VERSION 5.7 ;
BUSBITCHARS "[]" ;
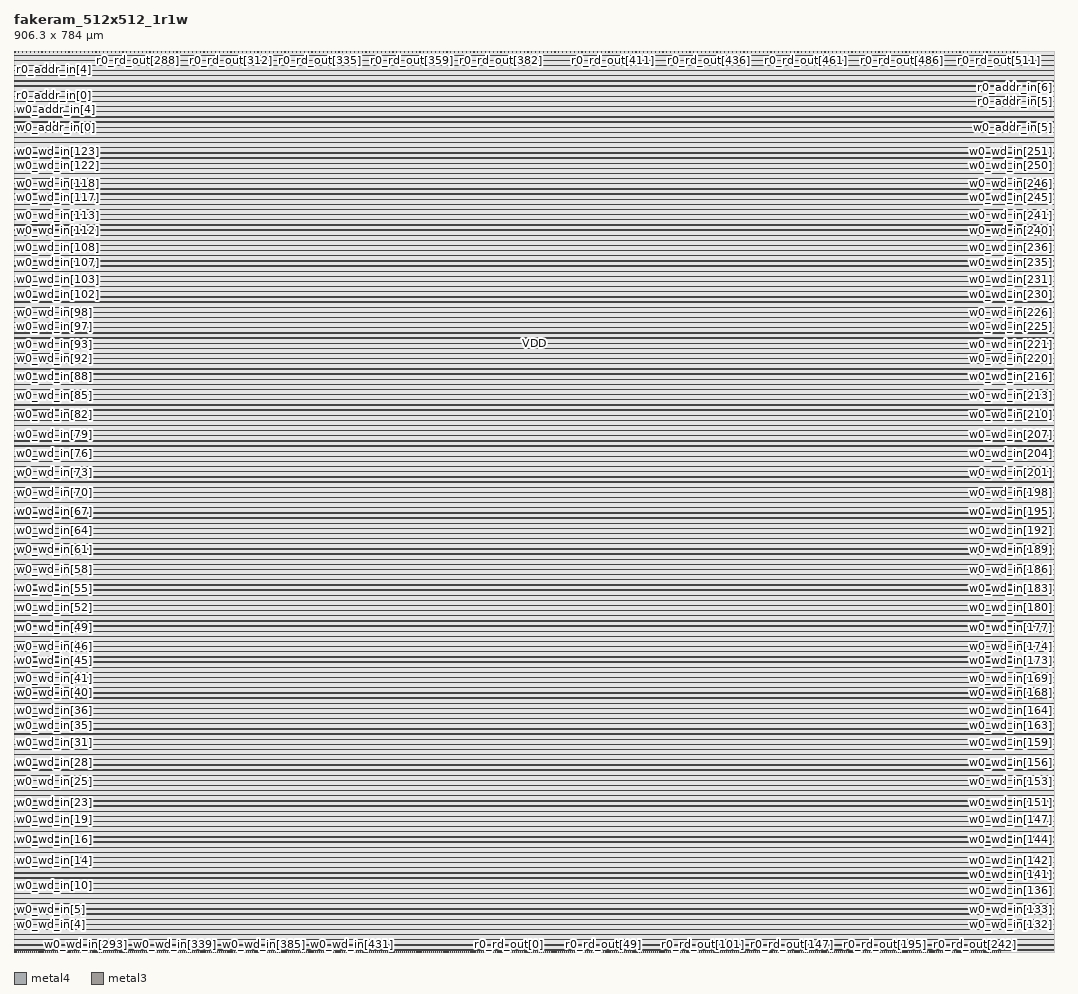
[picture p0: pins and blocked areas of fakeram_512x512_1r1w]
MACRO fakeram_512x512_1r1w
  FOREIGN fakeram_512x512_1r1w 0 0 ;
  SYMMETRY X Y R90 ;
  SIZE 906.300 BY 784.000 ;
  CLASS BLOCK ;
  PIN w0_wd_in[0]
    DIRECTION INPUT ;
    USE SIGNAL ;
    SHAPE ABUTMENT ;
    PORT
      LAYER metal4 ;
      RECT 0.000 1.645 0.210 1.715 ;
    END
  END w0_wd_in[0]
  PIN w0_wd_in[1]
    DIRECTION INPUT ;
    USE SIGNAL ;
    SHAPE ABUTMENT ;
    PORT
      LAYER metal4 ;
      RECT 0.000 7.245 0.210 7.315 ;
    END
  END w0_wd_in[1]
  PIN w0_wd_in[2]
    DIRECTION INPUT ;
    USE SIGNAL ;
    SHAPE ABUTMENT ;
    PORT
      LAYER metal4 ;
      RECT 0.000 12.845 0.210 12.915 ;
    END
  END w0_wd_in[2]
  PIN w0_wd_in[3]
    DIRECTION INPUT ;
    USE SIGNAL ;
    SHAPE ABUTMENT ;
    PORT
      LAYER metal4 ;
      RECT 0.000 18.445 0.210 18.515 ;
    END
  END w0_wd_in[3]
  PIN w0_wd_in[4]
    DIRECTION INPUT ;
    USE SIGNAL ;
    SHAPE ABUTMENT ;
    PORT
      LAYER metal4 ;
      RECT 0.000 24.045 0.210 24.115 ;
    END
  END w0_wd_in[4]
  PIN w0_wd_in[5]
    DIRECTION INPUT ;
    USE SIGNAL ;
    SHAPE ABUTMENT ;
    PORT
      LAYER metal4 ;
      RECT 0.000 29.645 0.210 29.715 ;
    END
  END w0_wd_in[5]
  PIN w0_wd_in[6]
    DIRECTION INPUT ;
    USE SIGNAL ;
    SHAPE ABUTMENT ;
    PORT
      LAYER metal4 ;
      RECT 0.000 35.245 0.210 35.315 ;
    END
  END w0_wd_in[6]
  PIN w0_wd_in[7]
    DIRECTION INPUT ;
    USE SIGNAL ;
    SHAPE ABUTMENT ;
    PORT
      LAYER metal4 ;
      RECT 0.000 40.845 0.210 40.915 ;
    END
  END w0_wd_in[7]
  PIN w0_wd_in[8]
    DIRECTION INPUT ;
    USE SIGNAL ;
    SHAPE ABUTMENT ;
    PORT
      LAYER metal4 ;
      RECT 0.000 46.445 0.210 46.515 ;
    END
  END w0_wd_in[8]
  PIN w0_wd_in[9]
    DIRECTION INPUT ;
    USE SIGNAL ;
    SHAPE ABUTMENT ;
    PORT
      LAYER metal4 ;
      RECT 0.000 52.045 0.210 52.115 ;
    END
  END w0_wd_in[9]
  PIN w0_wd_in[10]
    DIRECTION INPUT ;
    USE SIGNAL ;
    SHAPE ABUTMENT ;
    PORT
      LAYER metal4 ;
      RECT 0.000 57.645 0.210 57.715 ;
    END
  END w0_wd_in[10]
  PIN w0_wd_in[11]
    DIRECTION INPUT ;
    USE SIGNAL ;
    SHAPE ABUTMENT ;
    PORT
      LAYER metal4 ;
      RECT 0.000 63.245 0.210 63.315 ;
    END
  END w0_wd_in[11]
  PIN w0_wd_in[12]
    DIRECTION INPUT ;
    USE SIGNAL ;
    SHAPE ABUTMENT ;
    PORT
      LAYER metal4 ;
      RECT 0.000 68.845 0.210 68.915 ;
    END
  END w0_wd_in[12]
  PIN w0_wd_in[13]
    DIRECTION INPUT ;
    USE SIGNAL ;
    SHAPE ABUTMENT ;
    PORT
      LAYER metal4 ;
      RECT 0.000 74.445 0.210 74.515 ;
    END
  END w0_wd_in[13]
  PIN w0_wd_in[14]
    DIRECTION INPUT ;
    USE SIGNAL ;
    SHAPE ABUTMENT ;
    PORT
      LAYER metal4 ;
      RECT 0.000 80.045 0.210 80.115 ;
    END
  END w0_wd_in[14]
  PIN w0_wd_in[15]
    DIRECTION INPUT ;
    USE SIGNAL ;
    SHAPE ABUTMENT ;
    PORT
      LAYER metal4 ;
      RECT 0.000 85.645 0.210 85.715 ;
    END
  END w0_wd_in[15]
  PIN w0_wd_in[16]
    DIRECTION INPUT ;
    USE SIGNAL ;
    SHAPE ABUTMENT ;
    PORT
      LAYER metal4 ;
      RECT 0.000 91.245 0.210 91.315 ;
    END
  END w0_wd_in[16]
  PIN w0_wd_in[17]
    DIRECTION INPUT ;
    USE SIGNAL ;
    SHAPE ABUTMENT ;
    PORT
      LAYER metal4 ;
      RECT 0.000 96.845 0.210 96.915 ;
    END
  END w0_wd_in[17]
  PIN w0_wd_in[18]
    DIRECTION INPUT ;
    USE SIGNAL ;
    SHAPE ABUTMENT ;
    PORT
      LAYER metal4 ;
      RECT 0.000 102.445 0.210 102.515 ;
    END
  END w0_wd_in[18]
  PIN w0_wd_in[19]
    DIRECTION INPUT ;
    USE SIGNAL ;
    SHAPE ABUTMENT ;
    PORT
      LAYER metal4 ;
      RECT 0.000 108.045 0.210 108.115 ;
    END
  END w0_wd_in[19]
  PIN w0_wd_in[20]
    DIRECTION INPUT ;
    USE SIGNAL ;
    SHAPE ABUTMENT ;
    PORT
      LAYER metal4 ;
      RECT 0.000 113.645 0.210 113.715 ;
    END
  END w0_wd_in[20]
  PIN w0_wd_in[21]
    DIRECTION INPUT ;
    USE SIGNAL ;
    SHAPE ABUTMENT ;
    PORT
      LAYER metal4 ;
      RECT 0.000 119.245 0.210 119.315 ;
    END
  END w0_wd_in[21]
  PIN w0_wd_in[22]
    DIRECTION INPUT ;
    USE SIGNAL ;
    SHAPE ABUTMENT ;
    PORT
      LAYER metal4 ;
      RECT 0.000 124.845 0.210 124.915 ;
    END
  END w0_wd_in[22]
  PIN w0_wd_in[23]
    DIRECTION INPUT ;
    USE SIGNAL ;
    SHAPE ABUTMENT ;
    PORT
      LAYER metal4 ;
      RECT 0.000 130.445 0.210 130.515 ;
    END
  END w0_wd_in[23]
  PIN w0_wd_in[24]
    DIRECTION INPUT ;
    USE SIGNAL ;
    SHAPE ABUTMENT ;
    PORT
      LAYER metal4 ;
      RECT 0.000 136.045 0.210 136.115 ;
    END
  END w0_wd_in[24]
  PIN w0_wd_in[25]
    DIRECTION INPUT ;
    USE SIGNAL ;
    SHAPE ABUTMENT ;
    PORT
      LAYER metal4 ;
      RECT 0.000 141.645 0.210 141.715 ;
    END
  END w0_wd_in[25]
  PIN w0_wd_in[26]
    DIRECTION INPUT ;
    USE SIGNAL ;
    SHAPE ABUTMENT ;
    PORT
      LAYER metal4 ;
      RECT 0.000 147.245 0.210 147.315 ;
    END
  END w0_wd_in[26]
  PIN w0_wd_in[27]
    DIRECTION INPUT ;
    USE SIGNAL ;
    SHAPE ABUTMENT ;
    PORT
      LAYER metal4 ;
      RECT 0.000 152.845 0.210 152.915 ;
    END
  END w0_wd_in[27]
  PIN w0_wd_in[28]
    DIRECTION INPUT ;
    USE SIGNAL ;
    SHAPE ABUTMENT ;
    PORT
      LAYER metal4 ;
      RECT 0.000 158.445 0.210 158.515 ;
    END
  END w0_wd_in[28]
  PIN w0_wd_in[29]
    DIRECTION INPUT ;
    USE SIGNAL ;
    SHAPE ABUTMENT ;
    PORT
      LAYER metal4 ;
      RECT 0.000 164.045 0.210 164.115 ;
    END
  END w0_wd_in[29]
  PIN w0_wd_in[30]
    DIRECTION INPUT ;
    USE SIGNAL ;
    SHAPE ABUTMENT ;
    PORT
      LAYER metal4 ;
      RECT 0.000 169.645 0.210 169.715 ;
    END
  END w0_wd_in[30]
  PIN w0_wd_in[31]
    DIRECTION INPUT ;
    USE SIGNAL ;
    SHAPE ABUTMENT ;
    PORT
      LAYER metal4 ;
      RECT 0.000 175.245 0.210 175.315 ;
    END
  END w0_wd_in[31]
  PIN w0_wd_in[32]
    DIRECTION INPUT ;
    USE SIGNAL ;
    SHAPE ABUTMENT ;
    PORT
      LAYER metal4 ;
      RECT 0.000 180.845 0.210 180.915 ;
    END
  END w0_wd_in[32]
  PIN w0_wd_in[33]
    DIRECTION INPUT ;
    USE SIGNAL ;
    SHAPE ABUTMENT ;
    PORT
      LAYER metal4 ;
      RECT 0.000 186.445 0.210 186.515 ;
    END
  END w0_wd_in[33]
  PIN w0_wd_in[34]
    DIRECTION INPUT ;
    USE SIGNAL ;
    SHAPE ABUTMENT ;
    PORT
      LAYER metal4 ;
      RECT 0.000 192.045 0.210 192.115 ;
    END
  END w0_wd_in[34]
  PIN w0_wd_in[35]
    DIRECTION INPUT ;
    USE SIGNAL ;
    SHAPE ABUTMENT ;
    PORT
      LAYER metal4 ;
      RECT 0.000 197.645 0.210 197.715 ;
    END
  END w0_wd_in[35]
  PIN w0_wd_in[36]
    DIRECTION INPUT ;
    USE SIGNAL ;
    SHAPE ABUTMENT ;
    PORT
      LAYER metal4 ;
      RECT 0.000 203.245 0.210 203.315 ;
    END
  END w0_wd_in[36]
  PIN w0_wd_in[37]
    DIRECTION INPUT ;
    USE SIGNAL ;
    SHAPE ABUTMENT ;
    PORT
      LAYER metal4 ;
      RECT 0.000 208.845 0.210 208.915 ;
    END
  END w0_wd_in[37]
  PIN w0_wd_in[38]
    DIRECTION INPUT ;
    USE SIGNAL ;
    SHAPE ABUTMENT ;
    PORT
      LAYER metal4 ;
      RECT 0.000 214.445 0.210 214.515 ;
    END
  END w0_wd_in[38]
  PIN w0_wd_in[39]
    DIRECTION INPUT ;
    USE SIGNAL ;
    SHAPE ABUTMENT ;
    PORT
      LAYER metal4 ;
      RECT 0.000 220.045 0.210 220.115 ;
    END
  END w0_wd_in[39]
  PIN w0_wd_in[40]
    DIRECTION INPUT ;
    USE SIGNAL ;
    SHAPE ABUTMENT ;
    PORT
      LAYER metal4 ;
      RECT 0.000 225.645 0.210 225.715 ;
    END
  END w0_wd_in[40]
  PIN w0_wd_in[41]
    DIRECTION INPUT ;
    USE SIGNAL ;
    SHAPE ABUTMENT ;
    PORT
      LAYER metal4 ;
      RECT 0.000 231.245 0.210 231.315 ;
    END
  END w0_wd_in[41]
  PIN w0_wd_in[42]
    DIRECTION INPUT ;
    USE SIGNAL ;
    SHAPE ABUTMENT ;
    PORT
      LAYER metal4 ;
      RECT 0.000 236.845 0.210 236.915 ;
    END
  END w0_wd_in[42]
  PIN w0_wd_in[43]
    DIRECTION INPUT ;
    USE SIGNAL ;
    SHAPE ABUTMENT ;
    PORT
      LAYER metal4 ;
      RECT 0.000 242.445 0.210 242.515 ;
    END
  END w0_wd_in[43]
  PIN w0_wd_in[44]
    DIRECTION INPUT ;
    USE SIGNAL ;
    SHAPE ABUTMENT ;
    PORT
      LAYER metal4 ;
      RECT 0.000 248.045 0.210 248.115 ;
    END
  END w0_wd_in[44]
  PIN w0_wd_in[45]
    DIRECTION INPUT ;
    USE SIGNAL ;
    SHAPE ABUTMENT ;
    PORT
      LAYER metal4 ;
      RECT 0.000 253.645 0.210 253.715 ;
    END
  END w0_wd_in[45]
  PIN w0_wd_in[46]
    DIRECTION INPUT ;
    USE SIGNAL ;
    SHAPE ABUTMENT ;
    PORT
      LAYER metal4 ;
      RECT 0.000 259.245 0.210 259.315 ;
    END
  END w0_wd_in[46]
  PIN w0_wd_in[47]
    DIRECTION INPUT ;
    USE SIGNAL ;
    SHAPE ABUTMENT ;
    PORT
      LAYER metal4 ;
      RECT 0.000 264.845 0.210 264.915 ;
    END
  END w0_wd_in[47]
  PIN w0_wd_in[48]
    DIRECTION INPUT ;
    USE SIGNAL ;
    SHAPE ABUTMENT ;
    PORT
      LAYER metal4 ;
      RECT 0.000 270.445 0.210 270.515 ;
    END
  END w0_wd_in[48]
  PIN w0_wd_in[49]
    DIRECTION INPUT ;
    USE SIGNAL ;
    SHAPE ABUTMENT ;
    PORT
      LAYER metal4 ;
      RECT 0.000 276.045 0.210 276.115 ;
    END
  END w0_wd_in[49]
  PIN w0_wd_in[50]
    DIRECTION INPUT ;
    USE SIGNAL ;
    SHAPE ABUTMENT ;
    PORT
      LAYER metal4 ;
      RECT 0.000 281.645 0.210 281.715 ;
    END
  END w0_wd_in[50]
  PIN w0_wd_in[51]
    DIRECTION INPUT ;
    USE SIGNAL ;
    SHAPE ABUTMENT ;
    PORT
      LAYER metal4 ;
      RECT 0.000 287.245 0.210 287.315 ;
    END
  END w0_wd_in[51]
  PIN w0_wd_in[52]
    DIRECTION INPUT ;
    USE SIGNAL ;
    SHAPE ABUTMENT ;
    PORT
      LAYER metal4 ;
      RECT 0.000 292.845 0.210 292.915 ;
    END
  END w0_wd_in[52]
  PIN w0_wd_in[53]
    DIRECTION INPUT ;
    USE SIGNAL ;
    SHAPE ABUTMENT ;
    PORT
      LAYER metal4 ;
      RECT 0.000 298.445 0.210 298.515 ;
    END
  END w0_wd_in[53]
  PIN w0_wd_in[54]
    DIRECTION INPUT ;
    USE SIGNAL ;
    SHAPE ABUTMENT ;
    PORT
      LAYER metal4 ;
      RECT 0.000 304.045 0.210 304.115 ;
    END
  END w0_wd_in[54]
  PIN w0_wd_in[55]
    DIRECTION INPUT ;
    USE SIGNAL ;
    SHAPE ABUTMENT ;
    PORT
      LAYER metal4 ;
      RECT 0.000 309.645 0.210 309.715 ;
    END
  END w0_wd_in[55]
  PIN w0_wd_in[56]
    DIRECTION INPUT ;
    USE SIGNAL ;
    SHAPE ABUTMENT ;
    PORT
      LAYER metal4 ;
      RECT 0.000 315.245 0.210 315.315 ;
    END
  END w0_wd_in[56]
  PIN w0_wd_in[57]
    DIRECTION INPUT ;
    USE SIGNAL ;
    SHAPE ABUTMENT ;
    PORT
      LAYER metal4 ;
      RECT 0.000 320.845 0.210 320.915 ;
    END
  END w0_wd_in[57]
  PIN w0_wd_in[58]
    DIRECTION INPUT ;
    USE SIGNAL ;
    SHAPE ABUTMENT ;
    PORT
      LAYER metal4 ;
      RECT 0.000 326.445 0.210 326.515 ;
    END
  END w0_wd_in[58]
  PIN w0_wd_in[59]
    DIRECTION INPUT ;
    USE SIGNAL ;
    SHAPE ABUTMENT ;
    PORT
      LAYER metal4 ;
      RECT 0.000 332.045 0.210 332.115 ;
    END
  END w0_wd_in[59]
  PIN w0_wd_in[60]
    DIRECTION INPUT ;
    USE SIGNAL ;
    SHAPE ABUTMENT ;
    PORT
      LAYER metal4 ;
      RECT 0.000 337.645 0.210 337.715 ;
    END
  END w0_wd_in[60]
  PIN w0_wd_in[61]
    DIRECTION INPUT ;
    USE SIGNAL ;
    SHAPE ABUTMENT ;
    PORT
      LAYER metal4 ;
      RECT 0.000 343.245 0.210 343.315 ;
    END
  END w0_wd_in[61]
  PIN w0_wd_in[62]
    DIRECTION INPUT ;
    USE SIGNAL ;
    SHAPE ABUTMENT ;
    PORT
      LAYER metal4 ;
      RECT 0.000 348.845 0.210 348.915 ;
    END
  END w0_wd_in[62]
  PIN w0_wd_in[63]
    DIRECTION INPUT ;
    USE SIGNAL ;
    SHAPE ABUTMENT ;
    PORT
      LAYER metal4 ;
      RECT 0.000 354.445 0.210 354.515 ;
    END
  END w0_wd_in[63]
  PIN w0_wd_in[64]
    DIRECTION INPUT ;
    USE SIGNAL ;
    SHAPE ABUTMENT ;
    PORT
      LAYER metal4 ;
      RECT 0.000 360.045 0.210 360.115 ;
    END
  END w0_wd_in[64]
  PIN w0_wd_in[65]
    DIRECTION INPUT ;
    USE SIGNAL ;
    SHAPE ABUTMENT ;
    PORT
      LAYER metal4 ;
      RECT 0.000 365.645 0.210 365.715 ;
    END
  END w0_wd_in[65]
  PIN w0_wd_in[66]
    DIRECTION INPUT ;
    USE SIGNAL ;
    SHAPE ABUTMENT ;
    PORT
      LAYER metal4 ;
      RECT 0.000 371.245 0.210 371.315 ;
    END
  END w0_wd_in[66]
  PIN w0_wd_in[67]
    DIRECTION INPUT ;
    USE SIGNAL ;
    SHAPE ABUTMENT ;
    PORT
      LAYER metal4 ;
      RECT 0.000 376.845 0.210 376.915 ;
    END
  END w0_wd_in[67]
  PIN w0_wd_in[68]
    DIRECTION INPUT ;
    USE SIGNAL ;
    SHAPE ABUTMENT ;
    PORT
      LAYER metal4 ;
      RECT 0.000 382.445 0.210 382.515 ;
    END
  END w0_wd_in[68]
  PIN w0_wd_in[69]
    DIRECTION INPUT ;
    USE SIGNAL ;
    SHAPE ABUTMENT ;
    PORT
      LAYER metal4 ;
      RECT 0.000 388.045 0.210 388.115 ;
    END
  END w0_wd_in[69]
  PIN w0_wd_in[70]
    DIRECTION INPUT ;
    USE SIGNAL ;
    SHAPE ABUTMENT ;
    PORT
      LAYER metal4 ;
      RECT 0.000 393.645 0.210 393.715 ;
    END
  END w0_wd_in[70]
  PIN w0_wd_in[71]
    DIRECTION INPUT ;
    USE SIGNAL ;
    SHAPE ABUTMENT ;
    PORT
      LAYER metal4 ;
      RECT 0.000 399.245 0.210 399.315 ;
    END
  END w0_wd_in[71]
  PIN w0_wd_in[72]
    DIRECTION INPUT ;
    USE SIGNAL ;
    SHAPE ABUTMENT ;
    PORT
      LAYER metal4 ;
      RECT 0.000 404.845 0.210 404.915 ;
    END
  END w0_wd_in[72]
  PIN w0_wd_in[73]
    DIRECTION INPUT ;
    USE SIGNAL ;
    SHAPE ABUTMENT ;
    PORT
      LAYER metal4 ;
      RECT 0.000 410.445 0.210 410.515 ;
    END
  END w0_wd_in[73]
  PIN w0_wd_in[74]
    DIRECTION INPUT ;
    USE SIGNAL ;
    SHAPE ABUTMENT ;
    PORT
      LAYER metal4 ;
      RECT 0.000 416.045 0.210 416.115 ;
    END
  END w0_wd_in[74]
  PIN w0_wd_in[75]
    DIRECTION INPUT ;
    USE SIGNAL ;
    SHAPE ABUTMENT ;
    PORT
      LAYER metal4 ;
      RECT 0.000 421.645 0.210 421.715 ;
    END
  END w0_wd_in[75]
  PIN w0_wd_in[76]
    DIRECTION INPUT ;
    USE SIGNAL ;
    SHAPE ABUTMENT ;
    PORT
      LAYER metal4 ;
      RECT 0.000 427.245 0.210 427.315 ;
    END
  END w0_wd_in[76]
  PIN w0_wd_in[77]
    DIRECTION INPUT ;
    USE SIGNAL ;
    SHAPE ABUTMENT ;
    PORT
      LAYER metal4 ;
      RECT 0.000 432.845 0.210 432.915 ;
    END
  END w0_wd_in[77]
  PIN w0_wd_in[78]
    DIRECTION INPUT ;
    USE SIGNAL ;
    SHAPE ABUTMENT ;
    PORT
      LAYER metal4 ;
      RECT 0.000 438.445 0.210 438.515 ;
    END
  END w0_wd_in[78]
  PIN w0_wd_in[79]
    DIRECTION INPUT ;
    USE SIGNAL ;
    SHAPE ABUTMENT ;
    PORT
      LAYER metal4 ;
      RECT 0.000 444.045 0.210 444.115 ;
    END
  END w0_wd_in[79]
  PIN w0_wd_in[80]
    DIRECTION INPUT ;
    USE SIGNAL ;
    SHAPE ABUTMENT ;
    PORT
      LAYER metal4 ;
      RECT 0.000 449.645 0.210 449.715 ;
    END
  END w0_wd_in[80]
  PIN w0_wd_in[81]
    DIRECTION INPUT ;
    USE SIGNAL ;
    SHAPE ABUTMENT ;
    PORT
      LAYER metal4 ;
      RECT 0.000 455.245 0.210 455.315 ;
    END
  END w0_wd_in[81]
  PIN w0_wd_in[82]
    DIRECTION INPUT ;
    USE SIGNAL ;
    SHAPE ABUTMENT ;
    PORT
      LAYER metal4 ;
      RECT 0.000 460.845 0.210 460.915 ;
    END
  END w0_wd_in[82]
  PIN w0_wd_in[83]
    DIRECTION INPUT ;
    USE SIGNAL ;
    SHAPE ABUTMENT ;
    PORT
      LAYER metal4 ;
      RECT 0.000 466.445 0.210 466.515 ;
    END
  END w0_wd_in[83]
  PIN w0_wd_in[84]
    DIRECTION INPUT ;
    USE SIGNAL ;
    SHAPE ABUTMENT ;
    PORT
      LAYER metal4 ;
      RECT 0.000 472.045 0.210 472.115 ;
    END
  END w0_wd_in[84]
  PIN w0_wd_in[85]
    DIRECTION INPUT ;
    USE SIGNAL ;
    SHAPE ABUTMENT ;
    PORT
      LAYER metal4 ;
      RECT 0.000 477.645 0.210 477.715 ;
    END
  END w0_wd_in[85]
  PIN w0_wd_in[86]
    DIRECTION INPUT ;
    USE SIGNAL ;
    SHAPE ABUTMENT ;
    PORT
      LAYER metal4 ;
      RECT 0.000 483.245 0.210 483.315 ;
    END
  END w0_wd_in[86]
  PIN w0_wd_in[87]
    DIRECTION INPUT ;
    USE SIGNAL ;
    SHAPE ABUTMENT ;
    PORT
      LAYER metal4 ;
      RECT 0.000 488.845 0.210 488.915 ;
    END
  END w0_wd_in[87]
  PIN w0_wd_in[88]
    DIRECTION INPUT ;
    USE SIGNAL ;
    SHAPE ABUTMENT ;
    PORT
      LAYER metal4 ;
      RECT 0.000 494.445 0.210 494.515 ;
    END
  END w0_wd_in[88]
  PIN w0_wd_in[89]
    DIRECTION INPUT ;
    USE SIGNAL ;
    SHAPE ABUTMENT ;
    PORT
      LAYER metal4 ;
      RECT 0.000 500.045 0.210 500.115 ;
    END
  END w0_wd_in[89]
  PIN w0_wd_in[90]
    DIRECTION INPUT ;
    USE SIGNAL ;
    SHAPE ABUTMENT ;
    PORT
      LAYER metal4 ;
      RECT 0.000 505.645 0.210 505.715 ;
    END
  END w0_wd_in[90]
  PIN w0_wd_in[91]
    DIRECTION INPUT ;
    USE SIGNAL ;
    SHAPE ABUTMENT ;
    PORT
      LAYER metal4 ;
      RECT 0.000 511.245 0.210 511.315 ;
    END
  END w0_wd_in[91]
  PIN w0_wd_in[92]
    DIRECTION INPUT ;
    USE SIGNAL ;
    SHAPE ABUTMENT ;
    PORT
      LAYER metal4 ;
      RECT 0.000 516.845 0.210 516.915 ;
    END
  END w0_wd_in[92]
  PIN w0_wd_in[93]
    DIRECTION INPUT ;
    USE SIGNAL ;
    SHAPE ABUTMENT ;
    PORT
      LAYER metal4 ;
      RECT 0.000 522.445 0.210 522.515 ;
    END
  END w0_wd_in[93]
  PIN w0_wd_in[94]
    DIRECTION INPUT ;
    USE SIGNAL ;
    SHAPE ABUTMENT ;
    PORT
      LAYER metal4 ;
      RECT 0.000 528.045 0.210 528.115 ;
    END
  END w0_wd_in[94]
  PIN w0_wd_in[95]
    DIRECTION INPUT ;
    USE SIGNAL ;
    SHAPE ABUTMENT ;
    PORT
      LAYER metal4 ;
      RECT 0.000 533.645 0.210 533.715 ;
    END
  END w0_wd_in[95]
  PIN w0_wd_in[96]
    DIRECTION INPUT ;
    USE SIGNAL ;
    SHAPE ABUTMENT ;
    PORT
      LAYER metal4 ;
      RECT 0.000 539.245 0.210 539.315 ;
    END
  END w0_wd_in[96]
  PIN w0_wd_in[97]
    DIRECTION INPUT ;
    USE SIGNAL ;
    SHAPE ABUTMENT ;
    PORT
      LAYER metal4 ;
      RECT 0.000 544.845 0.210 544.915 ;
    END
  END w0_wd_in[97]
  PIN w0_wd_in[98]
    DIRECTION INPUT ;
    USE SIGNAL ;
    SHAPE ABUTMENT ;
    PORT
      LAYER metal4 ;
      RECT 0.000 550.445 0.210 550.515 ;
    END
  END w0_wd_in[98]
  PIN w0_wd_in[99]
    DIRECTION INPUT ;
    USE SIGNAL ;
    SHAPE ABUTMENT ;
    PORT
      LAYER metal4 ;
      RECT 0.000 556.045 0.210 556.115 ;
    END
  END w0_wd_in[99]
  PIN w0_wd_in[100]
    DIRECTION INPUT ;
    USE SIGNAL ;
    SHAPE ABUTMENT ;
    PORT
      LAYER metal4 ;
      RECT 0.000 561.645 0.210 561.715 ;
    END
  END w0_wd_in[100]
  PIN w0_wd_in[101]
    DIRECTION INPUT ;
    USE SIGNAL ;
    SHAPE ABUTMENT ;
    PORT
      LAYER metal4 ;
      RECT 0.000 567.245 0.210 567.315 ;
    END
  END w0_wd_in[101]
  PIN w0_wd_in[102]
    DIRECTION INPUT ;
    USE SIGNAL ;
    SHAPE ABUTMENT ;
    PORT
      LAYER metal4 ;
      RECT 0.000 572.845 0.210 572.915 ;
    END
  END w0_wd_in[102]
  PIN w0_wd_in[103]
    DIRECTION INPUT ;
    USE SIGNAL ;
    SHAPE ABUTMENT ;
    PORT
      LAYER metal4 ;
      RECT 0.000 578.445 0.210 578.515 ;
    END
  END w0_wd_in[103]
  PIN w0_wd_in[104]
    DIRECTION INPUT ;
    USE SIGNAL ;
    SHAPE ABUTMENT ;
    PORT
      LAYER metal4 ;
      RECT 0.000 584.045 0.210 584.115 ;
    END
  END w0_wd_in[104]
  PIN w0_wd_in[105]
    DIRECTION INPUT ;
    USE SIGNAL ;
    SHAPE ABUTMENT ;
    PORT
      LAYER metal4 ;
      RECT 0.000 589.645 0.210 589.715 ;
    END
  END w0_wd_in[105]
  PIN w0_wd_in[106]
    DIRECTION INPUT ;
    USE SIGNAL ;
    SHAPE ABUTMENT ;
    PORT
      LAYER metal4 ;
      RECT 0.000 595.245 0.210 595.315 ;
    END
  END w0_wd_in[106]
  PIN w0_wd_in[107]
    DIRECTION INPUT ;
    USE SIGNAL ;
    SHAPE ABUTMENT ;
    PORT
      LAYER metal4 ;
      RECT 0.000 600.845 0.210 600.915 ;
    END
  END w0_wd_in[107]
  PIN w0_wd_in[108]
    DIRECTION INPUT ;
    USE SIGNAL ;
    SHAPE ABUTMENT ;
    PORT
      LAYER metal4 ;
      RECT 0.000 606.445 0.210 606.515 ;
    END
  END w0_wd_in[108]
  PIN w0_wd_in[109]
    DIRECTION INPUT ;
    USE SIGNAL ;
    SHAPE ABUTMENT ;
    PORT
      LAYER metal4 ;
      RECT 0.000 612.045 0.210 612.115 ;
    END
  END w0_wd_in[109]
  PIN w0_wd_in[110]
    DIRECTION INPUT ;
    USE SIGNAL ;
    SHAPE ABUTMENT ;
    PORT
      LAYER metal4 ;
      RECT 0.000 617.645 0.210 617.715 ;
    END
  END w0_wd_in[110]
  PIN w0_wd_in[111]
    DIRECTION INPUT ;
    USE SIGNAL ;
    SHAPE ABUTMENT ;
    PORT
      LAYER metal4 ;
      RECT 0.000 623.245 0.210 623.315 ;
    END
  END w0_wd_in[111]
  PIN w0_wd_in[112]
    DIRECTION INPUT ;
    USE SIGNAL ;
    SHAPE ABUTMENT ;
    PORT
      LAYER metal4 ;
      RECT 0.000 628.845 0.210 628.915 ;
    END
  END w0_wd_in[112]
  PIN w0_wd_in[113]
    DIRECTION INPUT ;
    USE SIGNAL ;
    SHAPE ABUTMENT ;
    PORT
      LAYER metal4 ;
      RECT 0.000 634.445 0.210 634.515 ;
    END
  END w0_wd_in[113]
  PIN w0_wd_in[114]
    DIRECTION INPUT ;
    USE SIGNAL ;
    SHAPE ABUTMENT ;
    PORT
      LAYER metal4 ;
      RECT 0.000 640.045 0.210 640.115 ;
    END
  END w0_wd_in[114]
  PIN w0_wd_in[115]
    DIRECTION INPUT ;
    USE SIGNAL ;
    SHAPE ABUTMENT ;
    PORT
      LAYER metal4 ;
      RECT 0.000 645.645 0.210 645.715 ;
    END
  END w0_wd_in[115]
  PIN w0_wd_in[116]
    DIRECTION INPUT ;
    USE SIGNAL ;
    SHAPE ABUTMENT ;
    PORT
      LAYER metal4 ;
      RECT 0.000 651.245 0.210 651.315 ;
    END
  END w0_wd_in[116]
  PIN w0_wd_in[117]
    DIRECTION INPUT ;
    USE SIGNAL ;
    SHAPE ABUTMENT ;
    PORT
      LAYER metal4 ;
      RECT 0.000 656.845 0.210 656.915 ;
    END
  END w0_wd_in[117]
  PIN w0_wd_in[118]
    DIRECTION INPUT ;
    USE SIGNAL ;
    SHAPE ABUTMENT ;
    PORT
      LAYER metal4 ;
      RECT 0.000 662.445 0.210 662.515 ;
    END
  END w0_wd_in[118]
  PIN w0_wd_in[119]
    DIRECTION INPUT ;
    USE SIGNAL ;
    SHAPE ABUTMENT ;
    PORT
      LAYER metal4 ;
      RECT 0.000 668.045 0.210 668.115 ;
    END
  END w0_wd_in[119]
  PIN w0_wd_in[120]
    DIRECTION INPUT ;
    USE SIGNAL ;
    SHAPE ABUTMENT ;
    PORT
      LAYER metal4 ;
      RECT 0.000 673.645 0.210 673.715 ;
    END
  END w0_wd_in[120]
  PIN w0_wd_in[121]
    DIRECTION INPUT ;
    USE SIGNAL ;
    SHAPE ABUTMENT ;
    PORT
      LAYER metal4 ;
      RECT 0.000 679.245 0.210 679.315 ;
    END
  END w0_wd_in[121]
  PIN w0_wd_in[122]
    DIRECTION INPUT ;
    USE SIGNAL ;
    SHAPE ABUTMENT ;
    PORT
      LAYER metal4 ;
      RECT 0.000 684.845 0.210 684.915 ;
    END
  END w0_wd_in[122]
  PIN w0_wd_in[123]
    DIRECTION INPUT ;
    USE SIGNAL ;
    SHAPE ABUTMENT ;
    PORT
      LAYER metal4 ;
      RECT 0.000 690.445 0.210 690.515 ;
    END
  END w0_wd_in[123]
  PIN w0_wd_in[124]
    DIRECTION INPUT ;
    USE SIGNAL ;
    SHAPE ABUTMENT ;
    PORT
      LAYER metal4 ;
      RECT 0.000 696.045 0.210 696.115 ;
    END
  END w0_wd_in[124]
  PIN w0_wd_in[125]
    DIRECTION INPUT ;
    USE SIGNAL ;
    SHAPE ABUTMENT ;
    PORT
      LAYER metal4 ;
      RECT 0.000 701.645 0.210 701.715 ;
    END
  END w0_wd_in[125]
  PIN w0_wd_in[126]
    DIRECTION INPUT ;
    USE SIGNAL ;
    SHAPE ABUTMENT ;
    PORT
      LAYER metal4 ;
      RECT 0.000 707.245 0.210 707.315 ;
    END
  END w0_wd_in[126]
  PIN w0_wd_in[127]
    DIRECTION INPUT ;
    USE SIGNAL ;
    SHAPE ABUTMENT ;
    PORT
      LAYER metal4 ;
      RECT 0.000 712.845 0.210 712.915 ;
    END
  END w0_wd_in[127]
  PIN w0_wd_in[128]
    DIRECTION INPUT ;
    USE SIGNAL ;
    SHAPE ABUTMENT ;
    PORT
      LAYER metal4 ;
      RECT 906.090 1.645 906.300 1.715 ;
    END
  END w0_wd_in[128]
  PIN w0_wd_in[129]
    DIRECTION INPUT ;
    USE SIGNAL ;
    SHAPE ABUTMENT ;
    PORT
      LAYER metal4 ;
      RECT 906.090 7.245 906.300 7.315 ;
    END
  END w0_wd_in[129]
  PIN w0_wd_in[130]
    DIRECTION INPUT ;
    USE SIGNAL ;
    SHAPE ABUTMENT ;
    PORT
      LAYER metal4 ;
      RECT 906.090 12.845 906.300 12.915 ;
    END
  END w0_wd_in[130]
  PIN w0_wd_in[131]
    DIRECTION INPUT ;
    USE SIGNAL ;
    SHAPE ABUTMENT ;
    PORT
      LAYER metal4 ;
      RECT 906.090 18.445 906.300 18.515 ;
    END
  END w0_wd_in[131]
  PIN w0_wd_in[132]
    DIRECTION INPUT ;
    USE SIGNAL ;
    SHAPE ABUTMENT ;
    PORT
      LAYER metal4 ;
      RECT 906.090 24.045 906.300 24.115 ;
    END
  END w0_wd_in[132]
  PIN w0_wd_in[133]
    DIRECTION INPUT ;
    USE SIGNAL ;
    SHAPE ABUTMENT ;
    PORT
      LAYER metal4 ;
      RECT 906.090 29.645 906.300 29.715 ;
    END
  END w0_wd_in[133]
  PIN w0_wd_in[134]
    DIRECTION INPUT ;
    USE SIGNAL ;
    SHAPE ABUTMENT ;
    PORT
      LAYER metal4 ;
      RECT 906.090 35.245 906.300 35.315 ;
    END
  END w0_wd_in[134]
  PIN w0_wd_in[135]
    DIRECTION INPUT ;
    USE SIGNAL ;
    SHAPE ABUTMENT ;
    PORT
      LAYER metal4 ;
      RECT 906.090 40.845 906.300 40.915 ;
    END
  END w0_wd_in[135]
  PIN w0_wd_in[136]
    DIRECTION INPUT ;
    USE SIGNAL ;
    SHAPE ABUTMENT ;
    PORT
      LAYER metal4 ;
      RECT 906.090 46.445 906.300 46.515 ;
    END
  END w0_wd_in[136]
  PIN w0_wd_in[137]
    DIRECTION INPUT ;
    USE SIGNAL ;
    SHAPE ABUTMENT ;
    PORT
      LAYER metal4 ;
      RECT 906.090 52.045 906.300 52.115 ;
    END
  END w0_wd_in[137]
  PIN w0_wd_in[138]
    DIRECTION INPUT ;
    USE SIGNAL ;
    SHAPE ABUTMENT ;
    PORT
      LAYER metal4 ;
      RECT 906.090 57.645 906.300 57.715 ;
    END
  END w0_wd_in[138]
  PIN w0_wd_in[139]
    DIRECTION INPUT ;
    USE SIGNAL ;
    SHAPE ABUTMENT ;
    PORT
      LAYER metal4 ;
      RECT 906.090 63.245 906.300 63.315 ;
    END
  END w0_wd_in[139]
  PIN w0_wd_in[140]
    DIRECTION INPUT ;
    USE SIGNAL ;
    SHAPE ABUTMENT ;
    PORT
      LAYER metal4 ;
      RECT 906.090 68.845 906.300 68.915 ;
    END
  END w0_wd_in[140]
  PIN w0_wd_in[141]
    DIRECTION INPUT ;
    USE SIGNAL ;
    SHAPE ABUTMENT ;
    PORT
      LAYER metal4 ;
      RECT 906.090 74.445 906.300 74.515 ;
    END
  END w0_wd_in[141]
  PIN w0_wd_in[142]
    DIRECTION INPUT ;
    USE SIGNAL ;
    SHAPE ABUTMENT ;
    PORT
      LAYER metal4 ;
      RECT 906.090 80.045 906.300 80.115 ;
    END
  END w0_wd_in[142]
  PIN w0_wd_in[143]
    DIRECTION INPUT ;
    USE SIGNAL ;
    SHAPE ABUTMENT ;
    PORT
      LAYER metal4 ;
      RECT 906.090 85.645 906.300 85.715 ;
    END
  END w0_wd_in[143]
  PIN w0_wd_in[144]
    DIRECTION INPUT ;
    USE SIGNAL ;
    SHAPE ABUTMENT ;
    PORT
      LAYER metal4 ;
      RECT 906.090 91.245 906.300 91.315 ;
    END
  END w0_wd_in[144]
  PIN w0_wd_in[145]
    DIRECTION INPUT ;
    USE SIGNAL ;
    SHAPE ABUTMENT ;
    PORT
      LAYER metal4 ;
      RECT 906.090 96.845 906.300 96.915 ;
    END
  END w0_wd_in[145]
  PIN w0_wd_in[146]
    DIRECTION INPUT ;
    USE SIGNAL ;
    SHAPE ABUTMENT ;
    PORT
      LAYER metal4 ;
      RECT 906.090 102.445 906.300 102.515 ;
    END
  END w0_wd_in[146]
  PIN w0_wd_in[147]
    DIRECTION INPUT ;
    USE SIGNAL ;
    SHAPE ABUTMENT ;
    PORT
      LAYER metal4 ;
      RECT 906.090 108.045 906.300 108.115 ;
    END
  END w0_wd_in[147]
  PIN w0_wd_in[148]
    DIRECTION INPUT ;
    USE SIGNAL ;
    SHAPE ABUTMENT ;
    PORT
      LAYER metal4 ;
      RECT 906.090 113.645 906.300 113.715 ;
    END
  END w0_wd_in[148]
  PIN w0_wd_in[149]
    DIRECTION INPUT ;
    USE SIGNAL ;
    SHAPE ABUTMENT ;
    PORT
      LAYER metal4 ;
      RECT 906.090 119.245 906.300 119.315 ;
    END
  END w0_wd_in[149]
  PIN w0_wd_in[150]
    DIRECTION INPUT ;
    USE SIGNAL ;
    SHAPE ABUTMENT ;
    PORT
      LAYER metal4 ;
      RECT 906.090 124.845 906.300 124.915 ;
    END
  END w0_wd_in[150]
  PIN w0_wd_in[151]
    DIRECTION INPUT ;
    USE SIGNAL ;
    SHAPE ABUTMENT ;
    PORT
      LAYER metal4 ;
      RECT 906.090 130.445 906.300 130.515 ;
    END
  END w0_wd_in[151]
  PIN w0_wd_in[152]
    DIRECTION INPUT ;
    USE SIGNAL ;
    SHAPE ABUTMENT ;
    PORT
      LAYER metal4 ;
      RECT 906.090 136.045 906.300 136.115 ;
    END
  END w0_wd_in[152]
  PIN w0_wd_in[153]
    DIRECTION INPUT ;
    USE SIGNAL ;
    SHAPE ABUTMENT ;
    PORT
      LAYER metal4 ;
      RECT 906.090 141.645 906.300 141.715 ;
    END
  END w0_wd_in[153]
  PIN w0_wd_in[154]
    DIRECTION INPUT ;
    USE SIGNAL ;
    SHAPE ABUTMENT ;
    PORT
      LAYER metal4 ;
      RECT 906.090 147.245 906.300 147.315 ;
    END
  END w0_wd_in[154]
  PIN w0_wd_in[155]
    DIRECTION INPUT ;
    USE SIGNAL ;
    SHAPE ABUTMENT ;
    PORT
      LAYER metal4 ;
      RECT 906.090 152.845 906.300 152.915 ;
    END
  END w0_wd_in[155]
  PIN w0_wd_in[156]
    DIRECTION INPUT ;
    USE SIGNAL ;
    SHAPE ABUTMENT ;
    PORT
      LAYER metal4 ;
      RECT 906.090 158.445 906.300 158.515 ;
    END
  END w0_wd_in[156]
  PIN w0_wd_in[157]
    DIRECTION INPUT ;
    USE SIGNAL ;
    SHAPE ABUTMENT ;
    PORT
      LAYER metal4 ;
      RECT 906.090 164.045 906.300 164.115 ;
    END
  END w0_wd_in[157]
  PIN w0_wd_in[158]
    DIRECTION INPUT ;
    USE SIGNAL ;
    SHAPE ABUTMENT ;
    PORT
      LAYER metal4 ;
      RECT 906.090 169.645 906.300 169.715 ;
    END
  END w0_wd_in[158]
  PIN w0_wd_in[159]
    DIRECTION INPUT ;
    USE SIGNAL ;
    SHAPE ABUTMENT ;
    PORT
      LAYER metal4 ;
      RECT 906.090 175.245 906.300 175.315 ;
    END
  END w0_wd_in[159]
  PIN w0_wd_in[160]
    DIRECTION INPUT ;
    USE SIGNAL ;
    SHAPE ABUTMENT ;
    PORT
      LAYER metal4 ;
      RECT 906.090 180.845 906.300 180.915 ;
    END
  END w0_wd_in[160]
  PIN w0_wd_in[161]
    DIRECTION INPUT ;
    USE SIGNAL ;
    SHAPE ABUTMENT ;
    PORT
      LAYER metal4 ;
      RECT 906.090 186.445 906.300 186.515 ;
    END
  END w0_wd_in[161]
  PIN w0_wd_in[162]
    DIRECTION INPUT ;
    USE SIGNAL ;
    SHAPE ABUTMENT ;
    PORT
      LAYER metal4 ;
      RECT 906.090 192.045 906.300 192.115 ;
    END
  END w0_wd_in[162]
  PIN w0_wd_in[163]
    DIRECTION INPUT ;
    USE SIGNAL ;
    SHAPE ABUTMENT ;
    PORT
      LAYER metal4 ;
      RECT 906.090 197.645 906.300 197.715 ;
    END
  END w0_wd_in[163]
  PIN w0_wd_in[164]
    DIRECTION INPUT ;
    USE SIGNAL ;
    SHAPE ABUTMENT ;
    PORT
      LAYER metal4 ;
      RECT 906.090 203.245 906.300 203.315 ;
    END
  END w0_wd_in[164]
  PIN w0_wd_in[165]
    DIRECTION INPUT ;
    USE SIGNAL ;
    SHAPE ABUTMENT ;
    PORT
      LAYER metal4 ;
      RECT 906.090 208.845 906.300 208.915 ;
    END
  END w0_wd_in[165]
  PIN w0_wd_in[166]
    DIRECTION INPUT ;
    USE SIGNAL ;
    SHAPE ABUTMENT ;
    PORT
      LAYER metal4 ;
      RECT 906.090 214.445 906.300 214.515 ;
    END
  END w0_wd_in[166]
  PIN w0_wd_in[167]
    DIRECTION INPUT ;
    USE SIGNAL ;
    SHAPE ABUTMENT ;
    PORT
      LAYER metal4 ;
      RECT 906.090 220.045 906.300 220.115 ;
    END
  END w0_wd_in[167]
  PIN w0_wd_in[168]
    DIRECTION INPUT ;
    USE SIGNAL ;
    SHAPE ABUTMENT ;
    PORT
      LAYER metal4 ;
      RECT 906.090 225.645 906.300 225.715 ;
    END
  END w0_wd_in[168]
  PIN w0_wd_in[169]
    DIRECTION INPUT ;
    USE SIGNAL ;
    SHAPE ABUTMENT ;
    PORT
      LAYER metal4 ;
      RECT 906.090 231.245 906.300 231.315 ;
    END
  END w0_wd_in[169]
  PIN w0_wd_in[170]
    DIRECTION INPUT ;
    USE SIGNAL ;
    SHAPE ABUTMENT ;
    PORT
      LAYER metal4 ;
      RECT 906.090 236.845 906.300 236.915 ;
    END
  END w0_wd_in[170]
  PIN w0_wd_in[171]
    DIRECTION INPUT ;
    USE SIGNAL ;
    SHAPE ABUTMENT ;
    PORT
      LAYER metal4 ;
      RECT 906.090 242.445 906.300 242.515 ;
    END
  END w0_wd_in[171]
  PIN w0_wd_in[172]
    DIRECTION INPUT ;
    USE SIGNAL ;
    SHAPE ABUTMENT ;
    PORT
      LAYER metal4 ;
      RECT 906.090 248.045 906.300 248.115 ;
    END
  END w0_wd_in[172]
  PIN w0_wd_in[173]
    DIRECTION INPUT ;
    USE SIGNAL ;
    SHAPE ABUTMENT ;
    PORT
      LAYER metal4 ;
      RECT 906.090 253.645 906.300 253.715 ;
    END
  END w0_wd_in[173]
  PIN w0_wd_in[174]
    DIRECTION INPUT ;
    USE SIGNAL ;
    SHAPE ABUTMENT ;
    PORT
      LAYER metal4 ;
      RECT 906.090 259.245 906.300 259.315 ;
    END
  END w0_wd_in[174]
  PIN w0_wd_in[175]
    DIRECTION INPUT ;
    USE SIGNAL ;
    SHAPE ABUTMENT ;
    PORT
      LAYER metal4 ;
      RECT 906.090 264.845 906.300 264.915 ;
    END
  END w0_wd_in[175]
  PIN w0_wd_in[176]
    DIRECTION INPUT ;
    USE SIGNAL ;
    SHAPE ABUTMENT ;
    PORT
      LAYER metal4 ;
      RECT 906.090 270.445 906.300 270.515 ;
    END
  END w0_wd_in[176]
  PIN w0_wd_in[177]
    DIRECTION INPUT ;
    USE SIGNAL ;
    SHAPE ABUTMENT ;
    PORT
      LAYER metal4 ;
      RECT 906.090 276.045 906.300 276.115 ;
    END
  END w0_wd_in[177]
  PIN w0_wd_in[178]
    DIRECTION INPUT ;
    USE SIGNAL ;
    SHAPE ABUTMENT ;
    PORT
      LAYER metal4 ;
      RECT 906.090 281.645 906.300 281.715 ;
    END
  END w0_wd_in[178]
  PIN w0_wd_in[179]
    DIRECTION INPUT ;
    USE SIGNAL ;
    SHAPE ABUTMENT ;
    PORT
      LAYER metal4 ;
      RECT 906.090 287.245 906.300 287.315 ;
    END
  END w0_wd_in[179]
  PIN w0_wd_in[180]
    DIRECTION INPUT ;
    USE SIGNAL ;
    SHAPE ABUTMENT ;
    PORT
      LAYER metal4 ;
      RECT 906.090 292.845 906.300 292.915 ;
    END
  END w0_wd_in[180]
  PIN w0_wd_in[181]
    DIRECTION INPUT ;
    USE SIGNAL ;
    SHAPE ABUTMENT ;
    PORT
      LAYER metal4 ;
      RECT 906.090 298.445 906.300 298.515 ;
    END
  END w0_wd_in[181]
  PIN w0_wd_in[182]
    DIRECTION INPUT ;
    USE SIGNAL ;
    SHAPE ABUTMENT ;
    PORT
      LAYER metal4 ;
      RECT 906.090 304.045 906.300 304.115 ;
    END
  END w0_wd_in[182]
  PIN w0_wd_in[183]
    DIRECTION INPUT ;
    USE SIGNAL ;
    SHAPE ABUTMENT ;
    PORT
      LAYER metal4 ;
      RECT 906.090 309.645 906.300 309.715 ;
    END
  END w0_wd_in[183]
  PIN w0_wd_in[184]
    DIRECTION INPUT ;
    USE SIGNAL ;
    SHAPE ABUTMENT ;
    PORT
      LAYER metal4 ;
      RECT 906.090 315.245 906.300 315.315 ;
    END
  END w0_wd_in[184]
  PIN w0_wd_in[185]
    DIRECTION INPUT ;
    USE SIGNAL ;
    SHAPE ABUTMENT ;
    PORT
      LAYER metal4 ;
      RECT 906.090 320.845 906.300 320.915 ;
    END
  END w0_wd_in[185]
  PIN w0_wd_in[186]
    DIRECTION INPUT ;
    USE SIGNAL ;
    SHAPE ABUTMENT ;
    PORT
      LAYER metal4 ;
      RECT 906.090 326.445 906.300 326.515 ;
    END
  END w0_wd_in[186]
  PIN w0_wd_in[187]
    DIRECTION INPUT ;
    USE SIGNAL ;
    SHAPE ABUTMENT ;
    PORT
      LAYER metal4 ;
      RECT 906.090 332.045 906.300 332.115 ;
    END
  END w0_wd_in[187]
  PIN w0_wd_in[188]
    DIRECTION INPUT ;
    USE SIGNAL ;
    SHAPE ABUTMENT ;
    PORT
      LAYER metal4 ;
      RECT 906.090 337.645 906.300 337.715 ;
    END
  END w0_wd_in[188]
  PIN w0_wd_in[189]
    DIRECTION INPUT ;
    USE SIGNAL ;
    SHAPE ABUTMENT ;
    PORT
      LAYER metal4 ;
      RECT 906.090 343.245 906.300 343.315 ;
    END
  END w0_wd_in[189]
  PIN w0_wd_in[190]
    DIRECTION INPUT ;
    USE SIGNAL ;
    SHAPE ABUTMENT ;
    PORT
      LAYER metal4 ;
      RECT 906.090 348.845 906.300 348.915 ;
    END
  END w0_wd_in[190]
  PIN w0_wd_in[191]
    DIRECTION INPUT ;
    USE SIGNAL ;
    SHAPE ABUTMENT ;
    PORT
      LAYER metal4 ;
      RECT 906.090 354.445 906.300 354.515 ;
    END
  END w0_wd_in[191]
  PIN w0_wd_in[192]
    DIRECTION INPUT ;
    USE SIGNAL ;
    SHAPE ABUTMENT ;
    PORT
      LAYER metal4 ;
      RECT 906.090 360.045 906.300 360.115 ;
    END
  END w0_wd_in[192]
  PIN w0_wd_in[193]
    DIRECTION INPUT ;
    USE SIGNAL ;
    SHAPE ABUTMENT ;
    PORT
      LAYER metal4 ;
      RECT 906.090 365.645 906.300 365.715 ;
    END
  END w0_wd_in[193]
  PIN w0_wd_in[194]
    DIRECTION INPUT ;
    USE SIGNAL ;
    SHAPE ABUTMENT ;
    PORT
      LAYER metal4 ;
      RECT 906.090 371.245 906.300 371.315 ;
    END
  END w0_wd_in[194]
  PIN w0_wd_in[195]
    DIRECTION INPUT ;
    USE SIGNAL ;
    SHAPE ABUTMENT ;
    PORT
      LAYER metal4 ;
      RECT 906.090 376.845 906.300 376.915 ;
    END
  END w0_wd_in[195]
  PIN w0_wd_in[196]
    DIRECTION INPUT ;
    USE SIGNAL ;
    SHAPE ABUTMENT ;
    PORT
      LAYER metal4 ;
      RECT 906.090 382.445 906.300 382.515 ;
    END
  END w0_wd_in[196]
  PIN w0_wd_in[197]
    DIRECTION INPUT ;
    USE SIGNAL ;
    SHAPE ABUTMENT ;
    PORT
      LAYER metal4 ;
      RECT 906.090 388.045 906.300 388.115 ;
    END
  END w0_wd_in[197]
  PIN w0_wd_in[198]
    DIRECTION INPUT ;
    USE SIGNAL ;
    SHAPE ABUTMENT ;
    PORT
      LAYER metal4 ;
      RECT 906.090 393.645 906.300 393.715 ;
    END
  END w0_wd_in[198]
  PIN w0_wd_in[199]
    DIRECTION INPUT ;
    USE SIGNAL ;
    SHAPE ABUTMENT ;
    PORT
      LAYER metal4 ;
      RECT 906.090 399.245 906.300 399.315 ;
    END
  END w0_wd_in[199]
  PIN w0_wd_in[200]
    DIRECTION INPUT ;
    USE SIGNAL ;
    SHAPE ABUTMENT ;
    PORT
      LAYER metal4 ;
      RECT 906.090 404.845 906.300 404.915 ;
    END
  END w0_wd_in[200]
  PIN w0_wd_in[201]
    DIRECTION INPUT ;
    USE SIGNAL ;
    SHAPE ABUTMENT ;
    PORT
      LAYER metal4 ;
      RECT 906.090 410.445 906.300 410.515 ;
    END
  END w0_wd_in[201]
  PIN w0_wd_in[202]
    DIRECTION INPUT ;
    USE SIGNAL ;
    SHAPE ABUTMENT ;
    PORT
      LAYER metal4 ;
      RECT 906.090 416.045 906.300 416.115 ;
    END
  END w0_wd_in[202]
  PIN w0_wd_in[203]
    DIRECTION INPUT ;
    USE SIGNAL ;
    SHAPE ABUTMENT ;
    PORT
      LAYER metal4 ;
      RECT 906.090 421.645 906.300 421.715 ;
    END
  END w0_wd_in[203]
  PIN w0_wd_in[204]
    DIRECTION INPUT ;
    USE SIGNAL ;
    SHAPE ABUTMENT ;
    PORT
      LAYER metal4 ;
      RECT 906.090 427.245 906.300 427.315 ;
    END
  END w0_wd_in[204]
  PIN w0_wd_in[205]
    DIRECTION INPUT ;
    USE SIGNAL ;
    SHAPE ABUTMENT ;
    PORT
      LAYER metal4 ;
      RECT 906.090 432.845 906.300 432.915 ;
    END
  END w0_wd_in[205]
  PIN w0_wd_in[206]
    DIRECTION INPUT ;
    USE SIGNAL ;
    SHAPE ABUTMENT ;
    PORT
      LAYER metal4 ;
      RECT 906.090 438.445 906.300 438.515 ;
    END
  END w0_wd_in[206]
  PIN w0_wd_in[207]
    DIRECTION INPUT ;
    USE SIGNAL ;
    SHAPE ABUTMENT ;
    PORT
      LAYER metal4 ;
      RECT 906.090 444.045 906.300 444.115 ;
    END
  END w0_wd_in[207]
  PIN w0_wd_in[208]
    DIRECTION INPUT ;
    USE SIGNAL ;
    SHAPE ABUTMENT ;
    PORT
      LAYER metal4 ;
      RECT 906.090 449.645 906.300 449.715 ;
    END
  END w0_wd_in[208]
  PIN w0_wd_in[209]
    DIRECTION INPUT ;
    USE SIGNAL ;
    SHAPE ABUTMENT ;
    PORT
      LAYER metal4 ;
      RECT 906.090 455.245 906.300 455.315 ;
    END
  END w0_wd_in[209]
  PIN w0_wd_in[210]
    DIRECTION INPUT ;
    USE SIGNAL ;
    SHAPE ABUTMENT ;
    PORT
      LAYER metal4 ;
      RECT 906.090 460.845 906.300 460.915 ;
    END
  END w0_wd_in[210]
  PIN w0_wd_in[211]
    DIRECTION INPUT ;
    USE SIGNAL ;
    SHAPE ABUTMENT ;
    PORT
      LAYER metal4 ;
      RECT 906.090 466.445 906.300 466.515 ;
    END
  END w0_wd_in[211]
  PIN w0_wd_in[212]
    DIRECTION INPUT ;
    USE SIGNAL ;
    SHAPE ABUTMENT ;
    PORT
      LAYER metal4 ;
      RECT 906.090 472.045 906.300 472.115 ;
    END
  END w0_wd_in[212]
  PIN w0_wd_in[213]
    DIRECTION INPUT ;
    USE SIGNAL ;
    SHAPE ABUTMENT ;
    PORT
      LAYER metal4 ;
      RECT 906.090 477.645 906.300 477.715 ;
    END
  END w0_wd_in[213]
  PIN w0_wd_in[214]
    DIRECTION INPUT ;
    USE SIGNAL ;
    SHAPE ABUTMENT ;
    PORT
      LAYER metal4 ;
      RECT 906.090 483.245 906.300 483.315 ;
    END
  END w0_wd_in[214]
  PIN w0_wd_in[215]
    DIRECTION INPUT ;
    USE SIGNAL ;
    SHAPE ABUTMENT ;
    PORT
      LAYER metal4 ;
      RECT 906.090 488.845 906.300 488.915 ;
    END
  END w0_wd_in[215]
  PIN w0_wd_in[216]
    DIRECTION INPUT ;
    USE SIGNAL ;
    SHAPE ABUTMENT ;
    PORT
      LAYER metal4 ;
      RECT 906.090 494.445 906.300 494.515 ;
    END
  END w0_wd_in[216]
  PIN w0_wd_in[217]
    DIRECTION INPUT ;
    USE SIGNAL ;
    SHAPE ABUTMENT ;
    PORT
      LAYER metal4 ;
      RECT 906.090 500.045 906.300 500.115 ;
    END
  END w0_wd_in[217]
  PIN w0_wd_in[218]
    DIRECTION INPUT ;
    USE SIGNAL ;
    SHAPE ABUTMENT ;
    PORT
      LAYER metal4 ;
      RECT 906.090 505.645 906.300 505.715 ;
    END
  END w0_wd_in[218]
  PIN w0_wd_in[219]
    DIRECTION INPUT ;
    USE SIGNAL ;
    SHAPE ABUTMENT ;
    PORT
      LAYER metal4 ;
      RECT 906.090 511.245 906.300 511.315 ;
    END
  END w0_wd_in[219]
  PIN w0_wd_in[220]
    DIRECTION INPUT ;
    USE SIGNAL ;
    SHAPE ABUTMENT ;
    PORT
      LAYER metal4 ;
      RECT 906.090 516.845 906.300 516.915 ;
    END
  END w0_wd_in[220]
  PIN w0_wd_in[221]
    DIRECTION INPUT ;
    USE SIGNAL ;
    SHAPE ABUTMENT ;
    PORT
      LAYER metal4 ;
      RECT 906.090 522.445 906.300 522.515 ;
    END
  END w0_wd_in[221]
  PIN w0_wd_in[222]
    DIRECTION INPUT ;
    USE SIGNAL ;
    SHAPE ABUTMENT ;
    PORT
      LAYER metal4 ;
      RECT 906.090 528.045 906.300 528.115 ;
    END
  END w0_wd_in[222]
  PIN w0_wd_in[223]
    DIRECTION INPUT ;
    USE SIGNAL ;
    SHAPE ABUTMENT ;
    PORT
      LAYER metal4 ;
      RECT 906.090 533.645 906.300 533.715 ;
    END
  END w0_wd_in[223]
  PIN w0_wd_in[224]
    DIRECTION INPUT ;
    USE SIGNAL ;
    SHAPE ABUTMENT ;
    PORT
      LAYER metal4 ;
      RECT 906.090 539.245 906.300 539.315 ;
    END
  END w0_wd_in[224]
  PIN w0_wd_in[225]
    DIRECTION INPUT ;
    USE SIGNAL ;
    SHAPE ABUTMENT ;
    PORT
      LAYER metal4 ;
      RECT 906.090 544.845 906.300 544.915 ;
    END
  END w0_wd_in[225]
  PIN w0_wd_in[226]
    DIRECTION INPUT ;
    USE SIGNAL ;
    SHAPE ABUTMENT ;
    PORT
      LAYER metal4 ;
      RECT 906.090 550.445 906.300 550.515 ;
    END
  END w0_wd_in[226]
  PIN w0_wd_in[227]
    DIRECTION INPUT ;
    USE SIGNAL ;
    SHAPE ABUTMENT ;
    PORT
      LAYER metal4 ;
      RECT 906.090 556.045 906.300 556.115 ;
    END
  END w0_wd_in[227]
  PIN w0_wd_in[228]
    DIRECTION INPUT ;
    USE SIGNAL ;
    SHAPE ABUTMENT ;
    PORT
      LAYER metal4 ;
      RECT 906.090 561.645 906.300 561.715 ;
    END
  END w0_wd_in[228]
  PIN w0_wd_in[229]
    DIRECTION INPUT ;
    USE SIGNAL ;
    SHAPE ABUTMENT ;
    PORT
      LAYER metal4 ;
      RECT 906.090 567.245 906.300 567.315 ;
    END
  END w0_wd_in[229]
  PIN w0_wd_in[230]
    DIRECTION INPUT ;
    USE SIGNAL ;
    SHAPE ABUTMENT ;
    PORT
      LAYER metal4 ;
      RECT 906.090 572.845 906.300 572.915 ;
    END
  END w0_wd_in[230]
  PIN w0_wd_in[231]
    DIRECTION INPUT ;
    USE SIGNAL ;
    SHAPE ABUTMENT ;
    PORT
      LAYER metal4 ;
      RECT 906.090 578.445 906.300 578.515 ;
    END
  END w0_wd_in[231]
  PIN w0_wd_in[232]
    DIRECTION INPUT ;
    USE SIGNAL ;
    SHAPE ABUTMENT ;
    PORT
      LAYER metal4 ;
      RECT 906.090 584.045 906.300 584.115 ;
    END
  END w0_wd_in[232]
  PIN w0_wd_in[233]
    DIRECTION INPUT ;
    USE SIGNAL ;
    SHAPE ABUTMENT ;
    PORT
      LAYER metal4 ;
      RECT 906.090 589.645 906.300 589.715 ;
    END
  END w0_wd_in[233]
  PIN w0_wd_in[234]
    DIRECTION INPUT ;
    USE SIGNAL ;
    SHAPE ABUTMENT ;
    PORT
      LAYER metal4 ;
      RECT 906.090 595.245 906.300 595.315 ;
    END
  END w0_wd_in[234]
  PIN w0_wd_in[235]
    DIRECTION INPUT ;
    USE SIGNAL ;
    SHAPE ABUTMENT ;
    PORT
      LAYER metal4 ;
      RECT 906.090 600.845 906.300 600.915 ;
    END
  END w0_wd_in[235]
  PIN w0_wd_in[236]
    DIRECTION INPUT ;
    USE SIGNAL ;
    SHAPE ABUTMENT ;
    PORT
      LAYER metal4 ;
      RECT 906.090 606.445 906.300 606.515 ;
    END
  END w0_wd_in[236]
  PIN w0_wd_in[237]
    DIRECTION INPUT ;
    USE SIGNAL ;
    SHAPE ABUTMENT ;
    PORT
      LAYER metal4 ;
      RECT 906.090 612.045 906.300 612.115 ;
    END
  END w0_wd_in[237]
  PIN w0_wd_in[238]
    DIRECTION INPUT ;
    USE SIGNAL ;
    SHAPE ABUTMENT ;
    PORT
      LAYER metal4 ;
      RECT 906.090 617.645 906.300 617.715 ;
    END
  END w0_wd_in[238]
  PIN w0_wd_in[239]
    DIRECTION INPUT ;
    USE SIGNAL ;
    SHAPE ABUTMENT ;
    PORT
      LAYER metal4 ;
      RECT 906.090 623.245 906.300 623.315 ;
    END
  END w0_wd_in[239]
  PIN w0_wd_in[240]
    DIRECTION INPUT ;
    USE SIGNAL ;
    SHAPE ABUTMENT ;
    PORT
      LAYER metal4 ;
      RECT 906.090 628.845 906.300 628.915 ;
    END
  END w0_wd_in[240]
  PIN w0_wd_in[241]
    DIRECTION INPUT ;
    USE SIGNAL ;
    SHAPE ABUTMENT ;
    PORT
      LAYER metal4 ;
      RECT 906.090 634.445 906.300 634.515 ;
    END
  END w0_wd_in[241]
  PIN w0_wd_in[242]
    DIRECTION INPUT ;
    USE SIGNAL ;
    SHAPE ABUTMENT ;
    PORT
      LAYER metal4 ;
      RECT 906.090 640.045 906.300 640.115 ;
    END
  END w0_wd_in[242]
  PIN w0_wd_in[243]
    DIRECTION INPUT ;
    USE SIGNAL ;
    SHAPE ABUTMENT ;
    PORT
      LAYER metal4 ;
      RECT 906.090 645.645 906.300 645.715 ;
    END
  END w0_wd_in[243]
  PIN w0_wd_in[244]
    DIRECTION INPUT ;
    USE SIGNAL ;
    SHAPE ABUTMENT ;
    PORT
      LAYER metal4 ;
      RECT 906.090 651.245 906.300 651.315 ;
    END
  END w0_wd_in[244]
  PIN w0_wd_in[245]
    DIRECTION INPUT ;
    USE SIGNAL ;
    SHAPE ABUTMENT ;
    PORT
      LAYER metal4 ;
      RECT 906.090 656.845 906.300 656.915 ;
    END
  END w0_wd_in[245]
  PIN w0_wd_in[246]
    DIRECTION INPUT ;
    USE SIGNAL ;
    SHAPE ABUTMENT ;
    PORT
      LAYER metal4 ;
      RECT 906.090 662.445 906.300 662.515 ;
    END
  END w0_wd_in[246]
  PIN w0_wd_in[247]
    DIRECTION INPUT ;
    USE SIGNAL ;
    SHAPE ABUTMENT ;
    PORT
      LAYER metal4 ;
      RECT 906.090 668.045 906.300 668.115 ;
    END
  END w0_wd_in[247]
  PIN w0_wd_in[248]
    DIRECTION INPUT ;
    USE SIGNAL ;
    SHAPE ABUTMENT ;
    PORT
      LAYER metal4 ;
      RECT 906.090 673.645 906.300 673.715 ;
    END
  END w0_wd_in[248]
  PIN w0_wd_in[249]
    DIRECTION INPUT ;
    USE SIGNAL ;
    SHAPE ABUTMENT ;
    PORT
      LAYER metal4 ;
      RECT 906.090 679.245 906.300 679.315 ;
    END
  END w0_wd_in[249]
  PIN w0_wd_in[250]
    DIRECTION INPUT ;
    USE SIGNAL ;
    SHAPE ABUTMENT ;
    PORT
      LAYER metal4 ;
      RECT 906.090 684.845 906.300 684.915 ;
    END
  END w0_wd_in[250]
  PIN w0_wd_in[251]
    DIRECTION INPUT ;
    USE SIGNAL ;
    SHAPE ABUTMENT ;
    PORT
      LAYER metal4 ;
      RECT 906.090 690.445 906.300 690.515 ;
    END
  END w0_wd_in[251]
  PIN w0_wd_in[252]
    DIRECTION INPUT ;
    USE SIGNAL ;
    SHAPE ABUTMENT ;
    PORT
      LAYER metal4 ;
      RECT 906.090 696.045 906.300 696.115 ;
    END
  END w0_wd_in[252]
  PIN w0_wd_in[253]
    DIRECTION INPUT ;
    USE SIGNAL ;
    SHAPE ABUTMENT ;
    PORT
      LAYER metal4 ;
      RECT 906.090 701.645 906.300 701.715 ;
    END
  END w0_wd_in[253]
  PIN w0_wd_in[254]
    DIRECTION INPUT ;
    USE SIGNAL ;
    SHAPE ABUTMENT ;
    PORT
      LAYER metal4 ;
      RECT 906.090 707.245 906.300 707.315 ;
    END
  END w0_wd_in[254]
  PIN w0_wd_in[255]
    DIRECTION INPUT ;
    USE SIGNAL ;
    SHAPE ABUTMENT ;
    PORT
      LAYER metal4 ;
      RECT 906.090 712.845 906.300 712.915 ;
    END
  END w0_wd_in[255]
  PIN w0_wd_in[256]
    DIRECTION OUTPUT ;
    USE SIGNAL ;
    SHAPE ABUTMENT ;
    PORT
      LAYER metal3 ;
      RECT 0.805 0.000 0.875 0.210 ;
    END
  END w0_wd_in[256]
  PIN w0_wd_in[257]
    DIRECTION OUTPUT ;
    USE SIGNAL ;
    SHAPE ABUTMENT ;
    PORT
      LAYER metal3 ;
      RECT 2.485 0.000 2.555 0.210 ;
    END
  END w0_wd_in[257]
  PIN w0_wd_in[258]
    DIRECTION OUTPUT ;
    USE SIGNAL ;
    SHAPE ABUTMENT ;
    PORT
      LAYER metal3 ;
      RECT 4.165 0.000 4.235 0.210 ;
    END
  END w0_wd_in[258]
  PIN w0_wd_in[259]
    DIRECTION OUTPUT ;
    USE SIGNAL ;
    SHAPE ABUTMENT ;
    PORT
      LAYER metal3 ;
      RECT 5.845 0.000 5.915 0.210 ;
    END
  END w0_wd_in[259]
  PIN w0_wd_in[260]
    DIRECTION OUTPUT ;
    USE SIGNAL ;
    SHAPE ABUTMENT ;
    PORT
      LAYER metal3 ;
      RECT 7.525 0.000 7.595 0.210 ;
    END
  END w0_wd_in[260]
  PIN w0_wd_in[261]
    DIRECTION OUTPUT ;
    USE SIGNAL ;
    SHAPE ABUTMENT ;
    PORT
      LAYER metal3 ;
      RECT 9.205 0.000 9.275 0.210 ;
    END
  END w0_wd_in[261]
  PIN w0_wd_in[262]
    DIRECTION OUTPUT ;
    USE SIGNAL ;
    SHAPE ABUTMENT ;
    PORT
      LAYER metal3 ;
      RECT 10.885 0.000 10.955 0.210 ;
    END
  END w0_wd_in[262]
  PIN w0_wd_in[263]
    DIRECTION OUTPUT ;
    USE SIGNAL ;
    SHAPE ABUTMENT ;
    PORT
      LAYER metal3 ;
      RECT 12.565 0.000 12.635 0.210 ;
    END
  END w0_wd_in[263]
  PIN w0_wd_in[264]
    DIRECTION OUTPUT ;
    USE SIGNAL ;
    SHAPE ABUTMENT ;
    PORT
      LAYER metal3 ;
      RECT 14.245 0.000 14.315 0.210 ;
    END
  END w0_wd_in[264]
  PIN w0_wd_in[265]
    DIRECTION OUTPUT ;
    USE SIGNAL ;
    SHAPE ABUTMENT ;
    PORT
      LAYER metal3 ;
      RECT 15.925 0.000 15.995 0.210 ;
    END
  END w0_wd_in[265]
  PIN w0_wd_in[266]
    DIRECTION OUTPUT ;
    USE SIGNAL ;
    SHAPE ABUTMENT ;
    PORT
      LAYER metal3 ;
      RECT 17.605 0.000 17.675 0.210 ;
    END
  END w0_wd_in[266]
  PIN w0_wd_in[267]
    DIRECTION OUTPUT ;
    USE SIGNAL ;
    SHAPE ABUTMENT ;
    PORT
      LAYER metal3 ;
      RECT 19.285 0.000 19.355 0.210 ;
    END
  END w0_wd_in[267]
  PIN w0_wd_in[268]
    DIRECTION OUTPUT ;
    USE SIGNAL ;
    SHAPE ABUTMENT ;
    PORT
      LAYER metal3 ;
      RECT 20.965 0.000 21.035 0.210 ;
    END
  END w0_wd_in[268]
  PIN w0_wd_in[269]
    DIRECTION OUTPUT ;
    USE SIGNAL ;
    SHAPE ABUTMENT ;
    PORT
      LAYER metal3 ;
      RECT 22.645 0.000 22.715 0.210 ;
    END
  END w0_wd_in[269]
  PIN w0_wd_in[270]
    DIRECTION OUTPUT ;
    USE SIGNAL ;
    SHAPE ABUTMENT ;
    PORT
      LAYER metal3 ;
      RECT 24.325 0.000 24.395 0.210 ;
    END
  END w0_wd_in[270]
  PIN w0_wd_in[271]
    DIRECTION OUTPUT ;
    USE SIGNAL ;
    SHAPE ABUTMENT ;
    PORT
      LAYER metal3 ;
      RECT 26.005 0.000 26.075 0.210 ;
    END
  END w0_wd_in[271]
  PIN w0_wd_in[272]
    DIRECTION OUTPUT ;
    USE SIGNAL ;
    SHAPE ABUTMENT ;
    PORT
      LAYER metal3 ;
      RECT 27.685 0.000 27.755 0.210 ;
    END
  END w0_wd_in[272]
  PIN w0_wd_in[273]
    DIRECTION OUTPUT ;
    USE SIGNAL ;
    SHAPE ABUTMENT ;
    PORT
      LAYER metal3 ;
      RECT 29.365 0.000 29.435 0.210 ;
    END
  END w0_wd_in[273]
  PIN w0_wd_in[274]
    DIRECTION OUTPUT ;
    USE SIGNAL ;
    SHAPE ABUTMENT ;
    PORT
      LAYER metal3 ;
      RECT 31.045 0.000 31.115 0.210 ;
    END
  END w0_wd_in[274]
  PIN w0_wd_in[275]
    DIRECTION OUTPUT ;
    USE SIGNAL ;
    SHAPE ABUTMENT ;
    PORT
      LAYER metal3 ;
      RECT 32.725 0.000 32.795 0.210 ;
    END
  END w0_wd_in[275]
  PIN w0_wd_in[276]
    DIRECTION OUTPUT ;
    USE SIGNAL ;
    SHAPE ABUTMENT ;
    PORT
      LAYER metal3 ;
      RECT 34.405 0.000 34.475 0.210 ;
    END
  END w0_wd_in[276]
  PIN w0_wd_in[277]
    DIRECTION OUTPUT ;
    USE SIGNAL ;
    SHAPE ABUTMENT ;
    PORT
      LAYER metal3 ;
      RECT 36.085 0.000 36.155 0.210 ;
    END
  END w0_wd_in[277]
  PIN w0_wd_in[278]
    DIRECTION OUTPUT ;
    USE SIGNAL ;
    SHAPE ABUTMENT ;
    PORT
      LAYER metal3 ;
      RECT 37.765 0.000 37.835 0.210 ;
    END
  END w0_wd_in[278]
  PIN w0_wd_in[279]
    DIRECTION OUTPUT ;
    USE SIGNAL ;
    SHAPE ABUTMENT ;
    PORT
      LAYER metal3 ;
      RECT 39.445 0.000 39.515 0.210 ;
    END
  END w0_wd_in[279]
  PIN w0_wd_in[280]
    DIRECTION OUTPUT ;
    USE SIGNAL ;
    SHAPE ABUTMENT ;
    PORT
      LAYER metal3 ;
      RECT 41.125 0.000 41.195 0.210 ;
    END
  END w0_wd_in[280]
  PIN w0_wd_in[281]
    DIRECTION OUTPUT ;
    USE SIGNAL ;
    SHAPE ABUTMENT ;
    PORT
      LAYER metal3 ;
      RECT 42.805 0.000 42.875 0.210 ;
    END
  END w0_wd_in[281]
  PIN w0_wd_in[282]
    DIRECTION OUTPUT ;
    USE SIGNAL ;
    SHAPE ABUTMENT ;
    PORT
      LAYER metal3 ;
      RECT 44.485 0.000 44.555 0.210 ;
    END
  END w0_wd_in[282]
  PIN w0_wd_in[283]
    DIRECTION OUTPUT ;
    USE SIGNAL ;
    SHAPE ABUTMENT ;
    PORT
      LAYER metal3 ;
      RECT 46.165 0.000 46.235 0.210 ;
    END
  END w0_wd_in[283]
  PIN w0_wd_in[284]
    DIRECTION OUTPUT ;
    USE SIGNAL ;
    SHAPE ABUTMENT ;
    PORT
      LAYER metal3 ;
      RECT 47.845 0.000 47.915 0.210 ;
    END
  END w0_wd_in[284]
  PIN w0_wd_in[285]
    DIRECTION OUTPUT ;
    USE SIGNAL ;
    SHAPE ABUTMENT ;
    PORT
      LAYER metal3 ;
      RECT 49.525 0.000 49.595 0.210 ;
    END
  END w0_wd_in[285]
  PIN w0_wd_in[286]
    DIRECTION OUTPUT ;
    USE SIGNAL ;
    SHAPE ABUTMENT ;
    PORT
      LAYER metal3 ;
      RECT 51.205 0.000 51.275 0.210 ;
    END
  END w0_wd_in[286]
  PIN w0_wd_in[287]
    DIRECTION OUTPUT ;
    USE SIGNAL ;
    SHAPE ABUTMENT ;
    PORT
      LAYER metal3 ;
      RECT 52.885 0.000 52.955 0.210 ;
    END
  END w0_wd_in[287]
  PIN w0_wd_in[288]
    DIRECTION OUTPUT ;
    USE SIGNAL ;
    SHAPE ABUTMENT ;
    PORT
      LAYER metal3 ;
      RECT 54.565 0.000 54.635 0.210 ;
    END
  END w0_wd_in[288]
  PIN w0_wd_in[289]
    DIRECTION OUTPUT ;
    USE SIGNAL ;
    SHAPE ABUTMENT ;
    PORT
      LAYER metal3 ;
      RECT 56.245 0.000 56.315 0.210 ;
    END
  END w0_wd_in[289]
  PIN w0_wd_in[290]
    DIRECTION OUTPUT ;
    USE SIGNAL ;
    SHAPE ABUTMENT ;
    PORT
      LAYER metal3 ;
      RECT 57.925 0.000 57.995 0.210 ;
    END
  END w0_wd_in[290]
  PIN w0_wd_in[291]
    DIRECTION OUTPUT ;
    USE SIGNAL ;
    SHAPE ABUTMENT ;
    PORT
      LAYER metal3 ;
      RECT 59.605 0.000 59.675 0.210 ;
    END
  END w0_wd_in[291]
  PIN w0_wd_in[292]
    DIRECTION OUTPUT ;
    USE SIGNAL ;
    SHAPE ABUTMENT ;
    PORT
      LAYER metal3 ;
      RECT 61.285 0.000 61.355 0.210 ;
    END
  END w0_wd_in[292]
  PIN w0_wd_in[293]
    DIRECTION OUTPUT ;
    USE SIGNAL ;
    SHAPE ABUTMENT ;
    PORT
      LAYER metal3 ;
      RECT 62.965 0.000 63.035 0.210 ;
    END
  END w0_wd_in[293]
  PIN w0_wd_in[294]
    DIRECTION OUTPUT ;
    USE SIGNAL ;
    SHAPE ABUTMENT ;
    PORT
      LAYER metal3 ;
      RECT 64.645 0.000 64.715 0.210 ;
    END
  END w0_wd_in[294]
  PIN w0_wd_in[295]
    DIRECTION OUTPUT ;
    USE SIGNAL ;
    SHAPE ABUTMENT ;
    PORT
      LAYER metal3 ;
      RECT 66.325 0.000 66.395 0.210 ;
    END
  END w0_wd_in[295]
  PIN w0_wd_in[296]
    DIRECTION OUTPUT ;
    USE SIGNAL ;
    SHAPE ABUTMENT ;
    PORT
      LAYER metal3 ;
      RECT 68.005 0.000 68.075 0.210 ;
    END
  END w0_wd_in[296]
  PIN w0_wd_in[297]
    DIRECTION OUTPUT ;
    USE SIGNAL ;
    SHAPE ABUTMENT ;
    PORT
      LAYER metal3 ;
      RECT 69.685 0.000 69.755 0.210 ;
    END
  END w0_wd_in[297]
  PIN w0_wd_in[298]
    DIRECTION OUTPUT ;
    USE SIGNAL ;
    SHAPE ABUTMENT ;
    PORT
      LAYER metal3 ;
      RECT 71.365 0.000 71.435 0.210 ;
    END
  END w0_wd_in[298]
  PIN w0_wd_in[299]
    DIRECTION OUTPUT ;
    USE SIGNAL ;
    SHAPE ABUTMENT ;
    PORT
      LAYER metal3 ;
      RECT 73.045 0.000 73.115 0.210 ;
    END
  END w0_wd_in[299]
  PIN w0_wd_in[300]
    DIRECTION OUTPUT ;
    USE SIGNAL ;
    SHAPE ABUTMENT ;
    PORT
      LAYER metal3 ;
      RECT 74.725 0.000 74.795 0.210 ;
    END
  END w0_wd_in[300]
  PIN w0_wd_in[301]
    DIRECTION OUTPUT ;
    USE SIGNAL ;
    SHAPE ABUTMENT ;
    PORT
      LAYER metal3 ;
      RECT 76.405 0.000 76.475 0.210 ;
    END
  END w0_wd_in[301]
  PIN w0_wd_in[302]
    DIRECTION OUTPUT ;
    USE SIGNAL ;
    SHAPE ABUTMENT ;
    PORT
      LAYER metal3 ;
      RECT 78.085 0.000 78.155 0.210 ;
    END
  END w0_wd_in[302]
  PIN w0_wd_in[303]
    DIRECTION OUTPUT ;
    USE SIGNAL ;
    SHAPE ABUTMENT ;
    PORT
      LAYER metal3 ;
      RECT 79.765 0.000 79.835 0.210 ;
    END
  END w0_wd_in[303]
  PIN w0_wd_in[304]
    DIRECTION OUTPUT ;
    USE SIGNAL ;
    SHAPE ABUTMENT ;
    PORT
      LAYER metal3 ;
      RECT 81.445 0.000 81.515 0.210 ;
    END
  END w0_wd_in[304]
  PIN w0_wd_in[305]
    DIRECTION OUTPUT ;
    USE SIGNAL ;
    SHAPE ABUTMENT ;
    PORT
      LAYER metal3 ;
      RECT 83.125 0.000 83.195 0.210 ;
    END
  END w0_wd_in[305]
  PIN w0_wd_in[306]
    DIRECTION OUTPUT ;
    USE SIGNAL ;
    SHAPE ABUTMENT ;
    PORT
      LAYER metal3 ;
      RECT 84.805 0.000 84.875 0.210 ;
    END
  END w0_wd_in[306]
  PIN w0_wd_in[307]
    DIRECTION OUTPUT ;
    USE SIGNAL ;
    SHAPE ABUTMENT ;
    PORT
      LAYER metal3 ;
      RECT 86.485 0.000 86.555 0.210 ;
    END
  END w0_wd_in[307]
  PIN w0_wd_in[308]
    DIRECTION OUTPUT ;
    USE SIGNAL ;
    SHAPE ABUTMENT ;
    PORT
      LAYER metal3 ;
      RECT 88.165 0.000 88.235 0.210 ;
    END
  END w0_wd_in[308]
  PIN w0_wd_in[309]
    DIRECTION OUTPUT ;
    USE SIGNAL ;
    SHAPE ABUTMENT ;
    PORT
      LAYER metal3 ;
      RECT 89.845 0.000 89.915 0.210 ;
    END
  END w0_wd_in[309]
  PIN w0_wd_in[310]
    DIRECTION OUTPUT ;
    USE SIGNAL ;
    SHAPE ABUTMENT ;
    PORT
      LAYER metal3 ;
      RECT 91.525 0.000 91.595 0.210 ;
    END
  END w0_wd_in[310]
  PIN w0_wd_in[311]
    DIRECTION OUTPUT ;
    USE SIGNAL ;
    SHAPE ABUTMENT ;
    PORT
      LAYER metal3 ;
      RECT 93.205 0.000 93.275 0.210 ;
    END
  END w0_wd_in[311]
  PIN w0_wd_in[312]
    DIRECTION OUTPUT ;
    USE SIGNAL ;
    SHAPE ABUTMENT ;
    PORT
      LAYER metal3 ;
      RECT 94.885 0.000 94.955 0.210 ;
    END
  END w0_wd_in[312]
  PIN w0_wd_in[313]
    DIRECTION OUTPUT ;
    USE SIGNAL ;
    SHAPE ABUTMENT ;
    PORT
      LAYER metal3 ;
      RECT 96.565 0.000 96.635 0.210 ;
    END
  END w0_wd_in[313]
  PIN w0_wd_in[314]
    DIRECTION OUTPUT ;
    USE SIGNAL ;
    SHAPE ABUTMENT ;
    PORT
      LAYER metal3 ;
      RECT 98.245 0.000 98.315 0.210 ;
    END
  END w0_wd_in[314]
  PIN w0_wd_in[315]
    DIRECTION OUTPUT ;
    USE SIGNAL ;
    SHAPE ABUTMENT ;
    PORT
      LAYER metal3 ;
      RECT 99.925 0.000 99.995 0.210 ;
    END
  END w0_wd_in[315]
  PIN w0_wd_in[316]
    DIRECTION OUTPUT ;
    USE SIGNAL ;
    SHAPE ABUTMENT ;
    PORT
      LAYER metal3 ;
      RECT 101.605 0.000 101.675 0.210 ;
    END
  END w0_wd_in[316]
  PIN w0_wd_in[317]
    DIRECTION OUTPUT ;
    USE SIGNAL ;
    SHAPE ABUTMENT ;
    PORT
      LAYER metal3 ;
      RECT 103.285 0.000 103.355 0.210 ;
    END
  END w0_wd_in[317]
  PIN w0_wd_in[318]
    DIRECTION OUTPUT ;
    USE SIGNAL ;
    SHAPE ABUTMENT ;
    PORT
      LAYER metal3 ;
      RECT 104.965 0.000 105.035 0.210 ;
    END
  END w0_wd_in[318]
  PIN w0_wd_in[319]
    DIRECTION OUTPUT ;
    USE SIGNAL ;
    SHAPE ABUTMENT ;
    PORT
      LAYER metal3 ;
      RECT 106.645 0.000 106.715 0.210 ;
    END
  END w0_wd_in[319]
  PIN w0_wd_in[320]
    DIRECTION OUTPUT ;
    USE SIGNAL ;
    SHAPE ABUTMENT ;
    PORT
      LAYER metal3 ;
      RECT 108.325 0.000 108.395 0.210 ;
    END
  END w0_wd_in[320]
  PIN w0_wd_in[321]
    DIRECTION OUTPUT ;
    USE SIGNAL ;
    SHAPE ABUTMENT ;
    PORT
      LAYER metal3 ;
      RECT 110.005 0.000 110.075 0.210 ;
    END
  END w0_wd_in[321]
  PIN w0_wd_in[322]
    DIRECTION OUTPUT ;
    USE SIGNAL ;
    SHAPE ABUTMENT ;
    PORT
      LAYER metal3 ;
      RECT 111.685 0.000 111.755 0.210 ;
    END
  END w0_wd_in[322]
  PIN w0_wd_in[323]
    DIRECTION OUTPUT ;
    USE SIGNAL ;
    SHAPE ABUTMENT ;
    PORT
      LAYER metal3 ;
      RECT 113.365 0.000 113.435 0.210 ;
    END
  END w0_wd_in[323]
  PIN w0_wd_in[324]
    DIRECTION OUTPUT ;
    USE SIGNAL ;
    SHAPE ABUTMENT ;
    PORT
      LAYER metal3 ;
      RECT 115.045 0.000 115.115 0.210 ;
    END
  END w0_wd_in[324]
  PIN w0_wd_in[325]
    DIRECTION OUTPUT ;
    USE SIGNAL ;
    SHAPE ABUTMENT ;
    PORT
      LAYER metal3 ;
      RECT 116.725 0.000 116.795 0.210 ;
    END
  END w0_wd_in[325]
  PIN w0_wd_in[326]
    DIRECTION OUTPUT ;
    USE SIGNAL ;
    SHAPE ABUTMENT ;
    PORT
      LAYER metal3 ;
      RECT 118.405 0.000 118.475 0.210 ;
    END
  END w0_wd_in[326]
  PIN w0_wd_in[327]
    DIRECTION OUTPUT ;
    USE SIGNAL ;
    SHAPE ABUTMENT ;
    PORT
      LAYER metal3 ;
      RECT 120.085 0.000 120.155 0.210 ;
    END
  END w0_wd_in[327]
  PIN w0_wd_in[328]
    DIRECTION OUTPUT ;
    USE SIGNAL ;
    SHAPE ABUTMENT ;
    PORT
      LAYER metal3 ;
      RECT 121.765 0.000 121.835 0.210 ;
    END
  END w0_wd_in[328]
  PIN w0_wd_in[329]
    DIRECTION OUTPUT ;
    USE SIGNAL ;
    SHAPE ABUTMENT ;
    PORT
      LAYER metal3 ;
      RECT 123.445 0.000 123.515 0.210 ;
    END
  END w0_wd_in[329]
  PIN w0_wd_in[330]
    DIRECTION OUTPUT ;
    USE SIGNAL ;
    SHAPE ABUTMENT ;
    PORT
      LAYER metal3 ;
      RECT 125.125 0.000 125.195 0.210 ;
    END
  END w0_wd_in[330]
  PIN w0_wd_in[331]
    DIRECTION OUTPUT ;
    USE SIGNAL ;
    SHAPE ABUTMENT ;
    PORT
      LAYER metal3 ;
      RECT 126.805 0.000 126.875 0.210 ;
    END
  END w0_wd_in[331]
  PIN w0_wd_in[332]
    DIRECTION OUTPUT ;
    USE SIGNAL ;
    SHAPE ABUTMENT ;
    PORT
      LAYER metal3 ;
      RECT 128.485 0.000 128.555 0.210 ;
    END
  END w0_wd_in[332]
  PIN w0_wd_in[333]
    DIRECTION OUTPUT ;
    USE SIGNAL ;
    SHAPE ABUTMENT ;
    PORT
      LAYER metal3 ;
      RECT 130.165 0.000 130.235 0.210 ;
    END
  END w0_wd_in[333]
  PIN w0_wd_in[334]
    DIRECTION OUTPUT ;
    USE SIGNAL ;
    SHAPE ABUTMENT ;
    PORT
      LAYER metal3 ;
      RECT 131.845 0.000 131.915 0.210 ;
    END
  END w0_wd_in[334]
  PIN w0_wd_in[335]
    DIRECTION OUTPUT ;
    USE SIGNAL ;
    SHAPE ABUTMENT ;
    PORT
      LAYER metal3 ;
      RECT 133.525 0.000 133.595 0.210 ;
    END
  END w0_wd_in[335]
  PIN w0_wd_in[336]
    DIRECTION OUTPUT ;
    USE SIGNAL ;
    SHAPE ABUTMENT ;
    PORT
      LAYER metal3 ;
      RECT 135.205 0.000 135.275 0.210 ;
    END
  END w0_wd_in[336]
  PIN w0_wd_in[337]
    DIRECTION OUTPUT ;
    USE SIGNAL ;
    SHAPE ABUTMENT ;
    PORT
      LAYER metal3 ;
      RECT 136.885 0.000 136.955 0.210 ;
    END
  END w0_wd_in[337]
  PIN w0_wd_in[338]
    DIRECTION OUTPUT ;
    USE SIGNAL ;
    SHAPE ABUTMENT ;
    PORT
      LAYER metal3 ;
      RECT 138.565 0.000 138.635 0.210 ;
    END
  END w0_wd_in[338]
  PIN w0_wd_in[339]
    DIRECTION OUTPUT ;
    USE SIGNAL ;
    SHAPE ABUTMENT ;
    PORT
      LAYER metal3 ;
      RECT 140.245 0.000 140.315 0.210 ;
    END
  END w0_wd_in[339]
  PIN w0_wd_in[340]
    DIRECTION OUTPUT ;
    USE SIGNAL ;
    SHAPE ABUTMENT ;
    PORT
      LAYER metal3 ;
      RECT 141.925 0.000 141.995 0.210 ;
    END
  END w0_wd_in[340]
  PIN w0_wd_in[341]
    DIRECTION OUTPUT ;
    USE SIGNAL ;
    SHAPE ABUTMENT ;
    PORT
      LAYER metal3 ;
      RECT 143.605 0.000 143.675 0.210 ;
    END
  END w0_wd_in[341]
  PIN w0_wd_in[342]
    DIRECTION OUTPUT ;
    USE SIGNAL ;
    SHAPE ABUTMENT ;
    PORT
      LAYER metal3 ;
      RECT 145.285 0.000 145.355 0.210 ;
    END
  END w0_wd_in[342]
  PIN w0_wd_in[343]
    DIRECTION OUTPUT ;
    USE SIGNAL ;
    SHAPE ABUTMENT ;
    PORT
      LAYER metal3 ;
      RECT 146.965 0.000 147.035 0.210 ;
    END
  END w0_wd_in[343]
  PIN w0_wd_in[344]
    DIRECTION OUTPUT ;
    USE SIGNAL ;
    SHAPE ABUTMENT ;
    PORT
      LAYER metal3 ;
      RECT 148.645 0.000 148.715 0.210 ;
    END
  END w0_wd_in[344]
  PIN w0_wd_in[345]
    DIRECTION OUTPUT ;
    USE SIGNAL ;
    SHAPE ABUTMENT ;
    PORT
      LAYER metal3 ;
      RECT 150.325 0.000 150.395 0.210 ;
    END
  END w0_wd_in[345]
  PIN w0_wd_in[346]
    DIRECTION OUTPUT ;
    USE SIGNAL ;
    SHAPE ABUTMENT ;
    PORT
      LAYER metal3 ;
      RECT 152.005 0.000 152.075 0.210 ;
    END
  END w0_wd_in[346]
  PIN w0_wd_in[347]
    DIRECTION OUTPUT ;
    USE SIGNAL ;
    SHAPE ABUTMENT ;
    PORT
      LAYER metal3 ;
      RECT 153.685 0.000 153.755 0.210 ;
    END
  END w0_wd_in[347]
  PIN w0_wd_in[348]
    DIRECTION OUTPUT ;
    USE SIGNAL ;
    SHAPE ABUTMENT ;
    PORT
      LAYER metal3 ;
      RECT 155.365 0.000 155.435 0.210 ;
    END
  END w0_wd_in[348]
  PIN w0_wd_in[349]
    DIRECTION OUTPUT ;
    USE SIGNAL ;
    SHAPE ABUTMENT ;
    PORT
      LAYER metal3 ;
      RECT 157.045 0.000 157.115 0.210 ;
    END
  END w0_wd_in[349]
  PIN w0_wd_in[350]
    DIRECTION OUTPUT ;
    USE SIGNAL ;
    SHAPE ABUTMENT ;
    PORT
      LAYER metal3 ;
      RECT 158.725 0.000 158.795 0.210 ;
    END
  END w0_wd_in[350]
  PIN w0_wd_in[351]
    DIRECTION OUTPUT ;
    USE SIGNAL ;
    SHAPE ABUTMENT ;
    PORT
      LAYER metal3 ;
      RECT 160.405 0.000 160.475 0.210 ;
    END
  END w0_wd_in[351]
  PIN w0_wd_in[352]
    DIRECTION OUTPUT ;
    USE SIGNAL ;
    SHAPE ABUTMENT ;
    PORT
      LAYER metal3 ;
      RECT 162.085 0.000 162.155 0.210 ;
    END
  END w0_wd_in[352]
  PIN w0_wd_in[353]
    DIRECTION OUTPUT ;
    USE SIGNAL ;
    SHAPE ABUTMENT ;
    PORT
      LAYER metal3 ;
      RECT 163.765 0.000 163.835 0.210 ;
    END
  END w0_wd_in[353]
  PIN w0_wd_in[354]
    DIRECTION OUTPUT ;
    USE SIGNAL ;
    SHAPE ABUTMENT ;
    PORT
      LAYER metal3 ;
      RECT 165.445 0.000 165.515 0.210 ;
    END
  END w0_wd_in[354]
  PIN w0_wd_in[355]
    DIRECTION OUTPUT ;
    USE SIGNAL ;
    SHAPE ABUTMENT ;
    PORT
      LAYER metal3 ;
      RECT 167.125 0.000 167.195 0.210 ;
    END
  END w0_wd_in[355]
  PIN w0_wd_in[356]
    DIRECTION OUTPUT ;
    USE SIGNAL ;
    SHAPE ABUTMENT ;
    PORT
      LAYER metal3 ;
      RECT 168.805 0.000 168.875 0.210 ;
    END
  END w0_wd_in[356]
  PIN w0_wd_in[357]
    DIRECTION OUTPUT ;
    USE SIGNAL ;
    SHAPE ABUTMENT ;
    PORT
      LAYER metal3 ;
      RECT 170.485 0.000 170.555 0.210 ;
    END
  END w0_wd_in[357]
  PIN w0_wd_in[358]
    DIRECTION OUTPUT ;
    USE SIGNAL ;
    SHAPE ABUTMENT ;
    PORT
      LAYER metal3 ;
      RECT 172.165 0.000 172.235 0.210 ;
    END
  END w0_wd_in[358]
  PIN w0_wd_in[359]
    DIRECTION OUTPUT ;
    USE SIGNAL ;
    SHAPE ABUTMENT ;
    PORT
      LAYER metal3 ;
      RECT 173.845 0.000 173.915 0.210 ;
    END
  END w0_wd_in[359]
  PIN w0_wd_in[360]
    DIRECTION OUTPUT ;
    USE SIGNAL ;
    SHAPE ABUTMENT ;
    PORT
      LAYER metal3 ;
      RECT 175.525 0.000 175.595 0.210 ;
    END
  END w0_wd_in[360]
  PIN w0_wd_in[361]
    DIRECTION OUTPUT ;
    USE SIGNAL ;
    SHAPE ABUTMENT ;
    PORT
      LAYER metal3 ;
      RECT 177.205 0.000 177.275 0.210 ;
    END
  END w0_wd_in[361]
  PIN w0_wd_in[362]
    DIRECTION OUTPUT ;
    USE SIGNAL ;
    SHAPE ABUTMENT ;
    PORT
      LAYER metal3 ;
      RECT 178.885 0.000 178.955 0.210 ;
    END
  END w0_wd_in[362]
  PIN w0_wd_in[363]
    DIRECTION OUTPUT ;
    USE SIGNAL ;
    SHAPE ABUTMENT ;
    PORT
      LAYER metal3 ;
      RECT 180.565 0.000 180.635 0.210 ;
    END
  END w0_wd_in[363]
  PIN w0_wd_in[364]
    DIRECTION OUTPUT ;
    USE SIGNAL ;
    SHAPE ABUTMENT ;
    PORT
      LAYER metal3 ;
      RECT 182.245 0.000 182.315 0.210 ;
    END
  END w0_wd_in[364]
  PIN w0_wd_in[365]
    DIRECTION OUTPUT ;
    USE SIGNAL ;
    SHAPE ABUTMENT ;
    PORT
      LAYER metal3 ;
      RECT 183.925 0.000 183.995 0.210 ;
    END
  END w0_wd_in[365]
  PIN w0_wd_in[366]
    DIRECTION OUTPUT ;
    USE SIGNAL ;
    SHAPE ABUTMENT ;
    PORT
      LAYER metal3 ;
      RECT 185.605 0.000 185.675 0.210 ;
    END
  END w0_wd_in[366]
  PIN w0_wd_in[367]
    DIRECTION OUTPUT ;
    USE SIGNAL ;
    SHAPE ABUTMENT ;
    PORT
      LAYER metal3 ;
      RECT 187.285 0.000 187.355 0.210 ;
    END
  END w0_wd_in[367]
  PIN w0_wd_in[368]
    DIRECTION OUTPUT ;
    USE SIGNAL ;
    SHAPE ABUTMENT ;
    PORT
      LAYER metal3 ;
      RECT 188.965 0.000 189.035 0.210 ;
    END
  END w0_wd_in[368]
  PIN w0_wd_in[369]
    DIRECTION OUTPUT ;
    USE SIGNAL ;
    SHAPE ABUTMENT ;
    PORT
      LAYER metal3 ;
      RECT 190.645 0.000 190.715 0.210 ;
    END
  END w0_wd_in[369]
  PIN w0_wd_in[370]
    DIRECTION OUTPUT ;
    USE SIGNAL ;
    SHAPE ABUTMENT ;
    PORT
      LAYER metal3 ;
      RECT 192.325 0.000 192.395 0.210 ;
    END
  END w0_wd_in[370]
  PIN w0_wd_in[371]
    DIRECTION OUTPUT ;
    USE SIGNAL ;
    SHAPE ABUTMENT ;
    PORT
      LAYER metal3 ;
      RECT 194.005 0.000 194.075 0.210 ;
    END
  END w0_wd_in[371]
  PIN w0_wd_in[372]
    DIRECTION OUTPUT ;
    USE SIGNAL ;
    SHAPE ABUTMENT ;
    PORT
      LAYER metal3 ;
      RECT 195.685 0.000 195.755 0.210 ;
    END
  END w0_wd_in[372]
  PIN w0_wd_in[373]
    DIRECTION OUTPUT ;
    USE SIGNAL ;
    SHAPE ABUTMENT ;
    PORT
      LAYER metal3 ;
      RECT 197.365 0.000 197.435 0.210 ;
    END
  END w0_wd_in[373]
  PIN w0_wd_in[374]
    DIRECTION OUTPUT ;
    USE SIGNAL ;
    SHAPE ABUTMENT ;
    PORT
      LAYER metal3 ;
      RECT 199.045 0.000 199.115 0.210 ;
    END
  END w0_wd_in[374]
  PIN w0_wd_in[375]
    DIRECTION OUTPUT ;
    USE SIGNAL ;
    SHAPE ABUTMENT ;
    PORT
      LAYER metal3 ;
      RECT 200.725 0.000 200.795 0.210 ;
    END
  END w0_wd_in[375]
  PIN w0_wd_in[376]
    DIRECTION OUTPUT ;
    USE SIGNAL ;
    SHAPE ABUTMENT ;
    PORT
      LAYER metal3 ;
      RECT 202.405 0.000 202.475 0.210 ;
    END
  END w0_wd_in[376]
  PIN w0_wd_in[377]
    DIRECTION OUTPUT ;
    USE SIGNAL ;
    SHAPE ABUTMENT ;
    PORT
      LAYER metal3 ;
      RECT 204.085 0.000 204.155 0.210 ;
    END
  END w0_wd_in[377]
  PIN w0_wd_in[378]
    DIRECTION OUTPUT ;
    USE SIGNAL ;
    SHAPE ABUTMENT ;
    PORT
      LAYER metal3 ;
      RECT 205.765 0.000 205.835 0.210 ;
    END
  END w0_wd_in[378]
  PIN w0_wd_in[379]
    DIRECTION OUTPUT ;
    USE SIGNAL ;
    SHAPE ABUTMENT ;
    PORT
      LAYER metal3 ;
      RECT 207.445 0.000 207.515 0.210 ;
    END
  END w0_wd_in[379]
  PIN w0_wd_in[380]
    DIRECTION OUTPUT ;
    USE SIGNAL ;
    SHAPE ABUTMENT ;
    PORT
      LAYER metal3 ;
      RECT 209.125 0.000 209.195 0.210 ;
    END
  END w0_wd_in[380]
  PIN w0_wd_in[381]
    DIRECTION OUTPUT ;
    USE SIGNAL ;
    SHAPE ABUTMENT ;
    PORT
      LAYER metal3 ;
      RECT 210.805 0.000 210.875 0.210 ;
    END
  END w0_wd_in[381]
  PIN w0_wd_in[382]
    DIRECTION OUTPUT ;
    USE SIGNAL ;
    SHAPE ABUTMENT ;
    PORT
      LAYER metal3 ;
      RECT 212.485 0.000 212.555 0.210 ;
    END
  END w0_wd_in[382]
  PIN w0_wd_in[383]
    DIRECTION OUTPUT ;
    USE SIGNAL ;
    SHAPE ABUTMENT ;
    PORT
      LAYER metal3 ;
      RECT 214.165 0.000 214.235 0.210 ;
    END
  END w0_wd_in[383]
  PIN w0_wd_in[384]
    DIRECTION OUTPUT ;
    USE SIGNAL ;
    SHAPE ABUTMENT ;
    PORT
      LAYER metal3 ;
      RECT 215.845 0.000 215.915 0.210 ;
    END
  END w0_wd_in[384]
  PIN w0_wd_in[385]
    DIRECTION OUTPUT ;
    USE SIGNAL ;
    SHAPE ABUTMENT ;
    PORT
      LAYER metal3 ;
      RECT 217.525 0.000 217.595 0.210 ;
    END
  END w0_wd_in[385]
  PIN w0_wd_in[386]
    DIRECTION OUTPUT ;
    USE SIGNAL ;
    SHAPE ABUTMENT ;
    PORT
      LAYER metal3 ;
      RECT 219.205 0.000 219.275 0.210 ;
    END
  END w0_wd_in[386]
  PIN w0_wd_in[387]
    DIRECTION OUTPUT ;
    USE SIGNAL ;
    SHAPE ABUTMENT ;
    PORT
      LAYER metal3 ;
      RECT 220.885 0.000 220.955 0.210 ;
    END
  END w0_wd_in[387]
  PIN w0_wd_in[388]
    DIRECTION OUTPUT ;
    USE SIGNAL ;
    SHAPE ABUTMENT ;
    PORT
      LAYER metal3 ;
      RECT 222.565 0.000 222.635 0.210 ;
    END
  END w0_wd_in[388]
  PIN w0_wd_in[389]
    DIRECTION OUTPUT ;
    USE SIGNAL ;
    SHAPE ABUTMENT ;
    PORT
      LAYER metal3 ;
      RECT 224.245 0.000 224.315 0.210 ;
    END
  END w0_wd_in[389]
  PIN w0_wd_in[390]
    DIRECTION OUTPUT ;
    USE SIGNAL ;
    SHAPE ABUTMENT ;
    PORT
      LAYER metal3 ;
      RECT 225.925 0.000 225.995 0.210 ;
    END
  END w0_wd_in[390]
  PIN w0_wd_in[391]
    DIRECTION OUTPUT ;
    USE SIGNAL ;
    SHAPE ABUTMENT ;
    PORT
      LAYER metal3 ;
      RECT 227.605 0.000 227.675 0.210 ;
    END
  END w0_wd_in[391]
  PIN w0_wd_in[392]
    DIRECTION OUTPUT ;
    USE SIGNAL ;
    SHAPE ABUTMENT ;
    PORT
      LAYER metal3 ;
      RECT 229.285 0.000 229.355 0.210 ;
    END
  END w0_wd_in[392]
  PIN w0_wd_in[393]
    DIRECTION OUTPUT ;
    USE SIGNAL ;
    SHAPE ABUTMENT ;
    PORT
      LAYER metal3 ;
      RECT 230.965 0.000 231.035 0.210 ;
    END
  END w0_wd_in[393]
  PIN w0_wd_in[394]
    DIRECTION OUTPUT ;
    USE SIGNAL ;
    SHAPE ABUTMENT ;
    PORT
      LAYER metal3 ;
      RECT 232.645 0.000 232.715 0.210 ;
    END
  END w0_wd_in[394]
  PIN w0_wd_in[395]
    DIRECTION OUTPUT ;
    USE SIGNAL ;
    SHAPE ABUTMENT ;
    PORT
      LAYER metal3 ;
      RECT 234.325 0.000 234.395 0.210 ;
    END
  END w0_wd_in[395]
  PIN w0_wd_in[396]
    DIRECTION OUTPUT ;
    USE SIGNAL ;
    SHAPE ABUTMENT ;
    PORT
      LAYER metal3 ;
      RECT 236.005 0.000 236.075 0.210 ;
    END
  END w0_wd_in[396]
  PIN w0_wd_in[397]
    DIRECTION OUTPUT ;
    USE SIGNAL ;
    SHAPE ABUTMENT ;
    PORT
      LAYER metal3 ;
      RECT 237.685 0.000 237.755 0.210 ;
    END
  END w0_wd_in[397]
  PIN w0_wd_in[398]
    DIRECTION OUTPUT ;
    USE SIGNAL ;
    SHAPE ABUTMENT ;
    PORT
      LAYER metal3 ;
      RECT 239.365 0.000 239.435 0.210 ;
    END
  END w0_wd_in[398]
  PIN w0_wd_in[399]
    DIRECTION OUTPUT ;
    USE SIGNAL ;
    SHAPE ABUTMENT ;
    PORT
      LAYER metal3 ;
      RECT 241.045 0.000 241.115 0.210 ;
    END
  END w0_wd_in[399]
  PIN w0_wd_in[400]
    DIRECTION OUTPUT ;
    USE SIGNAL ;
    SHAPE ABUTMENT ;
    PORT
      LAYER metal3 ;
      RECT 242.725 0.000 242.795 0.210 ;
    END
  END w0_wd_in[400]
  PIN w0_wd_in[401]
    DIRECTION OUTPUT ;
    USE SIGNAL ;
    SHAPE ABUTMENT ;
    PORT
      LAYER metal3 ;
      RECT 244.405 0.000 244.475 0.210 ;
    END
  END w0_wd_in[401]
  PIN w0_wd_in[402]
    DIRECTION OUTPUT ;
    USE SIGNAL ;
    SHAPE ABUTMENT ;
    PORT
      LAYER metal3 ;
      RECT 246.085 0.000 246.155 0.210 ;
    END
  END w0_wd_in[402]
  PIN w0_wd_in[403]
    DIRECTION OUTPUT ;
    USE SIGNAL ;
    SHAPE ABUTMENT ;
    PORT
      LAYER metal3 ;
      RECT 247.765 0.000 247.835 0.210 ;
    END
  END w0_wd_in[403]
  PIN w0_wd_in[404]
    DIRECTION OUTPUT ;
    USE SIGNAL ;
    SHAPE ABUTMENT ;
    PORT
      LAYER metal3 ;
      RECT 249.445 0.000 249.515 0.210 ;
    END
  END w0_wd_in[404]
  PIN w0_wd_in[405]
    DIRECTION OUTPUT ;
    USE SIGNAL ;
    SHAPE ABUTMENT ;
    PORT
      LAYER metal3 ;
      RECT 251.125 0.000 251.195 0.210 ;
    END
  END w0_wd_in[405]
  PIN w0_wd_in[406]
    DIRECTION OUTPUT ;
    USE SIGNAL ;
    SHAPE ABUTMENT ;
    PORT
      LAYER metal3 ;
      RECT 252.805 0.000 252.875 0.210 ;
    END
  END w0_wd_in[406]
  PIN w0_wd_in[407]
    DIRECTION OUTPUT ;
    USE SIGNAL ;
    SHAPE ABUTMENT ;
    PORT
      LAYER metal3 ;
      RECT 254.485 0.000 254.555 0.210 ;
    END
  END w0_wd_in[407]
  PIN w0_wd_in[408]
    DIRECTION OUTPUT ;
    USE SIGNAL ;
    SHAPE ABUTMENT ;
    PORT
      LAYER metal3 ;
      RECT 256.165 0.000 256.235 0.210 ;
    END
  END w0_wd_in[408]
  PIN w0_wd_in[409]
    DIRECTION OUTPUT ;
    USE SIGNAL ;
    SHAPE ABUTMENT ;
    PORT
      LAYER metal3 ;
      RECT 257.845 0.000 257.915 0.210 ;
    END
  END w0_wd_in[409]
  PIN w0_wd_in[410]
    DIRECTION OUTPUT ;
    USE SIGNAL ;
    SHAPE ABUTMENT ;
    PORT
      LAYER metal3 ;
      RECT 259.525 0.000 259.595 0.210 ;
    END
  END w0_wd_in[410]
  PIN w0_wd_in[411]
    DIRECTION OUTPUT ;
    USE SIGNAL ;
    SHAPE ABUTMENT ;
    PORT
      LAYER metal3 ;
      RECT 261.205 0.000 261.275 0.210 ;
    END
  END w0_wd_in[411]
  PIN w0_wd_in[412]
    DIRECTION OUTPUT ;
    USE SIGNAL ;
    SHAPE ABUTMENT ;
    PORT
      LAYER metal3 ;
      RECT 262.885 0.000 262.955 0.210 ;
    END
  END w0_wd_in[412]
  PIN w0_wd_in[413]
    DIRECTION OUTPUT ;
    USE SIGNAL ;
    SHAPE ABUTMENT ;
    PORT
      LAYER metal3 ;
      RECT 264.565 0.000 264.635 0.210 ;
    END
  END w0_wd_in[413]
  PIN w0_wd_in[414]
    DIRECTION OUTPUT ;
    USE SIGNAL ;
    SHAPE ABUTMENT ;
    PORT
      LAYER metal3 ;
      RECT 266.245 0.000 266.315 0.210 ;
    END
  END w0_wd_in[414]
  PIN w0_wd_in[415]
    DIRECTION OUTPUT ;
    USE SIGNAL ;
    SHAPE ABUTMENT ;
    PORT
      LAYER metal3 ;
      RECT 267.925 0.000 267.995 0.210 ;
    END
  END w0_wd_in[415]
  PIN w0_wd_in[416]
    DIRECTION OUTPUT ;
    USE SIGNAL ;
    SHAPE ABUTMENT ;
    PORT
      LAYER metal3 ;
      RECT 269.605 0.000 269.675 0.210 ;
    END
  END w0_wd_in[416]
  PIN w0_wd_in[417]
    DIRECTION OUTPUT ;
    USE SIGNAL ;
    SHAPE ABUTMENT ;
    PORT
      LAYER metal3 ;
      RECT 271.285 0.000 271.355 0.210 ;
    END
  END w0_wd_in[417]
  PIN w0_wd_in[418]
    DIRECTION OUTPUT ;
    USE SIGNAL ;
    SHAPE ABUTMENT ;
    PORT
      LAYER metal3 ;
      RECT 272.965 0.000 273.035 0.210 ;
    END
  END w0_wd_in[418]
  PIN w0_wd_in[419]
    DIRECTION OUTPUT ;
    USE SIGNAL ;
    SHAPE ABUTMENT ;
    PORT
      LAYER metal3 ;
      RECT 274.645 0.000 274.715 0.210 ;
    END
  END w0_wd_in[419]
  PIN w0_wd_in[420]
    DIRECTION OUTPUT ;
    USE SIGNAL ;
    SHAPE ABUTMENT ;
    PORT
      LAYER metal3 ;
      RECT 276.325 0.000 276.395 0.210 ;
    END
  END w0_wd_in[420]
  PIN w0_wd_in[421]
    DIRECTION OUTPUT ;
    USE SIGNAL ;
    SHAPE ABUTMENT ;
    PORT
      LAYER metal3 ;
      RECT 278.005 0.000 278.075 0.210 ;
    END
  END w0_wd_in[421]
  PIN w0_wd_in[422]
    DIRECTION OUTPUT ;
    USE SIGNAL ;
    SHAPE ABUTMENT ;
    PORT
      LAYER metal3 ;
      RECT 279.685 0.000 279.755 0.210 ;
    END
  END w0_wd_in[422]
  PIN w0_wd_in[423]
    DIRECTION OUTPUT ;
    USE SIGNAL ;
    SHAPE ABUTMENT ;
    PORT
      LAYER metal3 ;
      RECT 281.365 0.000 281.435 0.210 ;
    END
  END w0_wd_in[423]
  PIN w0_wd_in[424]
    DIRECTION OUTPUT ;
    USE SIGNAL ;
    SHAPE ABUTMENT ;
    PORT
      LAYER metal3 ;
      RECT 283.045 0.000 283.115 0.210 ;
    END
  END w0_wd_in[424]
  PIN w0_wd_in[425]
    DIRECTION OUTPUT ;
    USE SIGNAL ;
    SHAPE ABUTMENT ;
    PORT
      LAYER metal3 ;
      RECT 284.725 0.000 284.795 0.210 ;
    END
  END w0_wd_in[425]
  PIN w0_wd_in[426]
    DIRECTION OUTPUT ;
    USE SIGNAL ;
    SHAPE ABUTMENT ;
    PORT
      LAYER metal3 ;
      RECT 286.405 0.000 286.475 0.210 ;
    END
  END w0_wd_in[426]
  PIN w0_wd_in[427]
    DIRECTION OUTPUT ;
    USE SIGNAL ;
    SHAPE ABUTMENT ;
    PORT
      LAYER metal3 ;
      RECT 288.085 0.000 288.155 0.210 ;
    END
  END w0_wd_in[427]
  PIN w0_wd_in[428]
    DIRECTION OUTPUT ;
    USE SIGNAL ;
    SHAPE ABUTMENT ;
    PORT
      LAYER metal3 ;
      RECT 289.765 0.000 289.835 0.210 ;
    END
  END w0_wd_in[428]
  PIN w0_wd_in[429]
    DIRECTION OUTPUT ;
    USE SIGNAL ;
    SHAPE ABUTMENT ;
    PORT
      LAYER metal3 ;
      RECT 291.445 0.000 291.515 0.210 ;
    END
  END w0_wd_in[429]
  PIN w0_wd_in[430]
    DIRECTION OUTPUT ;
    USE SIGNAL ;
    SHAPE ABUTMENT ;
    PORT
      LAYER metal3 ;
      RECT 293.125 0.000 293.195 0.210 ;
    END
  END w0_wd_in[430]
  PIN w0_wd_in[431]
    DIRECTION OUTPUT ;
    USE SIGNAL ;
    SHAPE ABUTMENT ;
    PORT
      LAYER metal3 ;
      RECT 294.805 0.000 294.875 0.210 ;
    END
  END w0_wd_in[431]
  PIN w0_wd_in[432]
    DIRECTION OUTPUT ;
    USE SIGNAL ;
    SHAPE ABUTMENT ;
    PORT
      LAYER metal3 ;
      RECT 296.485 0.000 296.555 0.210 ;
    END
  END w0_wd_in[432]
  PIN w0_wd_in[433]
    DIRECTION OUTPUT ;
    USE SIGNAL ;
    SHAPE ABUTMENT ;
    PORT
      LAYER metal3 ;
      RECT 298.165 0.000 298.235 0.210 ;
    END
  END w0_wd_in[433]
  PIN w0_wd_in[434]
    DIRECTION OUTPUT ;
    USE SIGNAL ;
    SHAPE ABUTMENT ;
    PORT
      LAYER metal3 ;
      RECT 299.845 0.000 299.915 0.210 ;
    END
  END w0_wd_in[434]
  PIN w0_wd_in[435]
    DIRECTION OUTPUT ;
    USE SIGNAL ;
    SHAPE ABUTMENT ;
    PORT
      LAYER metal3 ;
      RECT 301.525 0.000 301.595 0.210 ;
    END
  END w0_wd_in[435]
  PIN w0_wd_in[436]
    DIRECTION OUTPUT ;
    USE SIGNAL ;
    SHAPE ABUTMENT ;
    PORT
      LAYER metal3 ;
      RECT 303.205 0.000 303.275 0.210 ;
    END
  END w0_wd_in[436]
  PIN w0_wd_in[437]
    DIRECTION OUTPUT ;
    USE SIGNAL ;
    SHAPE ABUTMENT ;
    PORT
      LAYER metal3 ;
      RECT 304.885 0.000 304.955 0.210 ;
    END
  END w0_wd_in[437]
  PIN w0_wd_in[438]
    DIRECTION OUTPUT ;
    USE SIGNAL ;
    SHAPE ABUTMENT ;
    PORT
      LAYER metal3 ;
      RECT 306.565 0.000 306.635 0.210 ;
    END
  END w0_wd_in[438]
  PIN w0_wd_in[439]
    DIRECTION OUTPUT ;
    USE SIGNAL ;
    SHAPE ABUTMENT ;
    PORT
      LAYER metal3 ;
      RECT 308.245 0.000 308.315 0.210 ;
    END
  END w0_wd_in[439]
  PIN w0_wd_in[440]
    DIRECTION OUTPUT ;
    USE SIGNAL ;
    SHAPE ABUTMENT ;
    PORT
      LAYER metal3 ;
      RECT 309.925 0.000 309.995 0.210 ;
    END
  END w0_wd_in[440]
  PIN w0_wd_in[441]
    DIRECTION OUTPUT ;
    USE SIGNAL ;
    SHAPE ABUTMENT ;
    PORT
      LAYER metal3 ;
      RECT 311.605 0.000 311.675 0.210 ;
    END
  END w0_wd_in[441]
  PIN w0_wd_in[442]
    DIRECTION OUTPUT ;
    USE SIGNAL ;
    SHAPE ABUTMENT ;
    PORT
      LAYER metal3 ;
      RECT 313.285 0.000 313.355 0.210 ;
    END
  END w0_wd_in[442]
  PIN w0_wd_in[443]
    DIRECTION OUTPUT ;
    USE SIGNAL ;
    SHAPE ABUTMENT ;
    PORT
      LAYER metal3 ;
      RECT 314.965 0.000 315.035 0.210 ;
    END
  END w0_wd_in[443]
  PIN w0_wd_in[444]
    DIRECTION OUTPUT ;
    USE SIGNAL ;
    SHAPE ABUTMENT ;
    PORT
      LAYER metal3 ;
      RECT 316.645 0.000 316.715 0.210 ;
    END
  END w0_wd_in[444]
  PIN w0_wd_in[445]
    DIRECTION OUTPUT ;
    USE SIGNAL ;
    SHAPE ABUTMENT ;
    PORT
      LAYER metal3 ;
      RECT 318.325 0.000 318.395 0.210 ;
    END
  END w0_wd_in[445]
  PIN w0_wd_in[446]
    DIRECTION OUTPUT ;
    USE SIGNAL ;
    SHAPE ABUTMENT ;
    PORT
      LAYER metal3 ;
      RECT 320.005 0.000 320.075 0.210 ;
    END
  END w0_wd_in[446]
  PIN w0_wd_in[447]
    DIRECTION OUTPUT ;
    USE SIGNAL ;
    SHAPE ABUTMENT ;
    PORT
      LAYER metal3 ;
      RECT 321.685 0.000 321.755 0.210 ;
    END
  END w0_wd_in[447]
  PIN w0_wd_in[448]
    DIRECTION OUTPUT ;
    USE SIGNAL ;
    SHAPE ABUTMENT ;
    PORT
      LAYER metal3 ;
      RECT 323.365 0.000 323.435 0.210 ;
    END
  END w0_wd_in[448]
  PIN w0_wd_in[449]
    DIRECTION OUTPUT ;
    USE SIGNAL ;
    SHAPE ABUTMENT ;
    PORT
      LAYER metal3 ;
      RECT 325.045 0.000 325.115 0.210 ;
    END
  END w0_wd_in[449]
  PIN w0_wd_in[450]
    DIRECTION OUTPUT ;
    USE SIGNAL ;
    SHAPE ABUTMENT ;
    PORT
      LAYER metal3 ;
      RECT 326.725 0.000 326.795 0.210 ;
    END
  END w0_wd_in[450]
  PIN w0_wd_in[451]
    DIRECTION OUTPUT ;
    USE SIGNAL ;
    SHAPE ABUTMENT ;
    PORT
      LAYER metal3 ;
      RECT 328.405 0.000 328.475 0.210 ;
    END
  END w0_wd_in[451]
  PIN w0_wd_in[452]
    DIRECTION OUTPUT ;
    USE SIGNAL ;
    SHAPE ABUTMENT ;
    PORT
      LAYER metal3 ;
      RECT 330.085 0.000 330.155 0.210 ;
    END
  END w0_wd_in[452]
  PIN w0_wd_in[453]
    DIRECTION OUTPUT ;
    USE SIGNAL ;
    SHAPE ABUTMENT ;
    PORT
      LAYER metal3 ;
      RECT 331.765 0.000 331.835 0.210 ;
    END
  END w0_wd_in[453]
  PIN w0_wd_in[454]
    DIRECTION OUTPUT ;
    USE SIGNAL ;
    SHAPE ABUTMENT ;
    PORT
      LAYER metal3 ;
      RECT 333.445 0.000 333.515 0.210 ;
    END
  END w0_wd_in[454]
  PIN w0_wd_in[455]
    DIRECTION OUTPUT ;
    USE SIGNAL ;
    SHAPE ABUTMENT ;
    PORT
      LAYER metal3 ;
      RECT 335.125 0.000 335.195 0.210 ;
    END
  END w0_wd_in[455]
  PIN w0_wd_in[456]
    DIRECTION OUTPUT ;
    USE SIGNAL ;
    SHAPE ABUTMENT ;
    PORT
      LAYER metal3 ;
      RECT 336.805 0.000 336.875 0.210 ;
    END
  END w0_wd_in[456]
  PIN w0_wd_in[457]
    DIRECTION OUTPUT ;
    USE SIGNAL ;
    SHAPE ABUTMENT ;
    PORT
      LAYER metal3 ;
      RECT 338.485 0.000 338.555 0.210 ;
    END
  END w0_wd_in[457]
  PIN w0_wd_in[458]
    DIRECTION OUTPUT ;
    USE SIGNAL ;
    SHAPE ABUTMENT ;
    PORT
      LAYER metal3 ;
      RECT 340.165 0.000 340.235 0.210 ;
    END
  END w0_wd_in[458]
  PIN w0_wd_in[459]
    DIRECTION OUTPUT ;
    USE SIGNAL ;
    SHAPE ABUTMENT ;
    PORT
      LAYER metal3 ;
      RECT 341.845 0.000 341.915 0.210 ;
    END
  END w0_wd_in[459]
  PIN w0_wd_in[460]
    DIRECTION OUTPUT ;
    USE SIGNAL ;
    SHAPE ABUTMENT ;
    PORT
      LAYER metal3 ;
      RECT 343.525 0.000 343.595 0.210 ;
    END
  END w0_wd_in[460]
  PIN w0_wd_in[461]
    DIRECTION OUTPUT ;
    USE SIGNAL ;
    SHAPE ABUTMENT ;
    PORT
      LAYER metal3 ;
      RECT 345.205 0.000 345.275 0.210 ;
    END
  END w0_wd_in[461]
  PIN w0_wd_in[462]
    DIRECTION OUTPUT ;
    USE SIGNAL ;
    SHAPE ABUTMENT ;
    PORT
      LAYER metal3 ;
      RECT 346.885 0.000 346.955 0.210 ;
    END
  END w0_wd_in[462]
  PIN w0_wd_in[463]
    DIRECTION OUTPUT ;
    USE SIGNAL ;
    SHAPE ABUTMENT ;
    PORT
      LAYER metal3 ;
      RECT 348.565 0.000 348.635 0.210 ;
    END
  END w0_wd_in[463]
  PIN w0_wd_in[464]
    DIRECTION OUTPUT ;
    USE SIGNAL ;
    SHAPE ABUTMENT ;
    PORT
      LAYER metal3 ;
      RECT 350.245 0.000 350.315 0.210 ;
    END
  END w0_wd_in[464]
  PIN w0_wd_in[465]
    DIRECTION OUTPUT ;
    USE SIGNAL ;
    SHAPE ABUTMENT ;
    PORT
      LAYER metal3 ;
      RECT 351.925 0.000 351.995 0.210 ;
    END
  END w0_wd_in[465]
  PIN w0_wd_in[466]
    DIRECTION OUTPUT ;
    USE SIGNAL ;
    SHAPE ABUTMENT ;
    PORT
      LAYER metal3 ;
      RECT 353.605 0.000 353.675 0.210 ;
    END
  END w0_wd_in[466]
  PIN w0_wd_in[467]
    DIRECTION OUTPUT ;
    USE SIGNAL ;
    SHAPE ABUTMENT ;
    PORT
      LAYER metal3 ;
      RECT 355.285 0.000 355.355 0.210 ;
    END
  END w0_wd_in[467]
  PIN w0_wd_in[468]
    DIRECTION OUTPUT ;
    USE SIGNAL ;
    SHAPE ABUTMENT ;
    PORT
      LAYER metal3 ;
      RECT 356.965 0.000 357.035 0.210 ;
    END
  END w0_wd_in[468]
  PIN w0_wd_in[469]
    DIRECTION OUTPUT ;
    USE SIGNAL ;
    SHAPE ABUTMENT ;
    PORT
      LAYER metal3 ;
      RECT 358.645 0.000 358.715 0.210 ;
    END
  END w0_wd_in[469]
  PIN w0_wd_in[470]
    DIRECTION OUTPUT ;
    USE SIGNAL ;
    SHAPE ABUTMENT ;
    PORT
      LAYER metal3 ;
      RECT 360.325 0.000 360.395 0.210 ;
    END
  END w0_wd_in[470]
  PIN w0_wd_in[471]
    DIRECTION OUTPUT ;
    USE SIGNAL ;
    SHAPE ABUTMENT ;
    PORT
      LAYER metal3 ;
      RECT 362.005 0.000 362.075 0.210 ;
    END
  END w0_wd_in[471]
  PIN w0_wd_in[472]
    DIRECTION OUTPUT ;
    USE SIGNAL ;
    SHAPE ABUTMENT ;
    PORT
      LAYER metal3 ;
      RECT 363.685 0.000 363.755 0.210 ;
    END
  END w0_wd_in[472]
  PIN w0_wd_in[473]
    DIRECTION OUTPUT ;
    USE SIGNAL ;
    SHAPE ABUTMENT ;
    PORT
      LAYER metal3 ;
      RECT 365.365 0.000 365.435 0.210 ;
    END
  END w0_wd_in[473]
  PIN w0_wd_in[474]
    DIRECTION OUTPUT ;
    USE SIGNAL ;
    SHAPE ABUTMENT ;
    PORT
      LAYER metal3 ;
      RECT 367.045 0.000 367.115 0.210 ;
    END
  END w0_wd_in[474]
  PIN w0_wd_in[475]
    DIRECTION OUTPUT ;
    USE SIGNAL ;
    SHAPE ABUTMENT ;
    PORT
      LAYER metal3 ;
      RECT 368.725 0.000 368.795 0.210 ;
    END
  END w0_wd_in[475]
  PIN w0_wd_in[476]
    DIRECTION OUTPUT ;
    USE SIGNAL ;
    SHAPE ABUTMENT ;
    PORT
      LAYER metal3 ;
      RECT 370.405 0.000 370.475 0.210 ;
    END
  END w0_wd_in[476]
  PIN w0_wd_in[477]
    DIRECTION OUTPUT ;
    USE SIGNAL ;
    SHAPE ABUTMENT ;
    PORT
      LAYER metal3 ;
      RECT 372.085 0.000 372.155 0.210 ;
    END
  END w0_wd_in[477]
  PIN w0_wd_in[478]
    DIRECTION OUTPUT ;
    USE SIGNAL ;
    SHAPE ABUTMENT ;
    PORT
      LAYER metal3 ;
      RECT 373.765 0.000 373.835 0.210 ;
    END
  END w0_wd_in[478]
  PIN w0_wd_in[479]
    DIRECTION OUTPUT ;
    USE SIGNAL ;
    SHAPE ABUTMENT ;
    PORT
      LAYER metal3 ;
      RECT 375.445 0.000 375.515 0.210 ;
    END
  END w0_wd_in[479]
  PIN w0_wd_in[480]
    DIRECTION OUTPUT ;
    USE SIGNAL ;
    SHAPE ABUTMENT ;
    PORT
      LAYER metal3 ;
      RECT 377.125 0.000 377.195 0.210 ;
    END
  END w0_wd_in[480]
  PIN w0_wd_in[481]
    DIRECTION OUTPUT ;
    USE SIGNAL ;
    SHAPE ABUTMENT ;
    PORT
      LAYER metal3 ;
      RECT 378.805 0.000 378.875 0.210 ;
    END
  END w0_wd_in[481]
  PIN w0_wd_in[482]
    DIRECTION OUTPUT ;
    USE SIGNAL ;
    SHAPE ABUTMENT ;
    PORT
      LAYER metal3 ;
      RECT 380.485 0.000 380.555 0.210 ;
    END
  END w0_wd_in[482]
  PIN w0_wd_in[483]
    DIRECTION OUTPUT ;
    USE SIGNAL ;
    SHAPE ABUTMENT ;
    PORT
      LAYER metal3 ;
      RECT 382.165 0.000 382.235 0.210 ;
    END
  END w0_wd_in[483]
  PIN w0_wd_in[484]
    DIRECTION OUTPUT ;
    USE SIGNAL ;
    SHAPE ABUTMENT ;
    PORT
      LAYER metal3 ;
      RECT 383.845 0.000 383.915 0.210 ;
    END
  END w0_wd_in[484]
  PIN w0_wd_in[485]
    DIRECTION OUTPUT ;
    USE SIGNAL ;
    SHAPE ABUTMENT ;
    PORT
      LAYER metal3 ;
      RECT 385.525 0.000 385.595 0.210 ;
    END
  END w0_wd_in[485]
  PIN w0_wd_in[486]
    DIRECTION OUTPUT ;
    USE SIGNAL ;
    SHAPE ABUTMENT ;
    PORT
      LAYER metal3 ;
      RECT 387.205 0.000 387.275 0.210 ;
    END
  END w0_wd_in[486]
  PIN w0_wd_in[487]
    DIRECTION OUTPUT ;
    USE SIGNAL ;
    SHAPE ABUTMENT ;
    PORT
      LAYER metal3 ;
      RECT 388.885 0.000 388.955 0.210 ;
    END
  END w0_wd_in[487]
  PIN w0_wd_in[488]
    DIRECTION OUTPUT ;
    USE SIGNAL ;
    SHAPE ABUTMENT ;
    PORT
      LAYER metal3 ;
      RECT 390.565 0.000 390.635 0.210 ;
    END
  END w0_wd_in[488]
  PIN w0_wd_in[489]
    DIRECTION OUTPUT ;
    USE SIGNAL ;
    SHAPE ABUTMENT ;
    PORT
      LAYER metal3 ;
      RECT 392.245 0.000 392.315 0.210 ;
    END
  END w0_wd_in[489]
  PIN w0_wd_in[490]
    DIRECTION OUTPUT ;
    USE SIGNAL ;
    SHAPE ABUTMENT ;
    PORT
      LAYER metal3 ;
      RECT 393.925 0.000 393.995 0.210 ;
    END
  END w0_wd_in[490]
  PIN w0_wd_in[491]
    DIRECTION OUTPUT ;
    USE SIGNAL ;
    SHAPE ABUTMENT ;
    PORT
      LAYER metal3 ;
      RECT 395.605 0.000 395.675 0.210 ;
    END
  END w0_wd_in[491]
  PIN w0_wd_in[492]
    DIRECTION OUTPUT ;
    USE SIGNAL ;
    SHAPE ABUTMENT ;
    PORT
      LAYER metal3 ;
      RECT 397.285 0.000 397.355 0.210 ;
    END
  END w0_wd_in[492]
  PIN w0_wd_in[493]
    DIRECTION OUTPUT ;
    USE SIGNAL ;
    SHAPE ABUTMENT ;
    PORT
      LAYER metal3 ;
      RECT 398.965 0.000 399.035 0.210 ;
    END
  END w0_wd_in[493]
  PIN w0_wd_in[494]
    DIRECTION OUTPUT ;
    USE SIGNAL ;
    SHAPE ABUTMENT ;
    PORT
      LAYER metal3 ;
      RECT 400.645 0.000 400.715 0.210 ;
    END
  END w0_wd_in[494]
  PIN w0_wd_in[495]
    DIRECTION OUTPUT ;
    USE SIGNAL ;
    SHAPE ABUTMENT ;
    PORT
      LAYER metal3 ;
      RECT 402.325 0.000 402.395 0.210 ;
    END
  END w0_wd_in[495]
  PIN w0_wd_in[496]
    DIRECTION OUTPUT ;
    USE SIGNAL ;
    SHAPE ABUTMENT ;
    PORT
      LAYER metal3 ;
      RECT 404.005 0.000 404.075 0.210 ;
    END
  END w0_wd_in[496]
  PIN w0_wd_in[497]
    DIRECTION OUTPUT ;
    USE SIGNAL ;
    SHAPE ABUTMENT ;
    PORT
      LAYER metal3 ;
      RECT 405.685 0.000 405.755 0.210 ;
    END
  END w0_wd_in[497]
  PIN w0_wd_in[498]
    DIRECTION OUTPUT ;
    USE SIGNAL ;
    SHAPE ABUTMENT ;
    PORT
      LAYER metal3 ;
      RECT 407.365 0.000 407.435 0.210 ;
    END
  END w0_wd_in[498]
  PIN w0_wd_in[499]
    DIRECTION OUTPUT ;
    USE SIGNAL ;
    SHAPE ABUTMENT ;
    PORT
      LAYER metal3 ;
      RECT 409.045 0.000 409.115 0.210 ;
    END
  END w0_wd_in[499]
  PIN w0_wd_in[500]
    DIRECTION OUTPUT ;
    USE SIGNAL ;
    SHAPE ABUTMENT ;
    PORT
      LAYER metal3 ;
      RECT 410.725 0.000 410.795 0.210 ;
    END
  END w0_wd_in[500]
  PIN w0_wd_in[501]
    DIRECTION OUTPUT ;
    USE SIGNAL ;
    SHAPE ABUTMENT ;
    PORT
      LAYER metal3 ;
      RECT 412.405 0.000 412.475 0.210 ;
    END
  END w0_wd_in[501]
  PIN w0_wd_in[502]
    DIRECTION OUTPUT ;
    USE SIGNAL ;
    SHAPE ABUTMENT ;
    PORT
      LAYER metal3 ;
      RECT 414.085 0.000 414.155 0.210 ;
    END
  END w0_wd_in[502]
  PIN w0_wd_in[503]
    DIRECTION OUTPUT ;
    USE SIGNAL ;
    SHAPE ABUTMENT ;
    PORT
      LAYER metal3 ;
      RECT 415.765 0.000 415.835 0.210 ;
    END
  END w0_wd_in[503]
  PIN w0_wd_in[504]
    DIRECTION OUTPUT ;
    USE SIGNAL ;
    SHAPE ABUTMENT ;
    PORT
      LAYER metal3 ;
      RECT 417.445 0.000 417.515 0.210 ;
    END
  END w0_wd_in[504]
  PIN w0_wd_in[505]
    DIRECTION OUTPUT ;
    USE SIGNAL ;
    SHAPE ABUTMENT ;
    PORT
      LAYER metal3 ;
      RECT 419.125 0.000 419.195 0.210 ;
    END
  END w0_wd_in[505]
  PIN w0_wd_in[506]
    DIRECTION OUTPUT ;
    USE SIGNAL ;
    SHAPE ABUTMENT ;
    PORT
      LAYER metal3 ;
      RECT 420.805 0.000 420.875 0.210 ;
    END
  END w0_wd_in[506]
  PIN w0_wd_in[507]
    DIRECTION OUTPUT ;
    USE SIGNAL ;
    SHAPE ABUTMENT ;
    PORT
      LAYER metal3 ;
      RECT 422.485 0.000 422.555 0.210 ;
    END
  END w0_wd_in[507]
  PIN w0_wd_in[508]
    DIRECTION OUTPUT ;
    USE SIGNAL ;
    SHAPE ABUTMENT ;
    PORT
      LAYER metal3 ;
      RECT 424.165 0.000 424.235 0.210 ;
    END
  END w0_wd_in[508]
  PIN w0_wd_in[509]
    DIRECTION OUTPUT ;
    USE SIGNAL ;
    SHAPE ABUTMENT ;
    PORT
      LAYER metal3 ;
      RECT 425.845 0.000 425.915 0.210 ;
    END
  END w0_wd_in[509]
  PIN w0_wd_in[510]
    DIRECTION OUTPUT ;
    USE SIGNAL ;
    SHAPE ABUTMENT ;
    PORT
      LAYER metal3 ;
      RECT 427.525 0.000 427.595 0.210 ;
    END
  END w0_wd_in[510]
  PIN w0_wd_in[511]
    DIRECTION OUTPUT ;
    USE SIGNAL ;
    SHAPE ABUTMENT ;
    PORT
      LAYER metal3 ;
      RECT 429.205 0.000 429.275 0.210 ;
    END
  END w0_wd_in[511]
  PIN r0_rd_out[0]
    DIRECTION OUTPUT ;
    USE SIGNAL ;
    SHAPE ABUTMENT ;
    PORT
      LAYER metal3 ;
      RECT 430.885 0.000 430.955 0.210 ;
    END
  END r0_rd_out[0]
  PIN r0_rd_out[1]
    DIRECTION OUTPUT ;
    USE SIGNAL ;
    SHAPE ABUTMENT ;
    PORT
      LAYER metal3 ;
      RECT 432.565 0.000 432.635 0.210 ;
    END
  END r0_rd_out[1]
  PIN r0_rd_out[2]
    DIRECTION OUTPUT ;
    USE SIGNAL ;
    SHAPE ABUTMENT ;
    PORT
      LAYER metal3 ;
      RECT 434.245 0.000 434.315 0.210 ;
    END
  END r0_rd_out[2]
  PIN r0_rd_out[3]
    DIRECTION OUTPUT ;
    USE SIGNAL ;
    SHAPE ABUTMENT ;
    PORT
      LAYER metal3 ;
      RECT 435.925 0.000 435.995 0.210 ;
    END
  END r0_rd_out[3]
  PIN r0_rd_out[4]
    DIRECTION OUTPUT ;
    USE SIGNAL ;
    SHAPE ABUTMENT ;
    PORT
      LAYER metal3 ;
      RECT 437.605 0.000 437.675 0.210 ;
    END
  END r0_rd_out[4]
  PIN r0_rd_out[5]
    DIRECTION OUTPUT ;
    USE SIGNAL ;
    SHAPE ABUTMENT ;
    PORT
      LAYER metal3 ;
      RECT 439.285 0.000 439.355 0.210 ;
    END
  END r0_rd_out[5]
  PIN r0_rd_out[6]
    DIRECTION OUTPUT ;
    USE SIGNAL ;
    SHAPE ABUTMENT ;
    PORT
      LAYER metal3 ;
      RECT 440.965 0.000 441.035 0.210 ;
    END
  END r0_rd_out[6]
  PIN r0_rd_out[7]
    DIRECTION OUTPUT ;
    USE SIGNAL ;
    SHAPE ABUTMENT ;
    PORT
      LAYER metal3 ;
      RECT 442.645 0.000 442.715 0.210 ;
    END
  END r0_rd_out[7]
  PIN r0_rd_out[8]
    DIRECTION OUTPUT ;
    USE SIGNAL ;
    SHAPE ABUTMENT ;
    PORT
      LAYER metal3 ;
      RECT 444.325 0.000 444.395 0.210 ;
    END
  END r0_rd_out[8]
  PIN r0_rd_out[9]
    DIRECTION OUTPUT ;
    USE SIGNAL ;
    SHAPE ABUTMENT ;
    PORT
      LAYER metal3 ;
      RECT 446.005 0.000 446.075 0.210 ;
    END
  END r0_rd_out[9]
  PIN r0_rd_out[10]
    DIRECTION OUTPUT ;
    USE SIGNAL ;
    SHAPE ABUTMENT ;
    PORT
      LAYER metal3 ;
      RECT 447.685 0.000 447.755 0.210 ;
    END
  END r0_rd_out[10]
  PIN r0_rd_out[11]
    DIRECTION OUTPUT ;
    USE SIGNAL ;
    SHAPE ABUTMENT ;
    PORT
      LAYER metal3 ;
      RECT 449.365 0.000 449.435 0.210 ;
    END
  END r0_rd_out[11]
  PIN r0_rd_out[12]
    DIRECTION OUTPUT ;
    USE SIGNAL ;
    SHAPE ABUTMENT ;
    PORT
      LAYER metal3 ;
      RECT 451.045 0.000 451.115 0.210 ;
    END
  END r0_rd_out[12]
  PIN r0_rd_out[13]
    DIRECTION OUTPUT ;
    USE SIGNAL ;
    SHAPE ABUTMENT ;
    PORT
      LAYER metal3 ;
      RECT 452.725 0.000 452.795 0.210 ;
    END
  END r0_rd_out[13]
  PIN r0_rd_out[14]
    DIRECTION OUTPUT ;
    USE SIGNAL ;
    SHAPE ABUTMENT ;
    PORT
      LAYER metal3 ;
      RECT 454.405 0.000 454.475 0.210 ;
    END
  END r0_rd_out[14]
  PIN r0_rd_out[15]
    DIRECTION OUTPUT ;
    USE SIGNAL ;
    SHAPE ABUTMENT ;
    PORT
      LAYER metal3 ;
      RECT 456.085 0.000 456.155 0.210 ;
    END
  END r0_rd_out[15]
  PIN r0_rd_out[16]
    DIRECTION OUTPUT ;
    USE SIGNAL ;
    SHAPE ABUTMENT ;
    PORT
      LAYER metal3 ;
      RECT 457.765 0.000 457.835 0.210 ;
    END
  END r0_rd_out[16]
  PIN r0_rd_out[17]
    DIRECTION OUTPUT ;
    USE SIGNAL ;
    SHAPE ABUTMENT ;
    PORT
      LAYER metal3 ;
      RECT 459.445 0.000 459.515 0.210 ;
    END
  END r0_rd_out[17]
  PIN r0_rd_out[18]
    DIRECTION OUTPUT ;
    USE SIGNAL ;
    SHAPE ABUTMENT ;
    PORT
      LAYER metal3 ;
      RECT 461.125 0.000 461.195 0.210 ;
    END
  END r0_rd_out[18]
  PIN r0_rd_out[19]
    DIRECTION OUTPUT ;
    USE SIGNAL ;
    SHAPE ABUTMENT ;
    PORT
      LAYER metal3 ;
      RECT 462.805 0.000 462.875 0.210 ;
    END
  END r0_rd_out[19]
  PIN r0_rd_out[20]
    DIRECTION OUTPUT ;
    USE SIGNAL ;
    SHAPE ABUTMENT ;
    PORT
      LAYER metal3 ;
      RECT 464.485 0.000 464.555 0.210 ;
    END
  END r0_rd_out[20]
  PIN r0_rd_out[21]
    DIRECTION OUTPUT ;
    USE SIGNAL ;
    SHAPE ABUTMENT ;
    PORT
      LAYER metal3 ;
      RECT 466.165 0.000 466.235 0.210 ;
    END
  END r0_rd_out[21]
  PIN r0_rd_out[22]
    DIRECTION OUTPUT ;
    USE SIGNAL ;
    SHAPE ABUTMENT ;
    PORT
      LAYER metal3 ;
      RECT 467.845 0.000 467.915 0.210 ;
    END
  END r0_rd_out[22]
  PIN r0_rd_out[23]
    DIRECTION OUTPUT ;
    USE SIGNAL ;
    SHAPE ABUTMENT ;
    PORT
      LAYER metal3 ;
      RECT 469.525 0.000 469.595 0.210 ;
    END
  END r0_rd_out[23]
  PIN r0_rd_out[24]
    DIRECTION OUTPUT ;
    USE SIGNAL ;
    SHAPE ABUTMENT ;
    PORT
      LAYER metal3 ;
      RECT 471.205 0.000 471.275 0.210 ;
    END
  END r0_rd_out[24]
  PIN r0_rd_out[25]
    DIRECTION OUTPUT ;
    USE SIGNAL ;
    SHAPE ABUTMENT ;
    PORT
      LAYER metal3 ;
      RECT 472.885 0.000 472.955 0.210 ;
    END
  END r0_rd_out[25]
  PIN r0_rd_out[26]
    DIRECTION OUTPUT ;
    USE SIGNAL ;
    SHAPE ABUTMENT ;
    PORT
      LAYER metal3 ;
      RECT 474.565 0.000 474.635 0.210 ;
    END
  END r0_rd_out[26]
  PIN r0_rd_out[27]
    DIRECTION OUTPUT ;
    USE SIGNAL ;
    SHAPE ABUTMENT ;
    PORT
      LAYER metal3 ;
      RECT 476.245 0.000 476.315 0.210 ;
    END
  END r0_rd_out[27]
  PIN r0_rd_out[28]
    DIRECTION OUTPUT ;
    USE SIGNAL ;
    SHAPE ABUTMENT ;
    PORT
      LAYER metal3 ;
      RECT 477.925 0.000 477.995 0.210 ;
    END
  END r0_rd_out[28]
  PIN r0_rd_out[29]
    DIRECTION OUTPUT ;
    USE SIGNAL ;
    SHAPE ABUTMENT ;
    PORT
      LAYER metal3 ;
      RECT 479.605 0.000 479.675 0.210 ;
    END
  END r0_rd_out[29]
  PIN r0_rd_out[30]
    DIRECTION OUTPUT ;
    USE SIGNAL ;
    SHAPE ABUTMENT ;
    PORT
      LAYER metal3 ;
      RECT 481.285 0.000 481.355 0.210 ;
    END
  END r0_rd_out[30]
  PIN r0_rd_out[31]
    DIRECTION OUTPUT ;
    USE SIGNAL ;
    SHAPE ABUTMENT ;
    PORT
      LAYER metal3 ;
      RECT 482.965 0.000 483.035 0.210 ;
    END
  END r0_rd_out[31]
  PIN r0_rd_out[32]
    DIRECTION OUTPUT ;
    USE SIGNAL ;
    SHAPE ABUTMENT ;
    PORT
      LAYER metal3 ;
      RECT 484.645 0.000 484.715 0.210 ;
    END
  END r0_rd_out[32]
  PIN r0_rd_out[33]
    DIRECTION OUTPUT ;
    USE SIGNAL ;
    SHAPE ABUTMENT ;
    PORT
      LAYER metal3 ;
      RECT 486.325 0.000 486.395 0.210 ;
    END
  END r0_rd_out[33]
  PIN r0_rd_out[34]
    DIRECTION OUTPUT ;
    USE SIGNAL ;
    SHAPE ABUTMENT ;
    PORT
      LAYER metal3 ;
      RECT 488.005 0.000 488.075 0.210 ;
    END
  END r0_rd_out[34]
  PIN r0_rd_out[35]
    DIRECTION OUTPUT ;
    USE SIGNAL ;
    SHAPE ABUTMENT ;
    PORT
      LAYER metal3 ;
      RECT 489.685 0.000 489.755 0.210 ;
    END
  END r0_rd_out[35]
  PIN r0_rd_out[36]
    DIRECTION OUTPUT ;
    USE SIGNAL ;
    SHAPE ABUTMENT ;
    PORT
      LAYER metal3 ;
      RECT 491.365 0.000 491.435 0.210 ;
    END
  END r0_rd_out[36]
  PIN r0_rd_out[37]
    DIRECTION OUTPUT ;
    USE SIGNAL ;
    SHAPE ABUTMENT ;
    PORT
      LAYER metal3 ;
      RECT 493.045 0.000 493.115 0.210 ;
    END
  END r0_rd_out[37]
  PIN r0_rd_out[38]
    DIRECTION OUTPUT ;
    USE SIGNAL ;
    SHAPE ABUTMENT ;
    PORT
      LAYER metal3 ;
      RECT 494.725 0.000 494.795 0.210 ;
    END
  END r0_rd_out[38]
  PIN r0_rd_out[39]
    DIRECTION OUTPUT ;
    USE SIGNAL ;
    SHAPE ABUTMENT ;
    PORT
      LAYER metal3 ;
      RECT 496.405 0.000 496.475 0.210 ;
    END
  END r0_rd_out[39]
  PIN r0_rd_out[40]
    DIRECTION OUTPUT ;
    USE SIGNAL ;
    SHAPE ABUTMENT ;
    PORT
      LAYER metal3 ;
      RECT 498.085 0.000 498.155 0.210 ;
    END
  END r0_rd_out[40]
  PIN r0_rd_out[41]
    DIRECTION OUTPUT ;
    USE SIGNAL ;
    SHAPE ABUTMENT ;
    PORT
      LAYER metal3 ;
      RECT 499.765 0.000 499.835 0.210 ;
    END
  END r0_rd_out[41]
  PIN r0_rd_out[42]
    DIRECTION OUTPUT ;
    USE SIGNAL ;
    SHAPE ABUTMENT ;
    PORT
      LAYER metal3 ;
      RECT 501.445 0.000 501.515 0.210 ;
    END
  END r0_rd_out[42]
  PIN r0_rd_out[43]
    DIRECTION OUTPUT ;
    USE SIGNAL ;
    SHAPE ABUTMENT ;
    PORT
      LAYER metal3 ;
      RECT 503.125 0.000 503.195 0.210 ;
    END
  END r0_rd_out[43]
  PIN r0_rd_out[44]
    DIRECTION OUTPUT ;
    USE SIGNAL ;
    SHAPE ABUTMENT ;
    PORT
      LAYER metal3 ;
      RECT 504.805 0.000 504.875 0.210 ;
    END
  END r0_rd_out[44]
  PIN r0_rd_out[45]
    DIRECTION OUTPUT ;
    USE SIGNAL ;
    SHAPE ABUTMENT ;
    PORT
      LAYER metal3 ;
      RECT 506.485 0.000 506.555 0.210 ;
    END
  END r0_rd_out[45]
  PIN r0_rd_out[46]
    DIRECTION OUTPUT ;
    USE SIGNAL ;
    SHAPE ABUTMENT ;
    PORT
      LAYER metal3 ;
      RECT 508.165 0.000 508.235 0.210 ;
    END
  END r0_rd_out[46]
  PIN r0_rd_out[47]
    DIRECTION OUTPUT ;
    USE SIGNAL ;
    SHAPE ABUTMENT ;
    PORT
      LAYER metal3 ;
      RECT 509.845 0.000 509.915 0.210 ;
    END
  END r0_rd_out[47]
  PIN r0_rd_out[48]
    DIRECTION OUTPUT ;
    USE SIGNAL ;
    SHAPE ABUTMENT ;
    PORT
      LAYER metal3 ;
      RECT 511.525 0.000 511.595 0.210 ;
    END
  END r0_rd_out[48]
  PIN r0_rd_out[49]
    DIRECTION OUTPUT ;
    USE SIGNAL ;
    SHAPE ABUTMENT ;
    PORT
      LAYER metal3 ;
      RECT 513.205 0.000 513.275 0.210 ;
    END
  END r0_rd_out[49]
  PIN r0_rd_out[50]
    DIRECTION OUTPUT ;
    USE SIGNAL ;
    SHAPE ABUTMENT ;
    PORT
      LAYER metal3 ;
      RECT 514.885 0.000 514.955 0.210 ;
    END
  END r0_rd_out[50]
  PIN r0_rd_out[51]
    DIRECTION OUTPUT ;
    USE SIGNAL ;
    SHAPE ABUTMENT ;
    PORT
      LAYER metal3 ;
      RECT 516.565 0.000 516.635 0.210 ;
    END
  END r0_rd_out[51]
  PIN r0_rd_out[52]
    DIRECTION OUTPUT ;
    USE SIGNAL ;
    SHAPE ABUTMENT ;
    PORT
      LAYER metal3 ;
      RECT 518.245 0.000 518.315 0.210 ;
    END
  END r0_rd_out[52]
  PIN r0_rd_out[53]
    DIRECTION OUTPUT ;
    USE SIGNAL ;
    SHAPE ABUTMENT ;
    PORT
      LAYER metal3 ;
      RECT 519.925 0.000 519.995 0.210 ;
    END
  END r0_rd_out[53]
  PIN r0_rd_out[54]
    DIRECTION OUTPUT ;
    USE SIGNAL ;
    SHAPE ABUTMENT ;
    PORT
      LAYER metal3 ;
      RECT 521.605 0.000 521.675 0.210 ;
    END
  END r0_rd_out[54]
  PIN r0_rd_out[55]
    DIRECTION OUTPUT ;
    USE SIGNAL ;
    SHAPE ABUTMENT ;
    PORT
      LAYER metal3 ;
      RECT 523.285 0.000 523.355 0.210 ;
    END
  END r0_rd_out[55]
  PIN r0_rd_out[56]
    DIRECTION OUTPUT ;
    USE SIGNAL ;
    SHAPE ABUTMENT ;
    PORT
      LAYER metal3 ;
      RECT 524.965 0.000 525.035 0.210 ;
    END
  END r0_rd_out[56]
  PIN r0_rd_out[57]
    DIRECTION OUTPUT ;
    USE SIGNAL ;
    SHAPE ABUTMENT ;
    PORT
      LAYER metal3 ;
      RECT 526.645 0.000 526.715 0.210 ;
    END
  END r0_rd_out[57]
  PIN r0_rd_out[58]
    DIRECTION OUTPUT ;
    USE SIGNAL ;
    SHAPE ABUTMENT ;
    PORT
      LAYER metal3 ;
      RECT 528.325 0.000 528.395 0.210 ;
    END
  END r0_rd_out[58]
  PIN r0_rd_out[59]
    DIRECTION OUTPUT ;
    USE SIGNAL ;
    SHAPE ABUTMENT ;
    PORT
      LAYER metal3 ;
      RECT 530.005 0.000 530.075 0.210 ;
    END
  END r0_rd_out[59]
  PIN r0_rd_out[60]
    DIRECTION OUTPUT ;
    USE SIGNAL ;
    SHAPE ABUTMENT ;
    PORT
      LAYER metal3 ;
      RECT 531.685 0.000 531.755 0.210 ;
    END
  END r0_rd_out[60]
  PIN r0_rd_out[61]
    DIRECTION OUTPUT ;
    USE SIGNAL ;
    SHAPE ABUTMENT ;
    PORT
      LAYER metal3 ;
      RECT 533.365 0.000 533.435 0.210 ;
    END
  END r0_rd_out[61]
  PIN r0_rd_out[62]
    DIRECTION OUTPUT ;
    USE SIGNAL ;
    SHAPE ABUTMENT ;
    PORT
      LAYER metal3 ;
      RECT 535.045 0.000 535.115 0.210 ;
    END
  END r0_rd_out[62]
  PIN r0_rd_out[63]
    DIRECTION OUTPUT ;
    USE SIGNAL ;
    SHAPE ABUTMENT ;
    PORT
      LAYER metal3 ;
      RECT 536.725 0.000 536.795 0.210 ;
    END
  END r0_rd_out[63]
  PIN r0_rd_out[64]
    DIRECTION OUTPUT ;
    USE SIGNAL ;
    SHAPE ABUTMENT ;
    PORT
      LAYER metal3 ;
      RECT 538.405 0.000 538.475 0.210 ;
    END
  END r0_rd_out[64]
  PIN r0_rd_out[65]
    DIRECTION OUTPUT ;
    USE SIGNAL ;
    SHAPE ABUTMENT ;
    PORT
      LAYER metal3 ;
      RECT 540.085 0.000 540.155 0.210 ;
    END
  END r0_rd_out[65]
  PIN r0_rd_out[66]
    DIRECTION OUTPUT ;
    USE SIGNAL ;
    SHAPE ABUTMENT ;
    PORT
      LAYER metal3 ;
      RECT 541.765 0.000 541.835 0.210 ;
    END
  END r0_rd_out[66]
  PIN r0_rd_out[67]
    DIRECTION OUTPUT ;
    USE SIGNAL ;
    SHAPE ABUTMENT ;
    PORT
      LAYER metal3 ;
      RECT 543.445 0.000 543.515 0.210 ;
    END
  END r0_rd_out[67]
  PIN r0_rd_out[68]
    DIRECTION OUTPUT ;
    USE SIGNAL ;
    SHAPE ABUTMENT ;
    PORT
      LAYER metal3 ;
      RECT 545.125 0.000 545.195 0.210 ;
    END
  END r0_rd_out[68]
  PIN r0_rd_out[69]
    DIRECTION OUTPUT ;
    USE SIGNAL ;
    SHAPE ABUTMENT ;
    PORT
      LAYER metal3 ;
      RECT 546.805 0.000 546.875 0.210 ;
    END
  END r0_rd_out[69]
  PIN r0_rd_out[70]
    DIRECTION OUTPUT ;
    USE SIGNAL ;
    SHAPE ABUTMENT ;
    PORT
      LAYER metal3 ;
      RECT 548.485 0.000 548.555 0.210 ;
    END
  END r0_rd_out[70]
  PIN r0_rd_out[71]
    DIRECTION OUTPUT ;
    USE SIGNAL ;
    SHAPE ABUTMENT ;
    PORT
      LAYER metal3 ;
      RECT 550.165 0.000 550.235 0.210 ;
    END
  END r0_rd_out[71]
  PIN r0_rd_out[72]
    DIRECTION OUTPUT ;
    USE SIGNAL ;
    SHAPE ABUTMENT ;
    PORT
      LAYER metal3 ;
      RECT 551.845 0.000 551.915 0.210 ;
    END
  END r0_rd_out[72]
  PIN r0_rd_out[73]
    DIRECTION OUTPUT ;
    USE SIGNAL ;
    SHAPE ABUTMENT ;
    PORT
      LAYER metal3 ;
      RECT 553.525 0.000 553.595 0.210 ;
    END
  END r0_rd_out[73]
  PIN r0_rd_out[74]
    DIRECTION OUTPUT ;
    USE SIGNAL ;
    SHAPE ABUTMENT ;
    PORT
      LAYER metal3 ;
      RECT 555.205 0.000 555.275 0.210 ;
    END
  END r0_rd_out[74]
  PIN r0_rd_out[75]
    DIRECTION OUTPUT ;
    USE SIGNAL ;
    SHAPE ABUTMENT ;
    PORT
      LAYER metal3 ;
      RECT 556.885 0.000 556.955 0.210 ;
    END
  END r0_rd_out[75]
  PIN r0_rd_out[76]
    DIRECTION OUTPUT ;
    USE SIGNAL ;
    SHAPE ABUTMENT ;
    PORT
      LAYER metal3 ;
      RECT 558.565 0.000 558.635 0.210 ;
    END
  END r0_rd_out[76]
  PIN r0_rd_out[77]
    DIRECTION OUTPUT ;
    USE SIGNAL ;
    SHAPE ABUTMENT ;
    PORT
      LAYER metal3 ;
      RECT 560.245 0.000 560.315 0.210 ;
    END
  END r0_rd_out[77]
  PIN r0_rd_out[78]
    DIRECTION OUTPUT ;
    USE SIGNAL ;
    SHAPE ABUTMENT ;
    PORT
      LAYER metal3 ;
      RECT 561.925 0.000 561.995 0.210 ;
    END
  END r0_rd_out[78]
  PIN r0_rd_out[79]
    DIRECTION OUTPUT ;
    USE SIGNAL ;
    SHAPE ABUTMENT ;
    PORT
      LAYER metal3 ;
      RECT 563.605 0.000 563.675 0.210 ;
    END
  END r0_rd_out[79]
  PIN r0_rd_out[80]
    DIRECTION OUTPUT ;
    USE SIGNAL ;
    SHAPE ABUTMENT ;
    PORT
      LAYER metal3 ;
      RECT 565.285 0.000 565.355 0.210 ;
    END
  END r0_rd_out[80]
  PIN r0_rd_out[81]
    DIRECTION OUTPUT ;
    USE SIGNAL ;
    SHAPE ABUTMENT ;
    PORT
      LAYER metal3 ;
      RECT 566.965 0.000 567.035 0.210 ;
    END
  END r0_rd_out[81]
  PIN r0_rd_out[82]
    DIRECTION OUTPUT ;
    USE SIGNAL ;
    SHAPE ABUTMENT ;
    PORT
      LAYER metal3 ;
      RECT 568.645 0.000 568.715 0.210 ;
    END
  END r0_rd_out[82]
  PIN r0_rd_out[83]
    DIRECTION OUTPUT ;
    USE SIGNAL ;
    SHAPE ABUTMENT ;
    PORT
      LAYER metal3 ;
      RECT 570.325 0.000 570.395 0.210 ;
    END
  END r0_rd_out[83]
  PIN r0_rd_out[84]
    DIRECTION OUTPUT ;
    USE SIGNAL ;
    SHAPE ABUTMENT ;
    PORT
      LAYER metal3 ;
      RECT 572.005 0.000 572.075 0.210 ;
    END
  END r0_rd_out[84]
  PIN r0_rd_out[85]
    DIRECTION OUTPUT ;
    USE SIGNAL ;
    SHAPE ABUTMENT ;
    PORT
      LAYER metal3 ;
      RECT 573.685 0.000 573.755 0.210 ;
    END
  END r0_rd_out[85]
  PIN r0_rd_out[86]
    DIRECTION OUTPUT ;
    USE SIGNAL ;
    SHAPE ABUTMENT ;
    PORT
      LAYER metal3 ;
      RECT 575.365 0.000 575.435 0.210 ;
    END
  END r0_rd_out[86]
  PIN r0_rd_out[87]
    DIRECTION OUTPUT ;
    USE SIGNAL ;
    SHAPE ABUTMENT ;
    PORT
      LAYER metal3 ;
      RECT 577.045 0.000 577.115 0.210 ;
    END
  END r0_rd_out[87]
  PIN r0_rd_out[88]
    DIRECTION OUTPUT ;
    USE SIGNAL ;
    SHAPE ABUTMENT ;
    PORT
      LAYER metal3 ;
      RECT 578.725 0.000 578.795 0.210 ;
    END
  END r0_rd_out[88]
  PIN r0_rd_out[89]
    DIRECTION OUTPUT ;
    USE SIGNAL ;
    SHAPE ABUTMENT ;
    PORT
      LAYER metal3 ;
      RECT 580.405 0.000 580.475 0.210 ;
    END
  END r0_rd_out[89]
  PIN r0_rd_out[90]
    DIRECTION OUTPUT ;
    USE SIGNAL ;
    SHAPE ABUTMENT ;
    PORT
      LAYER metal3 ;
      RECT 582.085 0.000 582.155 0.210 ;
    END
  END r0_rd_out[90]
  PIN r0_rd_out[91]
    DIRECTION OUTPUT ;
    USE SIGNAL ;
    SHAPE ABUTMENT ;
    PORT
      LAYER metal3 ;
      RECT 583.765 0.000 583.835 0.210 ;
    END
  END r0_rd_out[91]
  PIN r0_rd_out[92]
    DIRECTION OUTPUT ;
    USE SIGNAL ;
    SHAPE ABUTMENT ;
    PORT
      LAYER metal3 ;
      RECT 585.445 0.000 585.515 0.210 ;
    END
  END r0_rd_out[92]
  PIN r0_rd_out[93]
    DIRECTION OUTPUT ;
    USE SIGNAL ;
    SHAPE ABUTMENT ;
    PORT
      LAYER metal3 ;
      RECT 587.125 0.000 587.195 0.210 ;
    END
  END r0_rd_out[93]
  PIN r0_rd_out[94]
    DIRECTION OUTPUT ;
    USE SIGNAL ;
    SHAPE ABUTMENT ;
    PORT
      LAYER metal3 ;
      RECT 588.805 0.000 588.875 0.210 ;
    END
  END r0_rd_out[94]
  PIN r0_rd_out[95]
    DIRECTION OUTPUT ;
    USE SIGNAL ;
    SHAPE ABUTMENT ;
    PORT
      LAYER metal3 ;
      RECT 590.485 0.000 590.555 0.210 ;
    END
  END r0_rd_out[95]
  PIN r0_rd_out[96]
    DIRECTION OUTPUT ;
    USE SIGNAL ;
    SHAPE ABUTMENT ;
    PORT
      LAYER metal3 ;
      RECT 592.165 0.000 592.235 0.210 ;
    END
  END r0_rd_out[96]
  PIN r0_rd_out[97]
    DIRECTION OUTPUT ;
    USE SIGNAL ;
    SHAPE ABUTMENT ;
    PORT
      LAYER metal3 ;
      RECT 593.845 0.000 593.915 0.210 ;
    END
  END r0_rd_out[97]
  PIN r0_rd_out[98]
    DIRECTION OUTPUT ;
    USE SIGNAL ;
    SHAPE ABUTMENT ;
    PORT
      LAYER metal3 ;
      RECT 595.525 0.000 595.595 0.210 ;
    END
  END r0_rd_out[98]
  PIN r0_rd_out[99]
    DIRECTION OUTPUT ;
    USE SIGNAL ;
    SHAPE ABUTMENT ;
    PORT
      LAYER metal3 ;
      RECT 597.205 0.000 597.275 0.210 ;
    END
  END r0_rd_out[99]
  PIN r0_rd_out[100]
    DIRECTION OUTPUT ;
    USE SIGNAL ;
    SHAPE ABUTMENT ;
    PORT
      LAYER metal3 ;
      RECT 598.885 0.000 598.955 0.210 ;
    END
  END r0_rd_out[100]
  PIN r0_rd_out[101]
    DIRECTION OUTPUT ;
    USE SIGNAL ;
    SHAPE ABUTMENT ;
    PORT
      LAYER metal3 ;
      RECT 600.565 0.000 600.635 0.210 ;
    END
  END r0_rd_out[101]
  PIN r0_rd_out[102]
    DIRECTION OUTPUT ;
    USE SIGNAL ;
    SHAPE ABUTMENT ;
    PORT
      LAYER metal3 ;
      RECT 602.245 0.000 602.315 0.210 ;
    END
  END r0_rd_out[102]
  PIN r0_rd_out[103]
    DIRECTION OUTPUT ;
    USE SIGNAL ;
    SHAPE ABUTMENT ;
    PORT
      LAYER metal3 ;
      RECT 603.925 0.000 603.995 0.210 ;
    END
  END r0_rd_out[103]
  PIN r0_rd_out[104]
    DIRECTION OUTPUT ;
    USE SIGNAL ;
    SHAPE ABUTMENT ;
    PORT
      LAYER metal3 ;
      RECT 605.605 0.000 605.675 0.210 ;
    END
  END r0_rd_out[104]
  PIN r0_rd_out[105]
    DIRECTION OUTPUT ;
    USE SIGNAL ;
    SHAPE ABUTMENT ;
    PORT
      LAYER metal3 ;
      RECT 607.285 0.000 607.355 0.210 ;
    END
  END r0_rd_out[105]
  PIN r0_rd_out[106]
    DIRECTION OUTPUT ;
    USE SIGNAL ;
    SHAPE ABUTMENT ;
    PORT
      LAYER metal3 ;
      RECT 608.965 0.000 609.035 0.210 ;
    END
  END r0_rd_out[106]
  PIN r0_rd_out[107]
    DIRECTION OUTPUT ;
    USE SIGNAL ;
    SHAPE ABUTMENT ;
    PORT
      LAYER metal3 ;
      RECT 610.645 0.000 610.715 0.210 ;
    END
  END r0_rd_out[107]
  PIN r0_rd_out[108]
    DIRECTION OUTPUT ;
    USE SIGNAL ;
    SHAPE ABUTMENT ;
    PORT
      LAYER metal3 ;
      RECT 612.325 0.000 612.395 0.210 ;
    END
  END r0_rd_out[108]
  PIN r0_rd_out[109]
    DIRECTION OUTPUT ;
    USE SIGNAL ;
    SHAPE ABUTMENT ;
    PORT
      LAYER metal3 ;
      RECT 614.005 0.000 614.075 0.210 ;
    END
  END r0_rd_out[109]
  PIN r0_rd_out[110]
    DIRECTION OUTPUT ;
    USE SIGNAL ;
    SHAPE ABUTMENT ;
    PORT
      LAYER metal3 ;
      RECT 615.685 0.000 615.755 0.210 ;
    END
  END r0_rd_out[110]
  PIN r0_rd_out[111]
    DIRECTION OUTPUT ;
    USE SIGNAL ;
    SHAPE ABUTMENT ;
    PORT
      LAYER metal3 ;
      RECT 617.365 0.000 617.435 0.210 ;
    END
  END r0_rd_out[111]
  PIN r0_rd_out[112]
    DIRECTION OUTPUT ;
    USE SIGNAL ;
    SHAPE ABUTMENT ;
    PORT
      LAYER metal3 ;
      RECT 619.045 0.000 619.115 0.210 ;
    END
  END r0_rd_out[112]
  PIN r0_rd_out[113]
    DIRECTION OUTPUT ;
    USE SIGNAL ;
    SHAPE ABUTMENT ;
    PORT
      LAYER metal3 ;
      RECT 620.725 0.000 620.795 0.210 ;
    END
  END r0_rd_out[113]
  PIN r0_rd_out[114]
    DIRECTION OUTPUT ;
    USE SIGNAL ;
    SHAPE ABUTMENT ;
    PORT
      LAYER metal3 ;
      RECT 622.405 0.000 622.475 0.210 ;
    END
  END r0_rd_out[114]
  PIN r0_rd_out[115]
    DIRECTION OUTPUT ;
    USE SIGNAL ;
    SHAPE ABUTMENT ;
    PORT
      LAYER metal3 ;
      RECT 624.085 0.000 624.155 0.210 ;
    END
  END r0_rd_out[115]
  PIN r0_rd_out[116]
    DIRECTION OUTPUT ;
    USE SIGNAL ;
    SHAPE ABUTMENT ;
    PORT
      LAYER metal3 ;
      RECT 625.765 0.000 625.835 0.210 ;
    END
  END r0_rd_out[116]
  PIN r0_rd_out[117]
    DIRECTION OUTPUT ;
    USE SIGNAL ;
    SHAPE ABUTMENT ;
    PORT
      LAYER metal3 ;
      RECT 627.445 0.000 627.515 0.210 ;
    END
  END r0_rd_out[117]
  PIN r0_rd_out[118]
    DIRECTION OUTPUT ;
    USE SIGNAL ;
    SHAPE ABUTMENT ;
    PORT
      LAYER metal3 ;
      RECT 629.125 0.000 629.195 0.210 ;
    END
  END r0_rd_out[118]
  PIN r0_rd_out[119]
    DIRECTION OUTPUT ;
    USE SIGNAL ;
    SHAPE ABUTMENT ;
    PORT
      LAYER metal3 ;
      RECT 630.805 0.000 630.875 0.210 ;
    END
  END r0_rd_out[119]
  PIN r0_rd_out[120]
    DIRECTION OUTPUT ;
    USE SIGNAL ;
    SHAPE ABUTMENT ;
    PORT
      LAYER metal3 ;
      RECT 632.485 0.000 632.555 0.210 ;
    END
  END r0_rd_out[120]
  PIN r0_rd_out[121]
    DIRECTION OUTPUT ;
    USE SIGNAL ;
    SHAPE ABUTMENT ;
    PORT
      LAYER metal3 ;
      RECT 634.165 0.000 634.235 0.210 ;
    END
  END r0_rd_out[121]
  PIN r0_rd_out[122]
    DIRECTION OUTPUT ;
    USE SIGNAL ;
    SHAPE ABUTMENT ;
    PORT
      LAYER metal3 ;
      RECT 635.845 0.000 635.915 0.210 ;
    END
  END r0_rd_out[122]
  PIN r0_rd_out[123]
    DIRECTION OUTPUT ;
    USE SIGNAL ;
    SHAPE ABUTMENT ;
    PORT
      LAYER metal3 ;
      RECT 637.525 0.000 637.595 0.210 ;
    END
  END r0_rd_out[123]
  PIN r0_rd_out[124]
    DIRECTION OUTPUT ;
    USE SIGNAL ;
    SHAPE ABUTMENT ;
    PORT
      LAYER metal3 ;
      RECT 639.205 0.000 639.275 0.210 ;
    END
  END r0_rd_out[124]
  PIN r0_rd_out[125]
    DIRECTION OUTPUT ;
    USE SIGNAL ;
    SHAPE ABUTMENT ;
    PORT
      LAYER metal3 ;
      RECT 640.885 0.000 640.955 0.210 ;
    END
  END r0_rd_out[125]
  PIN r0_rd_out[126]
    DIRECTION OUTPUT ;
    USE SIGNAL ;
    SHAPE ABUTMENT ;
    PORT
      LAYER metal3 ;
      RECT 642.565 0.000 642.635 0.210 ;
    END
  END r0_rd_out[126]
  PIN r0_rd_out[127]
    DIRECTION OUTPUT ;
    USE SIGNAL ;
    SHAPE ABUTMENT ;
    PORT
      LAYER metal3 ;
      RECT 644.245 0.000 644.315 0.210 ;
    END
  END r0_rd_out[127]
  PIN r0_rd_out[128]
    DIRECTION OUTPUT ;
    USE SIGNAL ;
    SHAPE ABUTMENT ;
    PORT
      LAYER metal3 ;
      RECT 645.925 0.000 645.995 0.210 ;
    END
  END r0_rd_out[128]
  PIN r0_rd_out[129]
    DIRECTION OUTPUT ;
    USE SIGNAL ;
    SHAPE ABUTMENT ;
    PORT
      LAYER metal3 ;
      RECT 647.605 0.000 647.675 0.210 ;
    END
  END r0_rd_out[129]
  PIN r0_rd_out[130]
    DIRECTION OUTPUT ;
    USE SIGNAL ;
    SHAPE ABUTMENT ;
    PORT
      LAYER metal3 ;
      RECT 649.285 0.000 649.355 0.210 ;
    END
  END r0_rd_out[130]
  PIN r0_rd_out[131]
    DIRECTION OUTPUT ;
    USE SIGNAL ;
    SHAPE ABUTMENT ;
    PORT
      LAYER metal3 ;
      RECT 650.965 0.000 651.035 0.210 ;
    END
  END r0_rd_out[131]
  PIN r0_rd_out[132]
    DIRECTION OUTPUT ;
    USE SIGNAL ;
    SHAPE ABUTMENT ;
    PORT
      LAYER metal3 ;
      RECT 652.645 0.000 652.715 0.210 ;
    END
  END r0_rd_out[132]
  PIN r0_rd_out[133]
    DIRECTION OUTPUT ;
    USE SIGNAL ;
    SHAPE ABUTMENT ;
    PORT
      LAYER metal3 ;
      RECT 654.325 0.000 654.395 0.210 ;
    END
  END r0_rd_out[133]
  PIN r0_rd_out[134]
    DIRECTION OUTPUT ;
    USE SIGNAL ;
    SHAPE ABUTMENT ;
    PORT
      LAYER metal3 ;
      RECT 656.005 0.000 656.075 0.210 ;
    END
  END r0_rd_out[134]
  PIN r0_rd_out[135]
    DIRECTION OUTPUT ;
    USE SIGNAL ;
    SHAPE ABUTMENT ;
    PORT
      LAYER metal3 ;
      RECT 657.685 0.000 657.755 0.210 ;
    END
  END r0_rd_out[135]
  PIN r0_rd_out[136]
    DIRECTION OUTPUT ;
    USE SIGNAL ;
    SHAPE ABUTMENT ;
    PORT
      LAYER metal3 ;
      RECT 659.365 0.000 659.435 0.210 ;
    END
  END r0_rd_out[136]
  PIN r0_rd_out[137]
    DIRECTION OUTPUT ;
    USE SIGNAL ;
    SHAPE ABUTMENT ;
    PORT
      LAYER metal3 ;
      RECT 661.045 0.000 661.115 0.210 ;
    END
  END r0_rd_out[137]
  PIN r0_rd_out[138]
    DIRECTION OUTPUT ;
    USE SIGNAL ;
    SHAPE ABUTMENT ;
    PORT
      LAYER metal3 ;
      RECT 662.725 0.000 662.795 0.210 ;
    END
  END r0_rd_out[138]
  PIN r0_rd_out[139]
    DIRECTION OUTPUT ;
    USE SIGNAL ;
    SHAPE ABUTMENT ;
    PORT
      LAYER metal3 ;
      RECT 664.405 0.000 664.475 0.210 ;
    END
  END r0_rd_out[139]
  PIN r0_rd_out[140]
    DIRECTION OUTPUT ;
    USE SIGNAL ;
    SHAPE ABUTMENT ;
    PORT
      LAYER metal3 ;
      RECT 666.085 0.000 666.155 0.210 ;
    END
  END r0_rd_out[140]
  PIN r0_rd_out[141]
    DIRECTION OUTPUT ;
    USE SIGNAL ;
    SHAPE ABUTMENT ;
    PORT
      LAYER metal3 ;
      RECT 667.765 0.000 667.835 0.210 ;
    END
  END r0_rd_out[141]
  PIN r0_rd_out[142]
    DIRECTION OUTPUT ;
    USE SIGNAL ;
    SHAPE ABUTMENT ;
    PORT
      LAYER metal3 ;
      RECT 669.445 0.000 669.515 0.210 ;
    END
  END r0_rd_out[142]
  PIN r0_rd_out[143]
    DIRECTION OUTPUT ;
    USE SIGNAL ;
    SHAPE ABUTMENT ;
    PORT
      LAYER metal3 ;
      RECT 671.125 0.000 671.195 0.210 ;
    END
  END r0_rd_out[143]
  PIN r0_rd_out[144]
    DIRECTION OUTPUT ;
    USE SIGNAL ;
    SHAPE ABUTMENT ;
    PORT
      LAYER metal3 ;
      RECT 672.805 0.000 672.875 0.210 ;
    END
  END r0_rd_out[144]
  PIN r0_rd_out[145]
    DIRECTION OUTPUT ;
    USE SIGNAL ;
    SHAPE ABUTMENT ;
    PORT
      LAYER metal3 ;
      RECT 674.485 0.000 674.555 0.210 ;
    END
  END r0_rd_out[145]
  PIN r0_rd_out[146]
    DIRECTION OUTPUT ;
    USE SIGNAL ;
    SHAPE ABUTMENT ;
    PORT
      LAYER metal3 ;
      RECT 676.165 0.000 676.235 0.210 ;
    END
  END r0_rd_out[146]
  PIN r0_rd_out[147]
    DIRECTION OUTPUT ;
    USE SIGNAL ;
    SHAPE ABUTMENT ;
    PORT
      LAYER metal3 ;
      RECT 677.845 0.000 677.915 0.210 ;
    END
  END r0_rd_out[147]
  PIN r0_rd_out[148]
    DIRECTION OUTPUT ;
    USE SIGNAL ;
    SHAPE ABUTMENT ;
    PORT
      LAYER metal3 ;
      RECT 679.525 0.000 679.595 0.210 ;
    END
  END r0_rd_out[148]
  PIN r0_rd_out[149]
    DIRECTION OUTPUT ;
    USE SIGNAL ;
    SHAPE ABUTMENT ;
    PORT
      LAYER metal3 ;
      RECT 681.205 0.000 681.275 0.210 ;
    END
  END r0_rd_out[149]
  PIN r0_rd_out[150]
    DIRECTION OUTPUT ;
    USE SIGNAL ;
    SHAPE ABUTMENT ;
    PORT
      LAYER metal3 ;
      RECT 682.885 0.000 682.955 0.210 ;
    END
  END r0_rd_out[150]
  PIN r0_rd_out[151]
    DIRECTION OUTPUT ;
    USE SIGNAL ;
    SHAPE ABUTMENT ;
    PORT
      LAYER metal3 ;
      RECT 684.565 0.000 684.635 0.210 ;
    END
  END r0_rd_out[151]
  PIN r0_rd_out[152]
    DIRECTION OUTPUT ;
    USE SIGNAL ;
    SHAPE ABUTMENT ;
    PORT
      LAYER metal3 ;
      RECT 686.245 0.000 686.315 0.210 ;
    END
  END r0_rd_out[152]
  PIN r0_rd_out[153]
    DIRECTION OUTPUT ;
    USE SIGNAL ;
    SHAPE ABUTMENT ;
    PORT
      LAYER metal3 ;
      RECT 687.925 0.000 687.995 0.210 ;
    END
  END r0_rd_out[153]
  PIN r0_rd_out[154]
    DIRECTION OUTPUT ;
    USE SIGNAL ;
    SHAPE ABUTMENT ;
    PORT
      LAYER metal3 ;
      RECT 689.605 0.000 689.675 0.210 ;
    END
  END r0_rd_out[154]
  PIN r0_rd_out[155]
    DIRECTION OUTPUT ;
    USE SIGNAL ;
    SHAPE ABUTMENT ;
    PORT
      LAYER metal3 ;
      RECT 691.285 0.000 691.355 0.210 ;
    END
  END r0_rd_out[155]
  PIN r0_rd_out[156]
    DIRECTION OUTPUT ;
    USE SIGNAL ;
    SHAPE ABUTMENT ;
    PORT
      LAYER metal3 ;
      RECT 692.965 0.000 693.035 0.210 ;
    END
  END r0_rd_out[156]
  PIN r0_rd_out[157]
    DIRECTION OUTPUT ;
    USE SIGNAL ;
    SHAPE ABUTMENT ;
    PORT
      LAYER metal3 ;
      RECT 694.645 0.000 694.715 0.210 ;
    END
  END r0_rd_out[157]
  PIN r0_rd_out[158]
    DIRECTION OUTPUT ;
    USE SIGNAL ;
    SHAPE ABUTMENT ;
    PORT
      LAYER metal3 ;
      RECT 696.325 0.000 696.395 0.210 ;
    END
  END r0_rd_out[158]
  PIN r0_rd_out[159]
    DIRECTION OUTPUT ;
    USE SIGNAL ;
    SHAPE ABUTMENT ;
    PORT
      LAYER metal3 ;
      RECT 698.005 0.000 698.075 0.210 ;
    END
  END r0_rd_out[159]
  PIN r0_rd_out[160]
    DIRECTION OUTPUT ;
    USE SIGNAL ;
    SHAPE ABUTMENT ;
    PORT
      LAYER metal3 ;
      RECT 699.685 0.000 699.755 0.210 ;
    END
  END r0_rd_out[160]
  PIN r0_rd_out[161]
    DIRECTION OUTPUT ;
    USE SIGNAL ;
    SHAPE ABUTMENT ;
    PORT
      LAYER metal3 ;
      RECT 701.365 0.000 701.435 0.210 ;
    END
  END r0_rd_out[161]
  PIN r0_rd_out[162]
    DIRECTION OUTPUT ;
    USE SIGNAL ;
    SHAPE ABUTMENT ;
    PORT
      LAYER metal3 ;
      RECT 703.045 0.000 703.115 0.210 ;
    END
  END r0_rd_out[162]
  PIN r0_rd_out[163]
    DIRECTION OUTPUT ;
    USE SIGNAL ;
    SHAPE ABUTMENT ;
    PORT
      LAYER metal3 ;
      RECT 704.725 0.000 704.795 0.210 ;
    END
  END r0_rd_out[163]
  PIN r0_rd_out[164]
    DIRECTION OUTPUT ;
    USE SIGNAL ;
    SHAPE ABUTMENT ;
    PORT
      LAYER metal3 ;
      RECT 706.405 0.000 706.475 0.210 ;
    END
  END r0_rd_out[164]
  PIN r0_rd_out[165]
    DIRECTION OUTPUT ;
    USE SIGNAL ;
    SHAPE ABUTMENT ;
    PORT
      LAYER metal3 ;
      RECT 708.085 0.000 708.155 0.210 ;
    END
  END r0_rd_out[165]
  PIN r0_rd_out[166]
    DIRECTION OUTPUT ;
    USE SIGNAL ;
    SHAPE ABUTMENT ;
    PORT
      LAYER metal3 ;
      RECT 709.765 0.000 709.835 0.210 ;
    END
  END r0_rd_out[166]
  PIN r0_rd_out[167]
    DIRECTION OUTPUT ;
    USE SIGNAL ;
    SHAPE ABUTMENT ;
    PORT
      LAYER metal3 ;
      RECT 711.445 0.000 711.515 0.210 ;
    END
  END r0_rd_out[167]
  PIN r0_rd_out[168]
    DIRECTION OUTPUT ;
    USE SIGNAL ;
    SHAPE ABUTMENT ;
    PORT
      LAYER metal3 ;
      RECT 713.125 0.000 713.195 0.210 ;
    END
  END r0_rd_out[168]
  PIN r0_rd_out[169]
    DIRECTION OUTPUT ;
    USE SIGNAL ;
    SHAPE ABUTMENT ;
    PORT
      LAYER metal3 ;
      RECT 714.805 0.000 714.875 0.210 ;
    END
  END r0_rd_out[169]
  PIN r0_rd_out[170]
    DIRECTION OUTPUT ;
    USE SIGNAL ;
    SHAPE ABUTMENT ;
    PORT
      LAYER metal3 ;
      RECT 716.485 0.000 716.555 0.210 ;
    END
  END r0_rd_out[170]
  PIN r0_rd_out[171]
    DIRECTION OUTPUT ;
    USE SIGNAL ;
    SHAPE ABUTMENT ;
    PORT
      LAYER metal3 ;
      RECT 718.165 0.000 718.235 0.210 ;
    END
  END r0_rd_out[171]
  PIN r0_rd_out[172]
    DIRECTION OUTPUT ;
    USE SIGNAL ;
    SHAPE ABUTMENT ;
    PORT
      LAYER metal3 ;
      RECT 719.845 0.000 719.915 0.210 ;
    END
  END r0_rd_out[172]
  PIN r0_rd_out[173]
    DIRECTION OUTPUT ;
    USE SIGNAL ;
    SHAPE ABUTMENT ;
    PORT
      LAYER metal3 ;
      RECT 721.525 0.000 721.595 0.210 ;
    END
  END r0_rd_out[173]
  PIN r0_rd_out[174]
    DIRECTION OUTPUT ;
    USE SIGNAL ;
    SHAPE ABUTMENT ;
    PORT
      LAYER metal3 ;
      RECT 723.205 0.000 723.275 0.210 ;
    END
  END r0_rd_out[174]
  PIN r0_rd_out[175]
    DIRECTION OUTPUT ;
    USE SIGNAL ;
    SHAPE ABUTMENT ;
    PORT
      LAYER metal3 ;
      RECT 724.885 0.000 724.955 0.210 ;
    END
  END r0_rd_out[175]
  PIN r0_rd_out[176]
    DIRECTION OUTPUT ;
    USE SIGNAL ;
    SHAPE ABUTMENT ;
    PORT
      LAYER metal3 ;
      RECT 726.565 0.000 726.635 0.210 ;
    END
  END r0_rd_out[176]
  PIN r0_rd_out[177]
    DIRECTION OUTPUT ;
    USE SIGNAL ;
    SHAPE ABUTMENT ;
    PORT
      LAYER metal3 ;
      RECT 728.245 0.000 728.315 0.210 ;
    END
  END r0_rd_out[177]
  PIN r0_rd_out[178]
    DIRECTION OUTPUT ;
    USE SIGNAL ;
    SHAPE ABUTMENT ;
    PORT
      LAYER metal3 ;
      RECT 729.925 0.000 729.995 0.210 ;
    END
  END r0_rd_out[178]
  PIN r0_rd_out[179]
    DIRECTION OUTPUT ;
    USE SIGNAL ;
    SHAPE ABUTMENT ;
    PORT
      LAYER metal3 ;
      RECT 731.605 0.000 731.675 0.210 ;
    END
  END r0_rd_out[179]
  PIN r0_rd_out[180]
    DIRECTION OUTPUT ;
    USE SIGNAL ;
    SHAPE ABUTMENT ;
    PORT
      LAYER metal3 ;
      RECT 733.285 0.000 733.355 0.210 ;
    END
  END r0_rd_out[180]
  PIN r0_rd_out[181]
    DIRECTION OUTPUT ;
    USE SIGNAL ;
    SHAPE ABUTMENT ;
    PORT
      LAYER metal3 ;
      RECT 734.965 0.000 735.035 0.210 ;
    END
  END r0_rd_out[181]
  PIN r0_rd_out[182]
    DIRECTION OUTPUT ;
    USE SIGNAL ;
    SHAPE ABUTMENT ;
    PORT
      LAYER metal3 ;
      RECT 736.645 0.000 736.715 0.210 ;
    END
  END r0_rd_out[182]
  PIN r0_rd_out[183]
    DIRECTION OUTPUT ;
    USE SIGNAL ;
    SHAPE ABUTMENT ;
    PORT
      LAYER metal3 ;
      RECT 738.325 0.000 738.395 0.210 ;
    END
  END r0_rd_out[183]
  PIN r0_rd_out[184]
    DIRECTION OUTPUT ;
    USE SIGNAL ;
    SHAPE ABUTMENT ;
    PORT
      LAYER metal3 ;
      RECT 740.005 0.000 740.075 0.210 ;
    END
  END r0_rd_out[184]
  PIN r0_rd_out[185]
    DIRECTION OUTPUT ;
    USE SIGNAL ;
    SHAPE ABUTMENT ;
    PORT
      LAYER metal3 ;
      RECT 741.685 0.000 741.755 0.210 ;
    END
  END r0_rd_out[185]
  PIN r0_rd_out[186]
    DIRECTION OUTPUT ;
    USE SIGNAL ;
    SHAPE ABUTMENT ;
    PORT
      LAYER metal3 ;
      RECT 743.365 0.000 743.435 0.210 ;
    END
  END r0_rd_out[186]
  PIN r0_rd_out[187]
    DIRECTION OUTPUT ;
    USE SIGNAL ;
    SHAPE ABUTMENT ;
    PORT
      LAYER metal3 ;
      RECT 745.045 0.000 745.115 0.210 ;
    END
  END r0_rd_out[187]
  PIN r0_rd_out[188]
    DIRECTION OUTPUT ;
    USE SIGNAL ;
    SHAPE ABUTMENT ;
    PORT
      LAYER metal3 ;
      RECT 746.725 0.000 746.795 0.210 ;
    END
  END r0_rd_out[188]
  PIN r0_rd_out[189]
    DIRECTION OUTPUT ;
    USE SIGNAL ;
    SHAPE ABUTMENT ;
    PORT
      LAYER metal3 ;
      RECT 748.405 0.000 748.475 0.210 ;
    END
  END r0_rd_out[189]
  PIN r0_rd_out[190]
    DIRECTION OUTPUT ;
    USE SIGNAL ;
    SHAPE ABUTMENT ;
    PORT
      LAYER metal3 ;
      RECT 750.085 0.000 750.155 0.210 ;
    END
  END r0_rd_out[190]
  PIN r0_rd_out[191]
    DIRECTION OUTPUT ;
    USE SIGNAL ;
    SHAPE ABUTMENT ;
    PORT
      LAYER metal3 ;
      RECT 751.765 0.000 751.835 0.210 ;
    END
  END r0_rd_out[191]
  PIN r0_rd_out[192]
    DIRECTION OUTPUT ;
    USE SIGNAL ;
    SHAPE ABUTMENT ;
    PORT
      LAYER metal3 ;
      RECT 753.445 0.000 753.515 0.210 ;
    END
  END r0_rd_out[192]
  PIN r0_rd_out[193]
    DIRECTION OUTPUT ;
    USE SIGNAL ;
    SHAPE ABUTMENT ;
    PORT
      LAYER metal3 ;
      RECT 755.125 0.000 755.195 0.210 ;
    END
  END r0_rd_out[193]
  PIN r0_rd_out[194]
    DIRECTION OUTPUT ;
    USE SIGNAL ;
    SHAPE ABUTMENT ;
    PORT
      LAYER metal3 ;
      RECT 756.805 0.000 756.875 0.210 ;
    END
  END r0_rd_out[194]
  PIN r0_rd_out[195]
    DIRECTION OUTPUT ;
    USE SIGNAL ;
    SHAPE ABUTMENT ;
    PORT
      LAYER metal3 ;
      RECT 758.485 0.000 758.555 0.210 ;
    END
  END r0_rd_out[195]
  PIN r0_rd_out[196]
    DIRECTION OUTPUT ;
    USE SIGNAL ;
    SHAPE ABUTMENT ;
    PORT
      LAYER metal3 ;
      RECT 760.165 0.000 760.235 0.210 ;
    END
  END r0_rd_out[196]
  PIN r0_rd_out[197]
    DIRECTION OUTPUT ;
    USE SIGNAL ;
    SHAPE ABUTMENT ;
    PORT
      LAYER metal3 ;
      RECT 761.845 0.000 761.915 0.210 ;
    END
  END r0_rd_out[197]
  PIN r0_rd_out[198]
    DIRECTION OUTPUT ;
    USE SIGNAL ;
    SHAPE ABUTMENT ;
    PORT
      LAYER metal3 ;
      RECT 763.525 0.000 763.595 0.210 ;
    END
  END r0_rd_out[198]
  PIN r0_rd_out[199]
    DIRECTION OUTPUT ;
    USE SIGNAL ;
    SHAPE ABUTMENT ;
    PORT
      LAYER metal3 ;
      RECT 765.205 0.000 765.275 0.210 ;
    END
  END r0_rd_out[199]
  PIN r0_rd_out[200]
    DIRECTION OUTPUT ;
    USE SIGNAL ;
    SHAPE ABUTMENT ;
    PORT
      LAYER metal3 ;
      RECT 766.885 0.000 766.955 0.210 ;
    END
  END r0_rd_out[200]
  PIN r0_rd_out[201]
    DIRECTION OUTPUT ;
    USE SIGNAL ;
    SHAPE ABUTMENT ;
    PORT
      LAYER metal3 ;
      RECT 768.565 0.000 768.635 0.210 ;
    END
  END r0_rd_out[201]
  PIN r0_rd_out[202]
    DIRECTION OUTPUT ;
    USE SIGNAL ;
    SHAPE ABUTMENT ;
    PORT
      LAYER metal3 ;
      RECT 770.245 0.000 770.315 0.210 ;
    END
  END r0_rd_out[202]
  PIN r0_rd_out[203]
    DIRECTION OUTPUT ;
    USE SIGNAL ;
    SHAPE ABUTMENT ;
    PORT
      LAYER metal3 ;
      RECT 771.925 0.000 771.995 0.210 ;
    END
  END r0_rd_out[203]
  PIN r0_rd_out[204]
    DIRECTION OUTPUT ;
    USE SIGNAL ;
    SHAPE ABUTMENT ;
    PORT
      LAYER metal3 ;
      RECT 773.605 0.000 773.675 0.210 ;
    END
  END r0_rd_out[204]
  PIN r0_rd_out[205]
    DIRECTION OUTPUT ;
    USE SIGNAL ;
    SHAPE ABUTMENT ;
    PORT
      LAYER metal3 ;
      RECT 775.285 0.000 775.355 0.210 ;
    END
  END r0_rd_out[205]
  PIN r0_rd_out[206]
    DIRECTION OUTPUT ;
    USE SIGNAL ;
    SHAPE ABUTMENT ;
    PORT
      LAYER metal3 ;
      RECT 776.965 0.000 777.035 0.210 ;
    END
  END r0_rd_out[206]
  PIN r0_rd_out[207]
    DIRECTION OUTPUT ;
    USE SIGNAL ;
    SHAPE ABUTMENT ;
    PORT
      LAYER metal3 ;
      RECT 778.645 0.000 778.715 0.210 ;
    END
  END r0_rd_out[207]
  PIN r0_rd_out[208]
    DIRECTION OUTPUT ;
    USE SIGNAL ;
    SHAPE ABUTMENT ;
    PORT
      LAYER metal3 ;
      RECT 780.325 0.000 780.395 0.210 ;
    END
  END r0_rd_out[208]
  PIN r0_rd_out[209]
    DIRECTION OUTPUT ;
    USE SIGNAL ;
    SHAPE ABUTMENT ;
    PORT
      LAYER metal3 ;
      RECT 782.005 0.000 782.075 0.210 ;
    END
  END r0_rd_out[209]
  PIN r0_rd_out[210]
    DIRECTION OUTPUT ;
    USE SIGNAL ;
    SHAPE ABUTMENT ;
    PORT
      LAYER metal3 ;
      RECT 783.685 0.000 783.755 0.210 ;
    END
  END r0_rd_out[210]
  PIN r0_rd_out[211]
    DIRECTION OUTPUT ;
    USE SIGNAL ;
    SHAPE ABUTMENT ;
    PORT
      LAYER metal3 ;
      RECT 785.365 0.000 785.435 0.210 ;
    END
  END r0_rd_out[211]
  PIN r0_rd_out[212]
    DIRECTION OUTPUT ;
    USE SIGNAL ;
    SHAPE ABUTMENT ;
    PORT
      LAYER metal3 ;
      RECT 787.045 0.000 787.115 0.210 ;
    END
  END r0_rd_out[212]
  PIN r0_rd_out[213]
    DIRECTION OUTPUT ;
    USE SIGNAL ;
    SHAPE ABUTMENT ;
    PORT
      LAYER metal3 ;
      RECT 788.725 0.000 788.795 0.210 ;
    END
  END r0_rd_out[213]
  PIN r0_rd_out[214]
    DIRECTION OUTPUT ;
    USE SIGNAL ;
    SHAPE ABUTMENT ;
    PORT
      LAYER metal3 ;
      RECT 790.405 0.000 790.475 0.210 ;
    END
  END r0_rd_out[214]
  PIN r0_rd_out[215]
    DIRECTION OUTPUT ;
    USE SIGNAL ;
    SHAPE ABUTMENT ;
    PORT
      LAYER metal3 ;
      RECT 792.085 0.000 792.155 0.210 ;
    END
  END r0_rd_out[215]
  PIN r0_rd_out[216]
    DIRECTION OUTPUT ;
    USE SIGNAL ;
    SHAPE ABUTMENT ;
    PORT
      LAYER metal3 ;
      RECT 793.765 0.000 793.835 0.210 ;
    END
  END r0_rd_out[216]
  PIN r0_rd_out[217]
    DIRECTION OUTPUT ;
    USE SIGNAL ;
    SHAPE ABUTMENT ;
    PORT
      LAYER metal3 ;
      RECT 795.445 0.000 795.515 0.210 ;
    END
  END r0_rd_out[217]
  PIN r0_rd_out[218]
    DIRECTION OUTPUT ;
    USE SIGNAL ;
    SHAPE ABUTMENT ;
    PORT
      LAYER metal3 ;
      RECT 797.125 0.000 797.195 0.210 ;
    END
  END r0_rd_out[218]
  PIN r0_rd_out[219]
    DIRECTION OUTPUT ;
    USE SIGNAL ;
    SHAPE ABUTMENT ;
    PORT
      LAYER metal3 ;
      RECT 798.805 0.000 798.875 0.210 ;
    END
  END r0_rd_out[219]
  PIN r0_rd_out[220]
    DIRECTION OUTPUT ;
    USE SIGNAL ;
    SHAPE ABUTMENT ;
    PORT
      LAYER metal3 ;
      RECT 800.485 0.000 800.555 0.210 ;
    END
  END r0_rd_out[220]
  PIN r0_rd_out[221]
    DIRECTION OUTPUT ;
    USE SIGNAL ;
    SHAPE ABUTMENT ;
    PORT
      LAYER metal3 ;
      RECT 802.165 0.000 802.235 0.210 ;
    END
  END r0_rd_out[221]
  PIN r0_rd_out[222]
    DIRECTION OUTPUT ;
    USE SIGNAL ;
    SHAPE ABUTMENT ;
    PORT
      LAYER metal3 ;
      RECT 803.845 0.000 803.915 0.210 ;
    END
  END r0_rd_out[222]
  PIN r0_rd_out[223]
    DIRECTION OUTPUT ;
    USE SIGNAL ;
    SHAPE ABUTMENT ;
    PORT
      LAYER metal3 ;
      RECT 805.525 0.000 805.595 0.210 ;
    END
  END r0_rd_out[223]
  PIN r0_rd_out[224]
    DIRECTION OUTPUT ;
    USE SIGNAL ;
    SHAPE ABUTMENT ;
    PORT
      LAYER metal3 ;
      RECT 807.205 0.000 807.275 0.210 ;
    END
  END r0_rd_out[224]
  PIN r0_rd_out[225]
    DIRECTION OUTPUT ;
    USE SIGNAL ;
    SHAPE ABUTMENT ;
    PORT
      LAYER metal3 ;
      RECT 808.885 0.000 808.955 0.210 ;
    END
  END r0_rd_out[225]
  PIN r0_rd_out[226]
    DIRECTION OUTPUT ;
    USE SIGNAL ;
    SHAPE ABUTMENT ;
    PORT
      LAYER metal3 ;
      RECT 810.565 0.000 810.635 0.210 ;
    END
  END r0_rd_out[226]
  PIN r0_rd_out[227]
    DIRECTION OUTPUT ;
    USE SIGNAL ;
    SHAPE ABUTMENT ;
    PORT
      LAYER metal3 ;
      RECT 812.245 0.000 812.315 0.210 ;
    END
  END r0_rd_out[227]
  PIN r0_rd_out[228]
    DIRECTION OUTPUT ;
    USE SIGNAL ;
    SHAPE ABUTMENT ;
    PORT
      LAYER metal3 ;
      RECT 813.925 0.000 813.995 0.210 ;
    END
  END r0_rd_out[228]
  PIN r0_rd_out[229]
    DIRECTION OUTPUT ;
    USE SIGNAL ;
    SHAPE ABUTMENT ;
    PORT
      LAYER metal3 ;
      RECT 815.605 0.000 815.675 0.210 ;
    END
  END r0_rd_out[229]
  PIN r0_rd_out[230]
    DIRECTION OUTPUT ;
    USE SIGNAL ;
    SHAPE ABUTMENT ;
    PORT
      LAYER metal3 ;
      RECT 817.285 0.000 817.355 0.210 ;
    END
  END r0_rd_out[230]
  PIN r0_rd_out[231]
    DIRECTION OUTPUT ;
    USE SIGNAL ;
    SHAPE ABUTMENT ;
    PORT
      LAYER metal3 ;
      RECT 818.965 0.000 819.035 0.210 ;
    END
  END r0_rd_out[231]
  PIN r0_rd_out[232]
    DIRECTION OUTPUT ;
    USE SIGNAL ;
    SHAPE ABUTMENT ;
    PORT
      LAYER metal3 ;
      RECT 820.645 0.000 820.715 0.210 ;
    END
  END r0_rd_out[232]
  PIN r0_rd_out[233]
    DIRECTION OUTPUT ;
    USE SIGNAL ;
    SHAPE ABUTMENT ;
    PORT
      LAYER metal3 ;
      RECT 822.325 0.000 822.395 0.210 ;
    END
  END r0_rd_out[233]
  PIN r0_rd_out[234]
    DIRECTION OUTPUT ;
    USE SIGNAL ;
    SHAPE ABUTMENT ;
    PORT
      LAYER metal3 ;
      RECT 824.005 0.000 824.075 0.210 ;
    END
  END r0_rd_out[234]
  PIN r0_rd_out[235]
    DIRECTION OUTPUT ;
    USE SIGNAL ;
    SHAPE ABUTMENT ;
    PORT
      LAYER metal3 ;
      RECT 825.685 0.000 825.755 0.210 ;
    END
  END r0_rd_out[235]
  PIN r0_rd_out[236]
    DIRECTION OUTPUT ;
    USE SIGNAL ;
    SHAPE ABUTMENT ;
    PORT
      LAYER metal3 ;
      RECT 827.365 0.000 827.435 0.210 ;
    END
  END r0_rd_out[236]
  PIN r0_rd_out[237]
    DIRECTION OUTPUT ;
    USE SIGNAL ;
    SHAPE ABUTMENT ;
    PORT
      LAYER metal3 ;
      RECT 829.045 0.000 829.115 0.210 ;
    END
  END r0_rd_out[237]
  PIN r0_rd_out[238]
    DIRECTION OUTPUT ;
    USE SIGNAL ;
    SHAPE ABUTMENT ;
    PORT
      LAYER metal3 ;
      RECT 830.725 0.000 830.795 0.210 ;
    END
  END r0_rd_out[238]
  PIN r0_rd_out[239]
    DIRECTION OUTPUT ;
    USE SIGNAL ;
    SHAPE ABUTMENT ;
    PORT
      LAYER metal3 ;
      RECT 832.405 0.000 832.475 0.210 ;
    END
  END r0_rd_out[239]
  PIN r0_rd_out[240]
    DIRECTION OUTPUT ;
    USE SIGNAL ;
    SHAPE ABUTMENT ;
    PORT
      LAYER metal3 ;
      RECT 834.085 0.000 834.155 0.210 ;
    END
  END r0_rd_out[240]
  PIN r0_rd_out[241]
    DIRECTION OUTPUT ;
    USE SIGNAL ;
    SHAPE ABUTMENT ;
    PORT
      LAYER metal3 ;
      RECT 835.765 0.000 835.835 0.210 ;
    END
  END r0_rd_out[241]
  PIN r0_rd_out[242]
    DIRECTION OUTPUT ;
    USE SIGNAL ;
    SHAPE ABUTMENT ;
    PORT
      LAYER metal3 ;
      RECT 837.445 0.000 837.515 0.210 ;
    END
  END r0_rd_out[242]
  PIN r0_rd_out[243]
    DIRECTION OUTPUT ;
    USE SIGNAL ;
    SHAPE ABUTMENT ;
    PORT
      LAYER metal3 ;
      RECT 839.125 0.000 839.195 0.210 ;
    END
  END r0_rd_out[243]
  PIN r0_rd_out[244]
    DIRECTION OUTPUT ;
    USE SIGNAL ;
    SHAPE ABUTMENT ;
    PORT
      LAYER metal3 ;
      RECT 840.805 0.000 840.875 0.210 ;
    END
  END r0_rd_out[244]
  PIN r0_rd_out[245]
    DIRECTION OUTPUT ;
    USE SIGNAL ;
    SHAPE ABUTMENT ;
    PORT
      LAYER metal3 ;
      RECT 842.485 0.000 842.555 0.210 ;
    END
  END r0_rd_out[245]
  PIN r0_rd_out[246]
    DIRECTION OUTPUT ;
    USE SIGNAL ;
    SHAPE ABUTMENT ;
    PORT
      LAYER metal3 ;
      RECT 844.165 0.000 844.235 0.210 ;
    END
  END r0_rd_out[246]
  PIN r0_rd_out[247]
    DIRECTION OUTPUT ;
    USE SIGNAL ;
    SHAPE ABUTMENT ;
    PORT
      LAYER metal3 ;
      RECT 845.845 0.000 845.915 0.210 ;
    END
  END r0_rd_out[247]
  PIN r0_rd_out[248]
    DIRECTION OUTPUT ;
    USE SIGNAL ;
    SHAPE ABUTMENT ;
    PORT
      LAYER metal3 ;
      RECT 847.525 0.000 847.595 0.210 ;
    END
  END r0_rd_out[248]
  PIN r0_rd_out[249]
    DIRECTION OUTPUT ;
    USE SIGNAL ;
    SHAPE ABUTMENT ;
    PORT
      LAYER metal3 ;
      RECT 849.205 0.000 849.275 0.210 ;
    END
  END r0_rd_out[249]
  PIN r0_rd_out[250]
    DIRECTION OUTPUT ;
    USE SIGNAL ;
    SHAPE ABUTMENT ;
    PORT
      LAYER metal3 ;
      RECT 850.885 0.000 850.955 0.210 ;
    END
  END r0_rd_out[250]
  PIN r0_rd_out[251]
    DIRECTION OUTPUT ;
    USE SIGNAL ;
    SHAPE ABUTMENT ;
    PORT
      LAYER metal3 ;
      RECT 852.565 0.000 852.635 0.210 ;
    END
  END r0_rd_out[251]
  PIN r0_rd_out[252]
    DIRECTION OUTPUT ;
    USE SIGNAL ;
    SHAPE ABUTMENT ;
    PORT
      LAYER metal3 ;
      RECT 854.245 0.000 854.315 0.210 ;
    END
  END r0_rd_out[252]
  PIN r0_rd_out[253]
    DIRECTION OUTPUT ;
    USE SIGNAL ;
    SHAPE ABUTMENT ;
    PORT
      LAYER metal3 ;
      RECT 855.925 0.000 855.995 0.210 ;
    END
  END r0_rd_out[253]
  PIN r0_rd_out[254]
    DIRECTION OUTPUT ;
    USE SIGNAL ;
    SHAPE ABUTMENT ;
    PORT
      LAYER metal3 ;
      RECT 857.605 0.000 857.675 0.210 ;
    END
  END r0_rd_out[254]
  PIN r0_rd_out[255]
    DIRECTION OUTPUT ;
    USE SIGNAL ;
    SHAPE ABUTMENT ;
    PORT
      LAYER metal3 ;
      RECT 859.285 0.000 859.355 0.210 ;
    END
  END r0_rd_out[255]
  PIN r0_rd_out[256]
    DIRECTION OUTPUT ;
    USE SIGNAL ;
    SHAPE ABUTMENT ;
    PORT
      LAYER metal3 ;
      RECT 0.805 783.790 0.875 784.000 ;
    END
  END r0_rd_out[256]
  PIN r0_rd_out[257]
    DIRECTION OUTPUT ;
    USE SIGNAL ;
    SHAPE ABUTMENT ;
    PORT
      LAYER metal3 ;
      RECT 4.165 783.790 4.235 784.000 ;
    END
  END r0_rd_out[257]
  PIN r0_rd_out[258]
    DIRECTION OUTPUT ;
    USE SIGNAL ;
    SHAPE ABUTMENT ;
    PORT
      LAYER metal3 ;
      RECT 7.525 783.790 7.595 784.000 ;
    END
  END r0_rd_out[258]
  PIN r0_rd_out[259]
    DIRECTION OUTPUT ;
    USE SIGNAL ;
    SHAPE ABUTMENT ;
    PORT
      LAYER metal3 ;
      RECT 10.885 783.790 10.955 784.000 ;
    END
  END r0_rd_out[259]
  PIN r0_rd_out[260]
    DIRECTION OUTPUT ;
    USE SIGNAL ;
    SHAPE ABUTMENT ;
    PORT
      LAYER metal3 ;
      RECT 14.245 783.790 14.315 784.000 ;
    END
  END r0_rd_out[260]
  PIN r0_rd_out[261]
    DIRECTION OUTPUT ;
    USE SIGNAL ;
    SHAPE ABUTMENT ;
    PORT
      LAYER metal3 ;
      RECT 17.605 783.790 17.675 784.000 ;
    END
  END r0_rd_out[261]
  PIN r0_rd_out[262]
    DIRECTION OUTPUT ;
    USE SIGNAL ;
    SHAPE ABUTMENT ;
    PORT
      LAYER metal3 ;
      RECT 20.965 783.790 21.035 784.000 ;
    END
  END r0_rd_out[262]
  PIN r0_rd_out[263]
    DIRECTION OUTPUT ;
    USE SIGNAL ;
    SHAPE ABUTMENT ;
    PORT
      LAYER metal3 ;
      RECT 24.325 783.790 24.395 784.000 ;
    END
  END r0_rd_out[263]
  PIN r0_rd_out[264]
    DIRECTION OUTPUT ;
    USE SIGNAL ;
    SHAPE ABUTMENT ;
    PORT
      LAYER metal3 ;
      RECT 27.685 783.790 27.755 784.000 ;
    END
  END r0_rd_out[264]
  PIN r0_rd_out[265]
    DIRECTION OUTPUT ;
    USE SIGNAL ;
    SHAPE ABUTMENT ;
    PORT
      LAYER metal3 ;
      RECT 31.045 783.790 31.115 784.000 ;
    END
  END r0_rd_out[265]
  PIN r0_rd_out[266]
    DIRECTION OUTPUT ;
    USE SIGNAL ;
    SHAPE ABUTMENT ;
    PORT
      LAYER metal3 ;
      RECT 34.405 783.790 34.475 784.000 ;
    END
  END r0_rd_out[266]
  PIN r0_rd_out[267]
    DIRECTION OUTPUT ;
    USE SIGNAL ;
    SHAPE ABUTMENT ;
    PORT
      LAYER metal3 ;
      RECT 37.765 783.790 37.835 784.000 ;
    END
  END r0_rd_out[267]
  PIN r0_rd_out[268]
    DIRECTION OUTPUT ;
    USE SIGNAL ;
    SHAPE ABUTMENT ;
    PORT
      LAYER metal3 ;
      RECT 41.125 783.790 41.195 784.000 ;
    END
  END r0_rd_out[268]
  PIN r0_rd_out[269]
    DIRECTION OUTPUT ;
    USE SIGNAL ;
    SHAPE ABUTMENT ;
    PORT
      LAYER metal3 ;
      RECT 44.485 783.790 44.555 784.000 ;
    END
  END r0_rd_out[269]
  PIN r0_rd_out[270]
    DIRECTION OUTPUT ;
    USE SIGNAL ;
    SHAPE ABUTMENT ;
    PORT
      LAYER metal3 ;
      RECT 47.845 783.790 47.915 784.000 ;
    END
  END r0_rd_out[270]
  PIN r0_rd_out[271]
    DIRECTION OUTPUT ;
    USE SIGNAL ;
    SHAPE ABUTMENT ;
    PORT
      LAYER metal3 ;
      RECT 51.205 783.790 51.275 784.000 ;
    END
  END r0_rd_out[271]
  PIN r0_rd_out[272]
    DIRECTION OUTPUT ;
    USE SIGNAL ;
    SHAPE ABUTMENT ;
    PORT
      LAYER metal3 ;
      RECT 54.565 783.790 54.635 784.000 ;
    END
  END r0_rd_out[272]
  PIN r0_rd_out[273]
    DIRECTION OUTPUT ;
    USE SIGNAL ;
    SHAPE ABUTMENT ;
    PORT
      LAYER metal3 ;
      RECT 57.925 783.790 57.995 784.000 ;
    END
  END r0_rd_out[273]
  PIN r0_rd_out[274]
    DIRECTION OUTPUT ;
    USE SIGNAL ;
    SHAPE ABUTMENT ;
    PORT
      LAYER metal3 ;
      RECT 61.285 783.790 61.355 784.000 ;
    END
  END r0_rd_out[274]
  PIN r0_rd_out[275]
    DIRECTION OUTPUT ;
    USE SIGNAL ;
    SHAPE ABUTMENT ;
    PORT
      LAYER metal3 ;
      RECT 64.645 783.790 64.715 784.000 ;
    END
  END r0_rd_out[275]
  PIN r0_rd_out[276]
    DIRECTION OUTPUT ;
    USE SIGNAL ;
    SHAPE ABUTMENT ;
    PORT
      LAYER metal3 ;
      RECT 68.005 783.790 68.075 784.000 ;
    END
  END r0_rd_out[276]
  PIN r0_rd_out[277]
    DIRECTION OUTPUT ;
    USE SIGNAL ;
    SHAPE ABUTMENT ;
    PORT
      LAYER metal3 ;
      RECT 71.365 783.790 71.435 784.000 ;
    END
  END r0_rd_out[277]
  PIN r0_rd_out[278]
    DIRECTION OUTPUT ;
    USE SIGNAL ;
    SHAPE ABUTMENT ;
    PORT
      LAYER metal3 ;
      RECT 74.725 783.790 74.795 784.000 ;
    END
  END r0_rd_out[278]
  PIN r0_rd_out[279]
    DIRECTION OUTPUT ;
    USE SIGNAL ;
    SHAPE ABUTMENT ;
    PORT
      LAYER metal3 ;
      RECT 78.085 783.790 78.155 784.000 ;
    END
  END r0_rd_out[279]
  PIN r0_rd_out[280]
    DIRECTION OUTPUT ;
    USE SIGNAL ;
    SHAPE ABUTMENT ;
    PORT
      LAYER metal3 ;
      RECT 81.445 783.790 81.515 784.000 ;
    END
  END r0_rd_out[280]
  PIN r0_rd_out[281]
    DIRECTION OUTPUT ;
    USE SIGNAL ;
    SHAPE ABUTMENT ;
    PORT
      LAYER metal3 ;
      RECT 84.805 783.790 84.875 784.000 ;
    END
  END r0_rd_out[281]
  PIN r0_rd_out[282]
    DIRECTION OUTPUT ;
    USE SIGNAL ;
    SHAPE ABUTMENT ;
    PORT
      LAYER metal3 ;
      RECT 88.165 783.790 88.235 784.000 ;
    END
  END r0_rd_out[282]
  PIN r0_rd_out[283]
    DIRECTION OUTPUT ;
    USE SIGNAL ;
    SHAPE ABUTMENT ;
    PORT
      LAYER metal3 ;
      RECT 91.525 783.790 91.595 784.000 ;
    END
  END r0_rd_out[283]
  PIN r0_rd_out[284]
    DIRECTION OUTPUT ;
    USE SIGNAL ;
    SHAPE ABUTMENT ;
    PORT
      LAYER metal3 ;
      RECT 94.885 783.790 94.955 784.000 ;
    END
  END r0_rd_out[284]
  PIN r0_rd_out[285]
    DIRECTION OUTPUT ;
    USE SIGNAL ;
    SHAPE ABUTMENT ;
    PORT
      LAYER metal3 ;
      RECT 98.245 783.790 98.315 784.000 ;
    END
  END r0_rd_out[285]
  PIN r0_rd_out[286]
    DIRECTION OUTPUT ;
    USE SIGNAL ;
    SHAPE ABUTMENT ;
    PORT
      LAYER metal3 ;
      RECT 101.605 783.790 101.675 784.000 ;
    END
  END r0_rd_out[286]
  PIN r0_rd_out[287]
    DIRECTION OUTPUT ;
    USE SIGNAL ;
    SHAPE ABUTMENT ;
    PORT
      LAYER metal3 ;
      RECT 104.965 783.790 105.035 784.000 ;
    END
  END r0_rd_out[287]
  PIN r0_rd_out[288]
    DIRECTION OUTPUT ;
    USE SIGNAL ;
    SHAPE ABUTMENT ;
    PORT
      LAYER metal3 ;
      RECT 108.325 783.790 108.395 784.000 ;
    END
  END r0_rd_out[288]
  PIN r0_rd_out[289]
    DIRECTION OUTPUT ;
    USE SIGNAL ;
    SHAPE ABUTMENT ;
    PORT
      LAYER metal3 ;
      RECT 111.685 783.790 111.755 784.000 ;
    END
  END r0_rd_out[289]
  PIN r0_rd_out[290]
    DIRECTION OUTPUT ;
    USE SIGNAL ;
    SHAPE ABUTMENT ;
    PORT
      LAYER metal3 ;
      RECT 115.045 783.790 115.115 784.000 ;
    END
  END r0_rd_out[290]
  PIN r0_rd_out[291]
    DIRECTION OUTPUT ;
    USE SIGNAL ;
    SHAPE ABUTMENT ;
    PORT
      LAYER metal3 ;
      RECT 118.405 783.790 118.475 784.000 ;
    END
  END r0_rd_out[291]
  PIN r0_rd_out[292]
    DIRECTION OUTPUT ;
    USE SIGNAL ;
    SHAPE ABUTMENT ;
    PORT
      LAYER metal3 ;
      RECT 121.765 783.790 121.835 784.000 ;
    END
  END r0_rd_out[292]
  PIN r0_rd_out[293]
    DIRECTION OUTPUT ;
    USE SIGNAL ;
    SHAPE ABUTMENT ;
    PORT
      LAYER metal3 ;
      RECT 125.125 783.790 125.195 784.000 ;
    END
  END r0_rd_out[293]
  PIN r0_rd_out[294]
    DIRECTION OUTPUT ;
    USE SIGNAL ;
    SHAPE ABUTMENT ;
    PORT
      LAYER metal3 ;
      RECT 128.485 783.790 128.555 784.000 ;
    END
  END r0_rd_out[294]
  PIN r0_rd_out[295]
    DIRECTION OUTPUT ;
    USE SIGNAL ;
    SHAPE ABUTMENT ;
    PORT
      LAYER metal3 ;
      RECT 131.845 783.790 131.915 784.000 ;
    END
  END r0_rd_out[295]
  PIN r0_rd_out[296]
    DIRECTION OUTPUT ;
    USE SIGNAL ;
    SHAPE ABUTMENT ;
    PORT
      LAYER metal3 ;
      RECT 135.205 783.790 135.275 784.000 ;
    END
  END r0_rd_out[296]
  PIN r0_rd_out[297]
    DIRECTION OUTPUT ;
    USE SIGNAL ;
    SHAPE ABUTMENT ;
    PORT
      LAYER metal3 ;
      RECT 138.565 783.790 138.635 784.000 ;
    END
  END r0_rd_out[297]
  PIN r0_rd_out[298]
    DIRECTION OUTPUT ;
    USE SIGNAL ;
    SHAPE ABUTMENT ;
    PORT
      LAYER metal3 ;
      RECT 141.925 783.790 141.995 784.000 ;
    END
  END r0_rd_out[298]
  PIN r0_rd_out[299]
    DIRECTION OUTPUT ;
    USE SIGNAL ;
    SHAPE ABUTMENT ;
    PORT
      LAYER metal3 ;
      RECT 145.285 783.790 145.355 784.000 ;
    END
  END r0_rd_out[299]
  PIN r0_rd_out[300]
    DIRECTION OUTPUT ;
    USE SIGNAL ;
    SHAPE ABUTMENT ;
    PORT
      LAYER metal3 ;
      RECT 148.645 783.790 148.715 784.000 ;
    END
  END r0_rd_out[300]
  PIN r0_rd_out[301]
    DIRECTION OUTPUT ;
    USE SIGNAL ;
    SHAPE ABUTMENT ;
    PORT
      LAYER metal3 ;
      RECT 152.005 783.790 152.075 784.000 ;
    END
  END r0_rd_out[301]
  PIN r0_rd_out[302]
    DIRECTION OUTPUT ;
    USE SIGNAL ;
    SHAPE ABUTMENT ;
    PORT
      LAYER metal3 ;
      RECT 155.365 783.790 155.435 784.000 ;
    END
  END r0_rd_out[302]
  PIN r0_rd_out[303]
    DIRECTION OUTPUT ;
    USE SIGNAL ;
    SHAPE ABUTMENT ;
    PORT
      LAYER metal3 ;
      RECT 158.725 783.790 158.795 784.000 ;
    END
  END r0_rd_out[303]
  PIN r0_rd_out[304]
    DIRECTION OUTPUT ;
    USE SIGNAL ;
    SHAPE ABUTMENT ;
    PORT
      LAYER metal3 ;
      RECT 162.085 783.790 162.155 784.000 ;
    END
  END r0_rd_out[304]
  PIN r0_rd_out[305]
    DIRECTION OUTPUT ;
    USE SIGNAL ;
    SHAPE ABUTMENT ;
    PORT
      LAYER metal3 ;
      RECT 165.445 783.790 165.515 784.000 ;
    END
  END r0_rd_out[305]
  PIN r0_rd_out[306]
    DIRECTION OUTPUT ;
    USE SIGNAL ;
    SHAPE ABUTMENT ;
    PORT
      LAYER metal3 ;
      RECT 168.805 783.790 168.875 784.000 ;
    END
  END r0_rd_out[306]
  PIN r0_rd_out[307]
    DIRECTION OUTPUT ;
    USE SIGNAL ;
    SHAPE ABUTMENT ;
    PORT
      LAYER metal3 ;
      RECT 172.165 783.790 172.235 784.000 ;
    END
  END r0_rd_out[307]
  PIN r0_rd_out[308]
    DIRECTION OUTPUT ;
    USE SIGNAL ;
    SHAPE ABUTMENT ;
    PORT
      LAYER metal3 ;
      RECT 175.525 783.790 175.595 784.000 ;
    END
  END r0_rd_out[308]
  PIN r0_rd_out[309]
    DIRECTION OUTPUT ;
    USE SIGNAL ;
    SHAPE ABUTMENT ;
    PORT
      LAYER metal3 ;
      RECT 178.885 783.790 178.955 784.000 ;
    END
  END r0_rd_out[309]
  PIN r0_rd_out[310]
    DIRECTION OUTPUT ;
    USE SIGNAL ;
    SHAPE ABUTMENT ;
    PORT
      LAYER metal3 ;
      RECT 182.245 783.790 182.315 784.000 ;
    END
  END r0_rd_out[310]
  PIN r0_rd_out[311]
    DIRECTION OUTPUT ;
    USE SIGNAL ;
    SHAPE ABUTMENT ;
    PORT
      LAYER metal3 ;
      RECT 185.605 783.790 185.675 784.000 ;
    END
  END r0_rd_out[311]
  PIN r0_rd_out[312]
    DIRECTION OUTPUT ;
    USE SIGNAL ;
    SHAPE ABUTMENT ;
    PORT
      LAYER metal3 ;
      RECT 188.965 783.790 189.035 784.000 ;
    END
  END r0_rd_out[312]
  PIN r0_rd_out[313]
    DIRECTION OUTPUT ;
    USE SIGNAL ;
    SHAPE ABUTMENT ;
    PORT
      LAYER metal3 ;
      RECT 192.325 783.790 192.395 784.000 ;
    END
  END r0_rd_out[313]
  PIN r0_rd_out[314]
    DIRECTION OUTPUT ;
    USE SIGNAL ;
    SHAPE ABUTMENT ;
    PORT
      LAYER metal3 ;
      RECT 195.685 783.790 195.755 784.000 ;
    END
  END r0_rd_out[314]
  PIN r0_rd_out[315]
    DIRECTION OUTPUT ;
    USE SIGNAL ;
    SHAPE ABUTMENT ;
    PORT
      LAYER metal3 ;
      RECT 199.045 783.790 199.115 784.000 ;
    END
  END r0_rd_out[315]
  PIN r0_rd_out[316]
    DIRECTION OUTPUT ;
    USE SIGNAL ;
    SHAPE ABUTMENT ;
    PORT
      LAYER metal3 ;
      RECT 202.405 783.790 202.475 784.000 ;
    END
  END r0_rd_out[316]
  PIN r0_rd_out[317]
    DIRECTION OUTPUT ;
    USE SIGNAL ;
    SHAPE ABUTMENT ;
    PORT
      LAYER metal3 ;
      RECT 205.765 783.790 205.835 784.000 ;
    END
  END r0_rd_out[317]
  PIN r0_rd_out[318]
    DIRECTION OUTPUT ;
    USE SIGNAL ;
    SHAPE ABUTMENT ;
    PORT
      LAYER metal3 ;
      RECT 209.125 783.790 209.195 784.000 ;
    END
  END r0_rd_out[318]
  PIN r0_rd_out[319]
    DIRECTION OUTPUT ;
    USE SIGNAL ;
    SHAPE ABUTMENT ;
    PORT
      LAYER metal3 ;
      RECT 212.485 783.790 212.555 784.000 ;
    END
  END r0_rd_out[319]
  PIN r0_rd_out[320]
    DIRECTION OUTPUT ;
    USE SIGNAL ;
    SHAPE ABUTMENT ;
    PORT
      LAYER metal3 ;
      RECT 215.845 783.790 215.915 784.000 ;
    END
  END r0_rd_out[320]
  PIN r0_rd_out[321]
    DIRECTION OUTPUT ;
    USE SIGNAL ;
    SHAPE ABUTMENT ;
    PORT
      LAYER metal3 ;
      RECT 219.205 783.790 219.275 784.000 ;
    END
  END r0_rd_out[321]
  PIN r0_rd_out[322]
    DIRECTION OUTPUT ;
    USE SIGNAL ;
    SHAPE ABUTMENT ;
    PORT
      LAYER metal3 ;
      RECT 222.565 783.790 222.635 784.000 ;
    END
  END r0_rd_out[322]
  PIN r0_rd_out[323]
    DIRECTION OUTPUT ;
    USE SIGNAL ;
    SHAPE ABUTMENT ;
    PORT
      LAYER metal3 ;
      RECT 225.925 783.790 225.995 784.000 ;
    END
  END r0_rd_out[323]
  PIN r0_rd_out[324]
    DIRECTION OUTPUT ;
    USE SIGNAL ;
    SHAPE ABUTMENT ;
    PORT
      LAYER metal3 ;
      RECT 229.285 783.790 229.355 784.000 ;
    END
  END r0_rd_out[324]
  PIN r0_rd_out[325]
    DIRECTION OUTPUT ;
    USE SIGNAL ;
    SHAPE ABUTMENT ;
    PORT
      LAYER metal3 ;
      RECT 232.645 783.790 232.715 784.000 ;
    END
  END r0_rd_out[325]
  PIN r0_rd_out[326]
    DIRECTION OUTPUT ;
    USE SIGNAL ;
    SHAPE ABUTMENT ;
    PORT
      LAYER metal3 ;
      RECT 236.005 783.790 236.075 784.000 ;
    END
  END r0_rd_out[326]
  PIN r0_rd_out[327]
    DIRECTION OUTPUT ;
    USE SIGNAL ;
    SHAPE ABUTMENT ;
    PORT
      LAYER metal3 ;
      RECT 239.365 783.790 239.435 784.000 ;
    END
  END r0_rd_out[327]
  PIN r0_rd_out[328]
    DIRECTION OUTPUT ;
    USE SIGNAL ;
    SHAPE ABUTMENT ;
    PORT
      LAYER metal3 ;
      RECT 242.725 783.790 242.795 784.000 ;
    END
  END r0_rd_out[328]
  PIN r0_rd_out[329]
    DIRECTION OUTPUT ;
    USE SIGNAL ;
    SHAPE ABUTMENT ;
    PORT
      LAYER metal3 ;
      RECT 246.085 783.790 246.155 784.000 ;
    END
  END r0_rd_out[329]
  PIN r0_rd_out[330]
    DIRECTION OUTPUT ;
    USE SIGNAL ;
    SHAPE ABUTMENT ;
    PORT
      LAYER metal3 ;
      RECT 249.445 783.790 249.515 784.000 ;
    END
  END r0_rd_out[330]
  PIN r0_rd_out[331]
    DIRECTION OUTPUT ;
    USE SIGNAL ;
    SHAPE ABUTMENT ;
    PORT
      LAYER metal3 ;
      RECT 252.805 783.790 252.875 784.000 ;
    END
  END r0_rd_out[331]
  PIN r0_rd_out[332]
    DIRECTION OUTPUT ;
    USE SIGNAL ;
    SHAPE ABUTMENT ;
    PORT
      LAYER metal3 ;
      RECT 256.165 783.790 256.235 784.000 ;
    END
  END r0_rd_out[332]
  PIN r0_rd_out[333]
    DIRECTION OUTPUT ;
    USE SIGNAL ;
    SHAPE ABUTMENT ;
    PORT
      LAYER metal3 ;
      RECT 259.525 783.790 259.595 784.000 ;
    END
  END r0_rd_out[333]
  PIN r0_rd_out[334]
    DIRECTION OUTPUT ;
    USE SIGNAL ;
    SHAPE ABUTMENT ;
    PORT
      LAYER metal3 ;
      RECT 262.885 783.790 262.955 784.000 ;
    END
  END r0_rd_out[334]
  PIN r0_rd_out[335]
    DIRECTION OUTPUT ;
    USE SIGNAL ;
    SHAPE ABUTMENT ;
    PORT
      LAYER metal3 ;
      RECT 266.245 783.790 266.315 784.000 ;
    END
  END r0_rd_out[335]
  PIN r0_rd_out[336]
    DIRECTION OUTPUT ;
    USE SIGNAL ;
    SHAPE ABUTMENT ;
    PORT
      LAYER metal3 ;
      RECT 269.605 783.790 269.675 784.000 ;
    END
  END r0_rd_out[336]
  PIN r0_rd_out[337]
    DIRECTION OUTPUT ;
    USE SIGNAL ;
    SHAPE ABUTMENT ;
    PORT
      LAYER metal3 ;
      RECT 272.965 783.790 273.035 784.000 ;
    END
  END r0_rd_out[337]
  PIN r0_rd_out[338]
    DIRECTION OUTPUT ;
    USE SIGNAL ;
    SHAPE ABUTMENT ;
    PORT
      LAYER metal3 ;
      RECT 276.325 783.790 276.395 784.000 ;
    END
  END r0_rd_out[338]
  PIN r0_rd_out[339]
    DIRECTION OUTPUT ;
    USE SIGNAL ;
    SHAPE ABUTMENT ;
    PORT
      LAYER metal3 ;
      RECT 279.685 783.790 279.755 784.000 ;
    END
  END r0_rd_out[339]
  PIN r0_rd_out[340]
    DIRECTION OUTPUT ;
    USE SIGNAL ;
    SHAPE ABUTMENT ;
    PORT
      LAYER metal3 ;
      RECT 283.045 783.790 283.115 784.000 ;
    END
  END r0_rd_out[340]
  PIN r0_rd_out[341]
    DIRECTION OUTPUT ;
    USE SIGNAL ;
    SHAPE ABUTMENT ;
    PORT
      LAYER metal3 ;
      RECT 286.405 783.790 286.475 784.000 ;
    END
  END r0_rd_out[341]
  PIN r0_rd_out[342]
    DIRECTION OUTPUT ;
    USE SIGNAL ;
    SHAPE ABUTMENT ;
    PORT
      LAYER metal3 ;
      RECT 289.765 783.790 289.835 784.000 ;
    END
  END r0_rd_out[342]
  PIN r0_rd_out[343]
    DIRECTION OUTPUT ;
    USE SIGNAL ;
    SHAPE ABUTMENT ;
    PORT
      LAYER metal3 ;
      RECT 293.125 783.790 293.195 784.000 ;
    END
  END r0_rd_out[343]
  PIN r0_rd_out[344]
    DIRECTION OUTPUT ;
    USE SIGNAL ;
    SHAPE ABUTMENT ;
    PORT
      LAYER metal3 ;
      RECT 296.485 783.790 296.555 784.000 ;
    END
  END r0_rd_out[344]
  PIN r0_rd_out[345]
    DIRECTION OUTPUT ;
    USE SIGNAL ;
    SHAPE ABUTMENT ;
    PORT
      LAYER metal3 ;
      RECT 299.845 783.790 299.915 784.000 ;
    END
  END r0_rd_out[345]
  PIN r0_rd_out[346]
    DIRECTION OUTPUT ;
    USE SIGNAL ;
    SHAPE ABUTMENT ;
    PORT
      LAYER metal3 ;
      RECT 303.205 783.790 303.275 784.000 ;
    END
  END r0_rd_out[346]
  PIN r0_rd_out[347]
    DIRECTION OUTPUT ;
    USE SIGNAL ;
    SHAPE ABUTMENT ;
    PORT
      LAYER metal3 ;
      RECT 306.565 783.790 306.635 784.000 ;
    END
  END r0_rd_out[347]
  PIN r0_rd_out[348]
    DIRECTION OUTPUT ;
    USE SIGNAL ;
    SHAPE ABUTMENT ;
    PORT
      LAYER metal3 ;
      RECT 309.925 783.790 309.995 784.000 ;
    END
  END r0_rd_out[348]
  PIN r0_rd_out[349]
    DIRECTION OUTPUT ;
    USE SIGNAL ;
    SHAPE ABUTMENT ;
    PORT
      LAYER metal3 ;
      RECT 313.285 783.790 313.355 784.000 ;
    END
  END r0_rd_out[349]
  PIN r0_rd_out[350]
    DIRECTION OUTPUT ;
    USE SIGNAL ;
    SHAPE ABUTMENT ;
    PORT
      LAYER metal3 ;
      RECT 316.645 783.790 316.715 784.000 ;
    END
  END r0_rd_out[350]
  PIN r0_rd_out[351]
    DIRECTION OUTPUT ;
    USE SIGNAL ;
    SHAPE ABUTMENT ;
    PORT
      LAYER metal3 ;
      RECT 320.005 783.790 320.075 784.000 ;
    END
  END r0_rd_out[351]
  PIN r0_rd_out[352]
    DIRECTION OUTPUT ;
    USE SIGNAL ;
    SHAPE ABUTMENT ;
    PORT
      LAYER metal3 ;
      RECT 323.365 783.790 323.435 784.000 ;
    END
  END r0_rd_out[352]
  PIN r0_rd_out[353]
    DIRECTION OUTPUT ;
    USE SIGNAL ;
    SHAPE ABUTMENT ;
    PORT
      LAYER metal3 ;
      RECT 326.725 783.790 326.795 784.000 ;
    END
  END r0_rd_out[353]
  PIN r0_rd_out[354]
    DIRECTION OUTPUT ;
    USE SIGNAL ;
    SHAPE ABUTMENT ;
    PORT
      LAYER metal3 ;
      RECT 330.085 783.790 330.155 784.000 ;
    END
  END r0_rd_out[354]
  PIN r0_rd_out[355]
    DIRECTION OUTPUT ;
    USE SIGNAL ;
    SHAPE ABUTMENT ;
    PORT
      LAYER metal3 ;
      RECT 333.445 783.790 333.515 784.000 ;
    END
  END r0_rd_out[355]
  PIN r0_rd_out[356]
    DIRECTION OUTPUT ;
    USE SIGNAL ;
    SHAPE ABUTMENT ;
    PORT
      LAYER metal3 ;
      RECT 336.805 783.790 336.875 784.000 ;
    END
  END r0_rd_out[356]
  PIN r0_rd_out[357]
    DIRECTION OUTPUT ;
    USE SIGNAL ;
    SHAPE ABUTMENT ;
    PORT
      LAYER metal3 ;
      RECT 340.165 783.790 340.235 784.000 ;
    END
  END r0_rd_out[357]
  PIN r0_rd_out[358]
    DIRECTION OUTPUT ;
    USE SIGNAL ;
    SHAPE ABUTMENT ;
    PORT
      LAYER metal3 ;
      RECT 343.525 783.790 343.595 784.000 ;
    END
  END r0_rd_out[358]
  PIN r0_rd_out[359]
    DIRECTION OUTPUT ;
    USE SIGNAL ;
    SHAPE ABUTMENT ;
    PORT
      LAYER metal3 ;
      RECT 346.885 783.790 346.955 784.000 ;
    END
  END r0_rd_out[359]
  PIN r0_rd_out[360]
    DIRECTION OUTPUT ;
    USE SIGNAL ;
    SHAPE ABUTMENT ;
    PORT
      LAYER metal3 ;
      RECT 350.245 783.790 350.315 784.000 ;
    END
  END r0_rd_out[360]
  PIN r0_rd_out[361]
    DIRECTION OUTPUT ;
    USE SIGNAL ;
    SHAPE ABUTMENT ;
    PORT
      LAYER metal3 ;
      RECT 353.605 783.790 353.675 784.000 ;
    END
  END r0_rd_out[361]
  PIN r0_rd_out[362]
    DIRECTION OUTPUT ;
    USE SIGNAL ;
    SHAPE ABUTMENT ;
    PORT
      LAYER metal3 ;
      RECT 356.965 783.790 357.035 784.000 ;
    END
  END r0_rd_out[362]
  PIN r0_rd_out[363]
    DIRECTION OUTPUT ;
    USE SIGNAL ;
    SHAPE ABUTMENT ;
    PORT
      LAYER metal3 ;
      RECT 360.325 783.790 360.395 784.000 ;
    END
  END r0_rd_out[363]
  PIN r0_rd_out[364]
    DIRECTION OUTPUT ;
    USE SIGNAL ;
    SHAPE ABUTMENT ;
    PORT
      LAYER metal3 ;
      RECT 363.685 783.790 363.755 784.000 ;
    END
  END r0_rd_out[364]
  PIN r0_rd_out[365]
    DIRECTION OUTPUT ;
    USE SIGNAL ;
    SHAPE ABUTMENT ;
    PORT
      LAYER metal3 ;
      RECT 367.045 783.790 367.115 784.000 ;
    END
  END r0_rd_out[365]
  PIN r0_rd_out[366]
    DIRECTION OUTPUT ;
    USE SIGNAL ;
    SHAPE ABUTMENT ;
    PORT
      LAYER metal3 ;
      RECT 370.405 783.790 370.475 784.000 ;
    END
  END r0_rd_out[366]
  PIN r0_rd_out[367]
    DIRECTION OUTPUT ;
    USE SIGNAL ;
    SHAPE ABUTMENT ;
    PORT
      LAYER metal3 ;
      RECT 373.765 783.790 373.835 784.000 ;
    END
  END r0_rd_out[367]
  PIN r0_rd_out[368]
    DIRECTION OUTPUT ;
    USE SIGNAL ;
    SHAPE ABUTMENT ;
    PORT
      LAYER metal3 ;
      RECT 377.125 783.790 377.195 784.000 ;
    END
  END r0_rd_out[368]
  PIN r0_rd_out[369]
    DIRECTION OUTPUT ;
    USE SIGNAL ;
    SHAPE ABUTMENT ;
    PORT
      LAYER metal3 ;
      RECT 380.485 783.790 380.555 784.000 ;
    END
  END r0_rd_out[369]
  PIN r0_rd_out[370]
    DIRECTION OUTPUT ;
    USE SIGNAL ;
    SHAPE ABUTMENT ;
    PORT
      LAYER metal3 ;
      RECT 383.845 783.790 383.915 784.000 ;
    END
  END r0_rd_out[370]
  PIN r0_rd_out[371]
    DIRECTION OUTPUT ;
    USE SIGNAL ;
    SHAPE ABUTMENT ;
    PORT
      LAYER metal3 ;
      RECT 387.205 783.790 387.275 784.000 ;
    END
  END r0_rd_out[371]
  PIN r0_rd_out[372]
    DIRECTION OUTPUT ;
    USE SIGNAL ;
    SHAPE ABUTMENT ;
    PORT
      LAYER metal3 ;
      RECT 390.565 783.790 390.635 784.000 ;
    END
  END r0_rd_out[372]
  PIN r0_rd_out[373]
    DIRECTION OUTPUT ;
    USE SIGNAL ;
    SHAPE ABUTMENT ;
    PORT
      LAYER metal3 ;
      RECT 393.925 783.790 393.995 784.000 ;
    END
  END r0_rd_out[373]
  PIN r0_rd_out[374]
    DIRECTION OUTPUT ;
    USE SIGNAL ;
    SHAPE ABUTMENT ;
    PORT
      LAYER metal3 ;
      RECT 397.285 783.790 397.355 784.000 ;
    END
  END r0_rd_out[374]
  PIN r0_rd_out[375]
    DIRECTION OUTPUT ;
    USE SIGNAL ;
    SHAPE ABUTMENT ;
    PORT
      LAYER metal3 ;
      RECT 400.645 783.790 400.715 784.000 ;
    END
  END r0_rd_out[375]
  PIN r0_rd_out[376]
    DIRECTION OUTPUT ;
    USE SIGNAL ;
    SHAPE ABUTMENT ;
    PORT
      LAYER metal3 ;
      RECT 404.005 783.790 404.075 784.000 ;
    END
  END r0_rd_out[376]
  PIN r0_rd_out[377]
    DIRECTION OUTPUT ;
    USE SIGNAL ;
    SHAPE ABUTMENT ;
    PORT
      LAYER metal3 ;
      RECT 407.365 783.790 407.435 784.000 ;
    END
  END r0_rd_out[377]
  PIN r0_rd_out[378]
    DIRECTION OUTPUT ;
    USE SIGNAL ;
    SHAPE ABUTMENT ;
    PORT
      LAYER metal3 ;
      RECT 410.725 783.790 410.795 784.000 ;
    END
  END r0_rd_out[378]
  PIN r0_rd_out[379]
    DIRECTION OUTPUT ;
    USE SIGNAL ;
    SHAPE ABUTMENT ;
    PORT
      LAYER metal3 ;
      RECT 414.085 783.790 414.155 784.000 ;
    END
  END r0_rd_out[379]
  PIN r0_rd_out[380]
    DIRECTION OUTPUT ;
    USE SIGNAL ;
    SHAPE ABUTMENT ;
    PORT
      LAYER metal3 ;
      RECT 417.445 783.790 417.515 784.000 ;
    END
  END r0_rd_out[380]
  PIN r0_rd_out[381]
    DIRECTION OUTPUT ;
    USE SIGNAL ;
    SHAPE ABUTMENT ;
    PORT
      LAYER metal3 ;
      RECT 420.805 783.790 420.875 784.000 ;
    END
  END r0_rd_out[381]
  PIN r0_rd_out[382]
    DIRECTION OUTPUT ;
    USE SIGNAL ;
    SHAPE ABUTMENT ;
    PORT
      LAYER metal3 ;
      RECT 424.165 783.790 424.235 784.000 ;
    END
  END r0_rd_out[382]
  PIN r0_rd_out[383]
    DIRECTION OUTPUT ;
    USE SIGNAL ;
    SHAPE ABUTMENT ;
    PORT
      LAYER metal3 ;
      RECT 427.525 783.790 427.595 784.000 ;
    END
  END r0_rd_out[383]
  PIN r0_rd_out[384]
    DIRECTION OUTPUT ;
    USE SIGNAL ;
    SHAPE ABUTMENT ;
    PORT
      LAYER metal3 ;
      RECT 430.885 783.790 430.955 784.000 ;
    END
  END r0_rd_out[384]
  PIN r0_rd_out[385]
    DIRECTION OUTPUT ;
    USE SIGNAL ;
    SHAPE ABUTMENT ;
    PORT
      LAYER metal3 ;
      RECT 434.245 783.790 434.315 784.000 ;
    END
  END r0_rd_out[385]
  PIN r0_rd_out[386]
    DIRECTION OUTPUT ;
    USE SIGNAL ;
    SHAPE ABUTMENT ;
    PORT
      LAYER metal3 ;
      RECT 437.605 783.790 437.675 784.000 ;
    END
  END r0_rd_out[386]
  PIN r0_rd_out[387]
    DIRECTION OUTPUT ;
    USE SIGNAL ;
    SHAPE ABUTMENT ;
    PORT
      LAYER metal3 ;
      RECT 440.965 783.790 441.035 784.000 ;
    END
  END r0_rd_out[387]
  PIN r0_rd_out[388]
    DIRECTION OUTPUT ;
    USE SIGNAL ;
    SHAPE ABUTMENT ;
    PORT
      LAYER metal3 ;
      RECT 444.325 783.790 444.395 784.000 ;
    END
  END r0_rd_out[388]
  PIN r0_rd_out[389]
    DIRECTION OUTPUT ;
    USE SIGNAL ;
    SHAPE ABUTMENT ;
    PORT
      LAYER metal3 ;
      RECT 447.685 783.790 447.755 784.000 ;
    END
  END r0_rd_out[389]
  PIN r0_rd_out[390]
    DIRECTION OUTPUT ;
    USE SIGNAL ;
    SHAPE ABUTMENT ;
    PORT
      LAYER metal3 ;
      RECT 451.045 783.790 451.115 784.000 ;
    END
  END r0_rd_out[390]
  PIN r0_rd_out[391]
    DIRECTION OUTPUT ;
    USE SIGNAL ;
    SHAPE ABUTMENT ;
    PORT
      LAYER metal3 ;
      RECT 454.405 783.790 454.475 784.000 ;
    END
  END r0_rd_out[391]
  PIN r0_rd_out[392]
    DIRECTION OUTPUT ;
    USE SIGNAL ;
    SHAPE ABUTMENT ;
    PORT
      LAYER metal3 ;
      RECT 457.765 783.790 457.835 784.000 ;
    END
  END r0_rd_out[392]
  PIN r0_rd_out[393]
    DIRECTION OUTPUT ;
    USE SIGNAL ;
    SHAPE ABUTMENT ;
    PORT
      LAYER metal3 ;
      RECT 461.125 783.790 461.195 784.000 ;
    END
  END r0_rd_out[393]
  PIN r0_rd_out[394]
    DIRECTION OUTPUT ;
    USE SIGNAL ;
    SHAPE ABUTMENT ;
    PORT
      LAYER metal3 ;
      RECT 464.485 783.790 464.555 784.000 ;
    END
  END r0_rd_out[394]
  PIN r0_rd_out[395]
    DIRECTION OUTPUT ;
    USE SIGNAL ;
    SHAPE ABUTMENT ;
    PORT
      LAYER metal3 ;
      RECT 467.845 783.790 467.915 784.000 ;
    END
  END r0_rd_out[395]
  PIN r0_rd_out[396]
    DIRECTION OUTPUT ;
    USE SIGNAL ;
    SHAPE ABUTMENT ;
    PORT
      LAYER metal3 ;
      RECT 471.205 783.790 471.275 784.000 ;
    END
  END r0_rd_out[396]
  PIN r0_rd_out[397]
    DIRECTION OUTPUT ;
    USE SIGNAL ;
    SHAPE ABUTMENT ;
    PORT
      LAYER metal3 ;
      RECT 474.565 783.790 474.635 784.000 ;
    END
  END r0_rd_out[397]
  PIN r0_rd_out[398]
    DIRECTION OUTPUT ;
    USE SIGNAL ;
    SHAPE ABUTMENT ;
    PORT
      LAYER metal3 ;
      RECT 477.925 783.790 477.995 784.000 ;
    END
  END r0_rd_out[398]
  PIN r0_rd_out[399]
    DIRECTION OUTPUT ;
    USE SIGNAL ;
    SHAPE ABUTMENT ;
    PORT
      LAYER metal3 ;
      RECT 481.285 783.790 481.355 784.000 ;
    END
  END r0_rd_out[399]
  PIN r0_rd_out[400]
    DIRECTION OUTPUT ;
    USE SIGNAL ;
    SHAPE ABUTMENT ;
    PORT
      LAYER metal3 ;
      RECT 484.645 783.790 484.715 784.000 ;
    END
  END r0_rd_out[400]
  PIN r0_rd_out[401]
    DIRECTION OUTPUT ;
    USE SIGNAL ;
    SHAPE ABUTMENT ;
    PORT
      LAYER metal3 ;
      RECT 488.005 783.790 488.075 784.000 ;
    END
  END r0_rd_out[401]
  PIN r0_rd_out[402]
    DIRECTION OUTPUT ;
    USE SIGNAL ;
    SHAPE ABUTMENT ;
    PORT
      LAYER metal3 ;
      RECT 491.365 783.790 491.435 784.000 ;
    END
  END r0_rd_out[402]
  PIN r0_rd_out[403]
    DIRECTION OUTPUT ;
    USE SIGNAL ;
    SHAPE ABUTMENT ;
    PORT
      LAYER metal3 ;
      RECT 494.725 783.790 494.795 784.000 ;
    END
  END r0_rd_out[403]
  PIN r0_rd_out[404]
    DIRECTION OUTPUT ;
    USE SIGNAL ;
    SHAPE ABUTMENT ;
    PORT
      LAYER metal3 ;
      RECT 498.085 783.790 498.155 784.000 ;
    END
  END r0_rd_out[404]
  PIN r0_rd_out[405]
    DIRECTION OUTPUT ;
    USE SIGNAL ;
    SHAPE ABUTMENT ;
    PORT
      LAYER metal3 ;
      RECT 501.445 783.790 501.515 784.000 ;
    END
  END r0_rd_out[405]
  PIN r0_rd_out[406]
    DIRECTION OUTPUT ;
    USE SIGNAL ;
    SHAPE ABUTMENT ;
    PORT
      LAYER metal3 ;
      RECT 504.805 783.790 504.875 784.000 ;
    END
  END r0_rd_out[406]
  PIN r0_rd_out[407]
    DIRECTION OUTPUT ;
    USE SIGNAL ;
    SHAPE ABUTMENT ;
    PORT
      LAYER metal3 ;
      RECT 508.165 783.790 508.235 784.000 ;
    END
  END r0_rd_out[407]
  PIN r0_rd_out[408]
    DIRECTION OUTPUT ;
    USE SIGNAL ;
    SHAPE ABUTMENT ;
    PORT
      LAYER metal3 ;
      RECT 511.525 783.790 511.595 784.000 ;
    END
  END r0_rd_out[408]
  PIN r0_rd_out[409]
    DIRECTION OUTPUT ;
    USE SIGNAL ;
    SHAPE ABUTMENT ;
    PORT
      LAYER metal3 ;
      RECT 514.885 783.790 514.955 784.000 ;
    END
  END r0_rd_out[409]
  PIN r0_rd_out[410]
    DIRECTION OUTPUT ;
    USE SIGNAL ;
    SHAPE ABUTMENT ;
    PORT
      LAYER metal3 ;
      RECT 518.245 783.790 518.315 784.000 ;
    END
  END r0_rd_out[410]
  PIN r0_rd_out[411]
    DIRECTION OUTPUT ;
    USE SIGNAL ;
    SHAPE ABUTMENT ;
    PORT
      LAYER metal3 ;
      RECT 521.605 783.790 521.675 784.000 ;
    END
  END r0_rd_out[411]
  PIN r0_rd_out[412]
    DIRECTION OUTPUT ;
    USE SIGNAL ;
    SHAPE ABUTMENT ;
    PORT
      LAYER metal3 ;
      RECT 524.965 783.790 525.035 784.000 ;
    END
  END r0_rd_out[412]
  PIN r0_rd_out[413]
    DIRECTION OUTPUT ;
    USE SIGNAL ;
    SHAPE ABUTMENT ;
    PORT
      LAYER metal3 ;
      RECT 528.325 783.790 528.395 784.000 ;
    END
  END r0_rd_out[413]
  PIN r0_rd_out[414]
    DIRECTION OUTPUT ;
    USE SIGNAL ;
    SHAPE ABUTMENT ;
    PORT
      LAYER metal3 ;
      RECT 531.685 783.790 531.755 784.000 ;
    END
  END r0_rd_out[414]
  PIN r0_rd_out[415]
    DIRECTION OUTPUT ;
    USE SIGNAL ;
    SHAPE ABUTMENT ;
    PORT
      LAYER metal3 ;
      RECT 535.045 783.790 535.115 784.000 ;
    END
  END r0_rd_out[415]
  PIN r0_rd_out[416]
    DIRECTION OUTPUT ;
    USE SIGNAL ;
    SHAPE ABUTMENT ;
    PORT
      LAYER metal3 ;
      RECT 538.405 783.790 538.475 784.000 ;
    END
  END r0_rd_out[416]
  PIN r0_rd_out[417]
    DIRECTION OUTPUT ;
    USE SIGNAL ;
    SHAPE ABUTMENT ;
    PORT
      LAYER metal3 ;
      RECT 541.765 783.790 541.835 784.000 ;
    END
  END r0_rd_out[417]
  PIN r0_rd_out[418]
    DIRECTION OUTPUT ;
    USE SIGNAL ;
    SHAPE ABUTMENT ;
    PORT
      LAYER metal3 ;
      RECT 545.125 783.790 545.195 784.000 ;
    END
  END r0_rd_out[418]
  PIN r0_rd_out[419]
    DIRECTION OUTPUT ;
    USE SIGNAL ;
    SHAPE ABUTMENT ;
    PORT
      LAYER metal3 ;
      RECT 548.485 783.790 548.555 784.000 ;
    END
  END r0_rd_out[419]
  PIN r0_rd_out[420]
    DIRECTION OUTPUT ;
    USE SIGNAL ;
    SHAPE ABUTMENT ;
    PORT
      LAYER metal3 ;
      RECT 551.845 783.790 551.915 784.000 ;
    END
  END r0_rd_out[420]
  PIN r0_rd_out[421]
    DIRECTION OUTPUT ;
    USE SIGNAL ;
    SHAPE ABUTMENT ;
    PORT
      LAYER metal3 ;
      RECT 555.205 783.790 555.275 784.000 ;
    END
  END r0_rd_out[421]
  PIN r0_rd_out[422]
    DIRECTION OUTPUT ;
    USE SIGNAL ;
    SHAPE ABUTMENT ;
    PORT
      LAYER metal3 ;
      RECT 558.565 783.790 558.635 784.000 ;
    END
  END r0_rd_out[422]
  PIN r0_rd_out[423]
    DIRECTION OUTPUT ;
    USE SIGNAL ;
    SHAPE ABUTMENT ;
    PORT
      LAYER metal3 ;
      RECT 561.925 783.790 561.995 784.000 ;
    END
  END r0_rd_out[423]
  PIN r0_rd_out[424]
    DIRECTION OUTPUT ;
    USE SIGNAL ;
    SHAPE ABUTMENT ;
    PORT
      LAYER metal3 ;
      RECT 565.285 783.790 565.355 784.000 ;
    END
  END r0_rd_out[424]
  PIN r0_rd_out[425]
    DIRECTION OUTPUT ;
    USE SIGNAL ;
    SHAPE ABUTMENT ;
    PORT
      LAYER metal3 ;
      RECT 568.645 783.790 568.715 784.000 ;
    END
  END r0_rd_out[425]
  PIN r0_rd_out[426]
    DIRECTION OUTPUT ;
    USE SIGNAL ;
    SHAPE ABUTMENT ;
    PORT
      LAYER metal3 ;
      RECT 572.005 783.790 572.075 784.000 ;
    END
  END r0_rd_out[426]
  PIN r0_rd_out[427]
    DIRECTION OUTPUT ;
    USE SIGNAL ;
    SHAPE ABUTMENT ;
    PORT
      LAYER metal3 ;
      RECT 575.365 783.790 575.435 784.000 ;
    END
  END r0_rd_out[427]
  PIN r0_rd_out[428]
    DIRECTION OUTPUT ;
    USE SIGNAL ;
    SHAPE ABUTMENT ;
    PORT
      LAYER metal3 ;
      RECT 578.725 783.790 578.795 784.000 ;
    END
  END r0_rd_out[428]
  PIN r0_rd_out[429]
    DIRECTION OUTPUT ;
    USE SIGNAL ;
    SHAPE ABUTMENT ;
    PORT
      LAYER metal3 ;
      RECT 582.085 783.790 582.155 784.000 ;
    END
  END r0_rd_out[429]
  PIN r0_rd_out[430]
    DIRECTION OUTPUT ;
    USE SIGNAL ;
    SHAPE ABUTMENT ;
    PORT
      LAYER metal3 ;
      RECT 585.445 783.790 585.515 784.000 ;
    END
  END r0_rd_out[430]
  PIN r0_rd_out[431]
    DIRECTION OUTPUT ;
    USE SIGNAL ;
    SHAPE ABUTMENT ;
    PORT
      LAYER metal3 ;
      RECT 588.805 783.790 588.875 784.000 ;
    END
  END r0_rd_out[431]
  PIN r0_rd_out[432]
    DIRECTION OUTPUT ;
    USE SIGNAL ;
    SHAPE ABUTMENT ;
    PORT
      LAYER metal3 ;
      RECT 592.165 783.790 592.235 784.000 ;
    END
  END r0_rd_out[432]
  PIN r0_rd_out[433]
    DIRECTION OUTPUT ;
    USE SIGNAL ;
    SHAPE ABUTMENT ;
    PORT
      LAYER metal3 ;
      RECT 595.525 783.790 595.595 784.000 ;
    END
  END r0_rd_out[433]
  PIN r0_rd_out[434]
    DIRECTION OUTPUT ;
    USE SIGNAL ;
    SHAPE ABUTMENT ;
    PORT
      LAYER metal3 ;
      RECT 598.885 783.790 598.955 784.000 ;
    END
  END r0_rd_out[434]
  PIN r0_rd_out[435]
    DIRECTION OUTPUT ;
    USE SIGNAL ;
    SHAPE ABUTMENT ;
    PORT
      LAYER metal3 ;
      RECT 602.245 783.790 602.315 784.000 ;
    END
  END r0_rd_out[435]
  PIN r0_rd_out[436]
    DIRECTION OUTPUT ;
    USE SIGNAL ;
    SHAPE ABUTMENT ;
    PORT
      LAYER metal3 ;
      RECT 605.605 783.790 605.675 784.000 ;
    END
  END r0_rd_out[436]
  PIN r0_rd_out[437]
    DIRECTION OUTPUT ;
    USE SIGNAL ;
    SHAPE ABUTMENT ;
    PORT
      LAYER metal3 ;
      RECT 608.965 783.790 609.035 784.000 ;
    END
  END r0_rd_out[437]
  PIN r0_rd_out[438]
    DIRECTION OUTPUT ;
    USE SIGNAL ;
    SHAPE ABUTMENT ;
    PORT
      LAYER metal3 ;
      RECT 612.325 783.790 612.395 784.000 ;
    END
  END r0_rd_out[438]
  PIN r0_rd_out[439]
    DIRECTION OUTPUT ;
    USE SIGNAL ;
    SHAPE ABUTMENT ;
    PORT
      LAYER metal3 ;
      RECT 615.685 783.790 615.755 784.000 ;
    END
  END r0_rd_out[439]
  PIN r0_rd_out[440]
    DIRECTION OUTPUT ;
    USE SIGNAL ;
    SHAPE ABUTMENT ;
    PORT
      LAYER metal3 ;
      RECT 619.045 783.790 619.115 784.000 ;
    END
  END r0_rd_out[440]
  PIN r0_rd_out[441]
    DIRECTION OUTPUT ;
    USE SIGNAL ;
    SHAPE ABUTMENT ;
    PORT
      LAYER metal3 ;
      RECT 622.405 783.790 622.475 784.000 ;
    END
  END r0_rd_out[441]
  PIN r0_rd_out[442]
    DIRECTION OUTPUT ;
    USE SIGNAL ;
    SHAPE ABUTMENT ;
    PORT
      LAYER metal3 ;
      RECT 625.765 783.790 625.835 784.000 ;
    END
  END r0_rd_out[442]
  PIN r0_rd_out[443]
    DIRECTION OUTPUT ;
    USE SIGNAL ;
    SHAPE ABUTMENT ;
    PORT
      LAYER metal3 ;
      RECT 629.125 783.790 629.195 784.000 ;
    END
  END r0_rd_out[443]
  PIN r0_rd_out[444]
    DIRECTION OUTPUT ;
    USE SIGNAL ;
    SHAPE ABUTMENT ;
    PORT
      LAYER metal3 ;
      RECT 632.485 783.790 632.555 784.000 ;
    END
  END r0_rd_out[444]
  PIN r0_rd_out[445]
    DIRECTION OUTPUT ;
    USE SIGNAL ;
    SHAPE ABUTMENT ;
    PORT
      LAYER metal3 ;
      RECT 635.845 783.790 635.915 784.000 ;
    END
  END r0_rd_out[445]
  PIN r0_rd_out[446]
    DIRECTION OUTPUT ;
    USE SIGNAL ;
    SHAPE ABUTMENT ;
    PORT
      LAYER metal3 ;
      RECT 639.205 783.790 639.275 784.000 ;
    END
  END r0_rd_out[446]
  PIN r0_rd_out[447]
    DIRECTION OUTPUT ;
    USE SIGNAL ;
    SHAPE ABUTMENT ;
    PORT
      LAYER metal3 ;
      RECT 642.565 783.790 642.635 784.000 ;
    END
  END r0_rd_out[447]
  PIN r0_rd_out[448]
    DIRECTION OUTPUT ;
    USE SIGNAL ;
    SHAPE ABUTMENT ;
    PORT
      LAYER metal3 ;
      RECT 645.925 783.790 645.995 784.000 ;
    END
  END r0_rd_out[448]
  PIN r0_rd_out[449]
    DIRECTION OUTPUT ;
    USE SIGNAL ;
    SHAPE ABUTMENT ;
    PORT
      LAYER metal3 ;
      RECT 649.285 783.790 649.355 784.000 ;
    END
  END r0_rd_out[449]
  PIN r0_rd_out[450]
    DIRECTION OUTPUT ;
    USE SIGNAL ;
    SHAPE ABUTMENT ;
    PORT
      LAYER metal3 ;
      RECT 652.645 783.790 652.715 784.000 ;
    END
  END r0_rd_out[450]
  PIN r0_rd_out[451]
    DIRECTION OUTPUT ;
    USE SIGNAL ;
    SHAPE ABUTMENT ;
    PORT
      LAYER metal3 ;
      RECT 656.005 783.790 656.075 784.000 ;
    END
  END r0_rd_out[451]
  PIN r0_rd_out[452]
    DIRECTION OUTPUT ;
    USE SIGNAL ;
    SHAPE ABUTMENT ;
    PORT
      LAYER metal3 ;
      RECT 659.365 783.790 659.435 784.000 ;
    END
  END r0_rd_out[452]
  PIN r0_rd_out[453]
    DIRECTION OUTPUT ;
    USE SIGNAL ;
    SHAPE ABUTMENT ;
    PORT
      LAYER metal3 ;
      RECT 662.725 783.790 662.795 784.000 ;
    END
  END r0_rd_out[453]
  PIN r0_rd_out[454]
    DIRECTION OUTPUT ;
    USE SIGNAL ;
    SHAPE ABUTMENT ;
    PORT
      LAYER metal3 ;
      RECT 666.085 783.790 666.155 784.000 ;
    END
  END r0_rd_out[454]
  PIN r0_rd_out[455]
    DIRECTION OUTPUT ;
    USE SIGNAL ;
    SHAPE ABUTMENT ;
    PORT
      LAYER metal3 ;
      RECT 669.445 783.790 669.515 784.000 ;
    END
  END r0_rd_out[455]
  PIN r0_rd_out[456]
    DIRECTION OUTPUT ;
    USE SIGNAL ;
    SHAPE ABUTMENT ;
    PORT
      LAYER metal3 ;
      RECT 672.805 783.790 672.875 784.000 ;
    END
  END r0_rd_out[456]
  PIN r0_rd_out[457]
    DIRECTION OUTPUT ;
    USE SIGNAL ;
    SHAPE ABUTMENT ;
    PORT
      LAYER metal3 ;
      RECT 676.165 783.790 676.235 784.000 ;
    END
  END r0_rd_out[457]
  PIN r0_rd_out[458]
    DIRECTION OUTPUT ;
    USE SIGNAL ;
    SHAPE ABUTMENT ;
    PORT
      LAYER metal3 ;
      RECT 679.525 783.790 679.595 784.000 ;
    END
  END r0_rd_out[458]
  PIN r0_rd_out[459]
    DIRECTION OUTPUT ;
    USE SIGNAL ;
    SHAPE ABUTMENT ;
    PORT
      LAYER metal3 ;
      RECT 682.885 783.790 682.955 784.000 ;
    END
  END r0_rd_out[459]
  PIN r0_rd_out[460]
    DIRECTION OUTPUT ;
    USE SIGNAL ;
    SHAPE ABUTMENT ;
    PORT
      LAYER metal3 ;
      RECT 686.245 783.790 686.315 784.000 ;
    END
  END r0_rd_out[460]
  PIN r0_rd_out[461]
    DIRECTION OUTPUT ;
    USE SIGNAL ;
    SHAPE ABUTMENT ;
    PORT
      LAYER metal3 ;
      RECT 689.605 783.790 689.675 784.000 ;
    END
  END r0_rd_out[461]
  PIN r0_rd_out[462]
    DIRECTION OUTPUT ;
    USE SIGNAL ;
    SHAPE ABUTMENT ;
    PORT
      LAYER metal3 ;
      RECT 692.965 783.790 693.035 784.000 ;
    END
  END r0_rd_out[462]
  PIN r0_rd_out[463]
    DIRECTION OUTPUT ;
    USE SIGNAL ;
    SHAPE ABUTMENT ;
    PORT
      LAYER metal3 ;
      RECT 696.325 783.790 696.395 784.000 ;
    END
  END r0_rd_out[463]
  PIN r0_rd_out[464]
    DIRECTION OUTPUT ;
    USE SIGNAL ;
    SHAPE ABUTMENT ;
    PORT
      LAYER metal3 ;
      RECT 699.685 783.790 699.755 784.000 ;
    END
  END r0_rd_out[464]
  PIN r0_rd_out[465]
    DIRECTION OUTPUT ;
    USE SIGNAL ;
    SHAPE ABUTMENT ;
    PORT
      LAYER metal3 ;
      RECT 703.045 783.790 703.115 784.000 ;
    END
  END r0_rd_out[465]
  PIN r0_rd_out[466]
    DIRECTION OUTPUT ;
    USE SIGNAL ;
    SHAPE ABUTMENT ;
    PORT
      LAYER metal3 ;
      RECT 706.405 783.790 706.475 784.000 ;
    END
  END r0_rd_out[466]
  PIN r0_rd_out[467]
    DIRECTION OUTPUT ;
    USE SIGNAL ;
    SHAPE ABUTMENT ;
    PORT
      LAYER metal3 ;
      RECT 709.765 783.790 709.835 784.000 ;
    END
  END r0_rd_out[467]
  PIN r0_rd_out[468]
    DIRECTION OUTPUT ;
    USE SIGNAL ;
    SHAPE ABUTMENT ;
    PORT
      LAYER metal3 ;
      RECT 713.125 783.790 713.195 784.000 ;
    END
  END r0_rd_out[468]
  PIN r0_rd_out[469]
    DIRECTION OUTPUT ;
    USE SIGNAL ;
    SHAPE ABUTMENT ;
    PORT
      LAYER metal3 ;
      RECT 716.485 783.790 716.555 784.000 ;
    END
  END r0_rd_out[469]
  PIN r0_rd_out[470]
    DIRECTION OUTPUT ;
    USE SIGNAL ;
    SHAPE ABUTMENT ;
    PORT
      LAYER metal3 ;
      RECT 719.845 783.790 719.915 784.000 ;
    END
  END r0_rd_out[470]
  PIN r0_rd_out[471]
    DIRECTION OUTPUT ;
    USE SIGNAL ;
    SHAPE ABUTMENT ;
    PORT
      LAYER metal3 ;
      RECT 723.205 783.790 723.275 784.000 ;
    END
  END r0_rd_out[471]
  PIN r0_rd_out[472]
    DIRECTION OUTPUT ;
    USE SIGNAL ;
    SHAPE ABUTMENT ;
    PORT
      LAYER metal3 ;
      RECT 726.565 783.790 726.635 784.000 ;
    END
  END r0_rd_out[472]
  PIN r0_rd_out[473]
    DIRECTION OUTPUT ;
    USE SIGNAL ;
    SHAPE ABUTMENT ;
    PORT
      LAYER metal3 ;
      RECT 729.925 783.790 729.995 784.000 ;
    END
  END r0_rd_out[473]
  PIN r0_rd_out[474]
    DIRECTION OUTPUT ;
    USE SIGNAL ;
    SHAPE ABUTMENT ;
    PORT
      LAYER metal3 ;
      RECT 733.285 783.790 733.355 784.000 ;
    END
  END r0_rd_out[474]
  PIN r0_rd_out[475]
    DIRECTION OUTPUT ;
    USE SIGNAL ;
    SHAPE ABUTMENT ;
    PORT
      LAYER metal3 ;
      RECT 736.645 783.790 736.715 784.000 ;
    END
  END r0_rd_out[475]
  PIN r0_rd_out[476]
    DIRECTION OUTPUT ;
    USE SIGNAL ;
    SHAPE ABUTMENT ;
    PORT
      LAYER metal3 ;
      RECT 740.005 783.790 740.075 784.000 ;
    END
  END r0_rd_out[476]
  PIN r0_rd_out[477]
    DIRECTION OUTPUT ;
    USE SIGNAL ;
    SHAPE ABUTMENT ;
    PORT
      LAYER metal3 ;
      RECT 743.365 783.790 743.435 784.000 ;
    END
  END r0_rd_out[477]
  PIN r0_rd_out[478]
    DIRECTION OUTPUT ;
    USE SIGNAL ;
    SHAPE ABUTMENT ;
    PORT
      LAYER metal3 ;
      RECT 746.725 783.790 746.795 784.000 ;
    END
  END r0_rd_out[478]
  PIN r0_rd_out[479]
    DIRECTION OUTPUT ;
    USE SIGNAL ;
    SHAPE ABUTMENT ;
    PORT
      LAYER metal3 ;
      RECT 750.085 783.790 750.155 784.000 ;
    END
  END r0_rd_out[479]
  PIN r0_rd_out[480]
    DIRECTION OUTPUT ;
    USE SIGNAL ;
    SHAPE ABUTMENT ;
    PORT
      LAYER metal3 ;
      RECT 753.445 783.790 753.515 784.000 ;
    END
  END r0_rd_out[480]
  PIN r0_rd_out[481]
    DIRECTION OUTPUT ;
    USE SIGNAL ;
    SHAPE ABUTMENT ;
    PORT
      LAYER metal3 ;
      RECT 756.805 783.790 756.875 784.000 ;
    END
  END r0_rd_out[481]
  PIN r0_rd_out[482]
    DIRECTION OUTPUT ;
    USE SIGNAL ;
    SHAPE ABUTMENT ;
    PORT
      LAYER metal3 ;
      RECT 760.165 783.790 760.235 784.000 ;
    END
  END r0_rd_out[482]
  PIN r0_rd_out[483]
    DIRECTION OUTPUT ;
    USE SIGNAL ;
    SHAPE ABUTMENT ;
    PORT
      LAYER metal3 ;
      RECT 763.525 783.790 763.595 784.000 ;
    END
  END r0_rd_out[483]
  PIN r0_rd_out[484]
    DIRECTION OUTPUT ;
    USE SIGNAL ;
    SHAPE ABUTMENT ;
    PORT
      LAYER metal3 ;
      RECT 766.885 783.790 766.955 784.000 ;
    END
  END r0_rd_out[484]
  PIN r0_rd_out[485]
    DIRECTION OUTPUT ;
    USE SIGNAL ;
    SHAPE ABUTMENT ;
    PORT
      LAYER metal3 ;
      RECT 770.245 783.790 770.315 784.000 ;
    END
  END r0_rd_out[485]
  PIN r0_rd_out[486]
    DIRECTION OUTPUT ;
    USE SIGNAL ;
    SHAPE ABUTMENT ;
    PORT
      LAYER metal3 ;
      RECT 773.605 783.790 773.675 784.000 ;
    END
  END r0_rd_out[486]
  PIN r0_rd_out[487]
    DIRECTION OUTPUT ;
    USE SIGNAL ;
    SHAPE ABUTMENT ;
    PORT
      LAYER metal3 ;
      RECT 776.965 783.790 777.035 784.000 ;
    END
  END r0_rd_out[487]
  PIN r0_rd_out[488]
    DIRECTION OUTPUT ;
    USE SIGNAL ;
    SHAPE ABUTMENT ;
    PORT
      LAYER metal3 ;
      RECT 780.325 783.790 780.395 784.000 ;
    END
  END r0_rd_out[488]
  PIN r0_rd_out[489]
    DIRECTION OUTPUT ;
    USE SIGNAL ;
    SHAPE ABUTMENT ;
    PORT
      LAYER metal3 ;
      RECT 783.685 783.790 783.755 784.000 ;
    END
  END r0_rd_out[489]
  PIN r0_rd_out[490]
    DIRECTION OUTPUT ;
    USE SIGNAL ;
    SHAPE ABUTMENT ;
    PORT
      LAYER metal3 ;
      RECT 787.045 783.790 787.115 784.000 ;
    END
  END r0_rd_out[490]
  PIN r0_rd_out[491]
    DIRECTION OUTPUT ;
    USE SIGNAL ;
    SHAPE ABUTMENT ;
    PORT
      LAYER metal3 ;
      RECT 790.405 783.790 790.475 784.000 ;
    END
  END r0_rd_out[491]
  PIN r0_rd_out[492]
    DIRECTION OUTPUT ;
    USE SIGNAL ;
    SHAPE ABUTMENT ;
    PORT
      LAYER metal3 ;
      RECT 793.765 783.790 793.835 784.000 ;
    END
  END r0_rd_out[492]
  PIN r0_rd_out[493]
    DIRECTION OUTPUT ;
    USE SIGNAL ;
    SHAPE ABUTMENT ;
    PORT
      LAYER metal3 ;
      RECT 797.125 783.790 797.195 784.000 ;
    END
  END r0_rd_out[493]
  PIN r0_rd_out[494]
    DIRECTION OUTPUT ;
    USE SIGNAL ;
    SHAPE ABUTMENT ;
    PORT
      LAYER metal3 ;
      RECT 800.485 783.790 800.555 784.000 ;
    END
  END r0_rd_out[494]
  PIN r0_rd_out[495]
    DIRECTION OUTPUT ;
    USE SIGNAL ;
    SHAPE ABUTMENT ;
    PORT
      LAYER metal3 ;
      RECT 803.845 783.790 803.915 784.000 ;
    END
  END r0_rd_out[495]
  PIN r0_rd_out[496]
    DIRECTION OUTPUT ;
    USE SIGNAL ;
    SHAPE ABUTMENT ;
    PORT
      LAYER metal3 ;
      RECT 807.205 783.790 807.275 784.000 ;
    END
  END r0_rd_out[496]
  PIN r0_rd_out[497]
    DIRECTION OUTPUT ;
    USE SIGNAL ;
    SHAPE ABUTMENT ;
    PORT
      LAYER metal3 ;
      RECT 810.565 783.790 810.635 784.000 ;
    END
  END r0_rd_out[497]
  PIN r0_rd_out[498]
    DIRECTION OUTPUT ;
    USE SIGNAL ;
    SHAPE ABUTMENT ;
    PORT
      LAYER metal3 ;
      RECT 813.925 783.790 813.995 784.000 ;
    END
  END r0_rd_out[498]
  PIN r0_rd_out[499]
    DIRECTION OUTPUT ;
    USE SIGNAL ;
    SHAPE ABUTMENT ;
    PORT
      LAYER metal3 ;
      RECT 817.285 783.790 817.355 784.000 ;
    END
  END r0_rd_out[499]
  PIN r0_rd_out[500]
    DIRECTION OUTPUT ;
    USE SIGNAL ;
    SHAPE ABUTMENT ;
    PORT
      LAYER metal3 ;
      RECT 820.645 783.790 820.715 784.000 ;
    END
  END r0_rd_out[500]
  PIN r0_rd_out[501]
    DIRECTION OUTPUT ;
    USE SIGNAL ;
    SHAPE ABUTMENT ;
    PORT
      LAYER metal3 ;
      RECT 824.005 783.790 824.075 784.000 ;
    END
  END r0_rd_out[501]
  PIN r0_rd_out[502]
    DIRECTION OUTPUT ;
    USE SIGNAL ;
    SHAPE ABUTMENT ;
    PORT
      LAYER metal3 ;
      RECT 827.365 783.790 827.435 784.000 ;
    END
  END r0_rd_out[502]
  PIN r0_rd_out[503]
    DIRECTION OUTPUT ;
    USE SIGNAL ;
    SHAPE ABUTMENT ;
    PORT
      LAYER metal3 ;
      RECT 830.725 783.790 830.795 784.000 ;
    END
  END r0_rd_out[503]
  PIN r0_rd_out[504]
    DIRECTION OUTPUT ;
    USE SIGNAL ;
    SHAPE ABUTMENT ;
    PORT
      LAYER metal3 ;
      RECT 834.085 783.790 834.155 784.000 ;
    END
  END r0_rd_out[504]
  PIN r0_rd_out[505]
    DIRECTION OUTPUT ;
    USE SIGNAL ;
    SHAPE ABUTMENT ;
    PORT
      LAYER metal3 ;
      RECT 837.445 783.790 837.515 784.000 ;
    END
  END r0_rd_out[505]
  PIN r0_rd_out[506]
    DIRECTION OUTPUT ;
    USE SIGNAL ;
    SHAPE ABUTMENT ;
    PORT
      LAYER metal3 ;
      RECT 840.805 783.790 840.875 784.000 ;
    END
  END r0_rd_out[506]
  PIN r0_rd_out[507]
    DIRECTION OUTPUT ;
    USE SIGNAL ;
    SHAPE ABUTMENT ;
    PORT
      LAYER metal3 ;
      RECT 844.165 783.790 844.235 784.000 ;
    END
  END r0_rd_out[507]
  PIN r0_rd_out[508]
    DIRECTION OUTPUT ;
    USE SIGNAL ;
    SHAPE ABUTMENT ;
    PORT
      LAYER metal3 ;
      RECT 847.525 783.790 847.595 784.000 ;
    END
  END r0_rd_out[508]
  PIN r0_rd_out[509]
    DIRECTION OUTPUT ;
    USE SIGNAL ;
    SHAPE ABUTMENT ;
    PORT
      LAYER metal3 ;
      RECT 850.885 783.790 850.955 784.000 ;
    END
  END r0_rd_out[509]
  PIN r0_rd_out[510]
    DIRECTION OUTPUT ;
    USE SIGNAL ;
    SHAPE ABUTMENT ;
    PORT
      LAYER metal3 ;
      RECT 854.245 783.790 854.315 784.000 ;
    END
  END r0_rd_out[510]
  PIN r0_rd_out[511]
    DIRECTION OUTPUT ;
    USE SIGNAL ;
    SHAPE ABUTMENT ;
    PORT
      LAYER metal3 ;
      RECT 857.605 783.790 857.675 784.000 ;
    END
  END r0_rd_out[511]
  PIN w0_addr_in[0]
    DIRECTION INPUT ;
    USE SIGNAL ;
    SHAPE ABUTMENT ;
    PORT
      LAYER metal4 ;
      RECT 0.000 718.445 0.210 718.515 ;
    END
  END w0_addr_in[0]
  PIN w0_addr_in[1]
    DIRECTION INPUT ;
    USE SIGNAL ;
    SHAPE ABUTMENT ;
    PORT
      LAYER metal4 ;
      RECT 0.000 724.045 0.210 724.115 ;
    END
  END w0_addr_in[1]
  PIN w0_addr_in[2]
    DIRECTION INPUT ;
    USE SIGNAL ;
    SHAPE ABUTMENT ;
    PORT
      LAYER metal4 ;
      RECT 0.000 729.645 0.210 729.715 ;
    END
  END w0_addr_in[2]
  PIN w0_addr_in[3]
    DIRECTION INPUT ;
    USE SIGNAL ;
    SHAPE ABUTMENT ;
    PORT
      LAYER metal4 ;
      RECT 0.000 735.245 0.210 735.315 ;
    END
  END w0_addr_in[3]
  PIN w0_addr_in[4]
    DIRECTION INPUT ;
    USE SIGNAL ;
    SHAPE ABUTMENT ;
    PORT
      LAYER metal4 ;
      RECT 0.000 740.845 0.210 740.915 ;
    END
  END w0_addr_in[4]
  PIN w0_addr_in[5]
    DIRECTION INPUT ;
    USE SIGNAL ;
    SHAPE ABUTMENT ;
    PORT
      LAYER metal4 ;
      RECT 906.090 718.445 906.300 718.515 ;
    END
  END w0_addr_in[5]
  PIN w0_addr_in[6]
    DIRECTION INPUT ;
    USE SIGNAL ;
    SHAPE ABUTMENT ;
    PORT
      LAYER metal4 ;
      RECT 906.090 724.045 906.300 724.115 ;
    END
  END w0_addr_in[6]
  PIN w0_addr_in[7]
    DIRECTION INPUT ;
    USE SIGNAL ;
    SHAPE ABUTMENT ;
    PORT
      LAYER metal4 ;
      RECT 906.090 729.645 906.300 729.715 ;
    END
  END w0_addr_in[7]
  PIN w0_addr_in[8]
    DIRECTION INPUT ;
    USE SIGNAL ;
    SHAPE ABUTMENT ;
    PORT
      LAYER metal4 ;
      RECT 906.090 735.245 906.300 735.315 ;
    END
  END w0_addr_in[8]
  PIN r0_addr_in[0]
    DIRECTION INPUT ;
    USE SIGNAL ;
    SHAPE ABUTMENT ;
    PORT
      LAYER metal4 ;
      RECT 0.000 746.445 0.210 746.515 ;
    END
  END r0_addr_in[0]
  PIN r0_addr_in[1]
    DIRECTION INPUT ;
    USE SIGNAL ;
    SHAPE ABUTMENT ;
    PORT
      LAYER metal4 ;
      RECT 0.000 752.045 0.210 752.115 ;
    END
  END r0_addr_in[1]
  PIN r0_addr_in[2]
    DIRECTION INPUT ;
    USE SIGNAL ;
    SHAPE ABUTMENT ;
    PORT
      LAYER metal4 ;
      RECT 0.000 757.645 0.210 757.715 ;
    END
  END r0_addr_in[2]
  PIN r0_addr_in[3]
    DIRECTION INPUT ;
    USE SIGNAL ;
    SHAPE ABUTMENT ;
    PORT
      LAYER metal4 ;
      RECT 0.000 763.245 0.210 763.315 ;
    END
  END r0_addr_in[3]
  PIN r0_addr_in[4]
    DIRECTION INPUT ;
    USE SIGNAL ;
    SHAPE ABUTMENT ;
    PORT
      LAYER metal4 ;
      RECT 0.000 768.845 0.210 768.915 ;
    END
  END r0_addr_in[4]
  PIN r0_addr_in[5]
    DIRECTION INPUT ;
    USE SIGNAL ;
    SHAPE ABUTMENT ;
    PORT
      LAYER metal4 ;
      RECT 906.090 740.845 906.300 740.915 ;
    END
  END r0_addr_in[5]
  PIN r0_addr_in[6]
    DIRECTION INPUT ;
    USE SIGNAL ;
    SHAPE ABUTMENT ;
    PORT
      LAYER metal4 ;
      RECT 906.090 746.445 906.300 746.515 ;
    END
  END r0_addr_in[6]
  PIN r0_addr_in[7]
    DIRECTION INPUT ;
    USE SIGNAL ;
    SHAPE ABUTMENT ;
    PORT
      LAYER metal4 ;
      RECT 906.090 752.045 906.300 752.115 ;
    END
  END r0_addr_in[7]
  PIN r0_addr_in[8]
    DIRECTION INPUT ;
    USE SIGNAL ;
    SHAPE ABUTMENT ;
    PORT
      LAYER metal4 ;
      RECT 906.090 757.645 906.300 757.715 ;
    END
  END r0_addr_in[8]
  PIN w0_we_in
    DIRECTION INPUT ;
    USE SIGNAL ;
    SHAPE ABUTMENT ;
    PORT
      LAYER metal3 ;
      RECT 860.965 783.790 861.035 784.000 ;
    END
  END w0_we_in
  PIN w0_ce_in
    DIRECTION INPUT ;
    USE SIGNAL ;
    SHAPE ABUTMENT ;
    PORT
      LAYER metal3 ;
      RECT 864.325 783.790 864.395 784.000 ;
    END
  END w0_ce_in
  PIN w0_clk
    DIRECTION INPUT ;
    USE SIGNAL ;
    SHAPE ABUTMENT ;
    PORT
      LAYER metal3 ;
      RECT 867.685 783.790 867.755 784.000 ;
    END
  END w0_clk
  PIN r0_ce_in
    DIRECTION INPUT ;
    USE SIGNAL ;
    SHAPE ABUTMENT ;
    PORT
      LAYER metal3 ;
      RECT 871.045 783.790 871.115 784.000 ;
    END
  END r0_ce_in
  PIN r0_clk
    DIRECTION INPUT ;
    USE SIGNAL ;
    SHAPE ABUTMENT ;
    PORT
      LAYER metal3 ;
      RECT 874.405 783.790 874.475 784.000 ;
    END
  END r0_clk
  PIN VSS
    DIRECTION INOUT ;
    USE GROUND ;
    PORT
      LAYER metal4 ;
      RECT 0.840 1.540 905.460 1.820 ;
      RECT 0.840 6.020 905.460 6.300 ;
      RECT 0.840 10.500 905.460 10.780 ;
      RECT 0.840 14.980 905.460 15.260 ;
      RECT 0.840 19.460 905.460 19.740 ;
      RECT 0.840 23.940 905.460 24.220 ;
      RECT 0.840 28.420 905.460 28.700 ;
      RECT 0.840 32.900 905.460 33.180 ;
      RECT 0.840 37.380 905.460 37.660 ;
      RECT 0.840 41.860 905.460 42.140 ;
      RECT 0.840 46.340 905.460 46.620 ;
      RECT 0.840 50.820 905.460 51.100 ;
      RECT 0.840 55.300 905.460 55.580 ;
      RECT 0.840 59.780 905.460 60.060 ;
      RECT 0.840 64.260 905.460 64.540 ;
      RECT 0.840 68.740 905.460 69.020 ;
      RECT 0.840 73.220 905.460 73.500 ;
      RECT 0.840 77.700 905.460 77.980 ;
      RECT 0.840 82.180 905.460 82.460 ;
      RECT 0.840 86.660 905.460 86.940 ;
      RECT 0.840 91.140 905.460 91.420 ;
      RECT 0.840 95.620 905.460 95.900 ;
      RECT 0.840 100.100 905.460 100.380 ;
      RECT 0.840 104.580 905.460 104.860 ;
      RECT 0.840 109.060 905.460 109.340 ;
      RECT 0.840 113.540 905.460 113.820 ;
      RECT 0.840 118.020 905.460 118.300 ;
      RECT 0.840 122.500 905.460 122.780 ;
      RECT 0.840 126.980 905.460 127.260 ;
      RECT 0.840 131.460 905.460 131.740 ;
      RECT 0.840 135.940 905.460 136.220 ;
      RECT 0.840 140.420 905.460 140.700 ;
      RECT 0.840 144.900 905.460 145.180 ;
      RECT 0.840 149.380 905.460 149.660 ;
      RECT 0.840 153.860 905.460 154.140 ;
      RECT 0.840 158.340 905.460 158.620 ;
      RECT 0.840 162.820 905.460 163.100 ;
      RECT 0.840 167.300 905.460 167.580 ;
      RECT 0.840 171.780 905.460 172.060 ;
      RECT 0.840 176.260 905.460 176.540 ;
      RECT 0.840 180.740 905.460 181.020 ;
      RECT 0.840 185.220 905.460 185.500 ;
      RECT 0.840 189.700 905.460 189.980 ;
      RECT 0.840 194.180 905.460 194.460 ;
      RECT 0.840 198.660 905.460 198.940 ;
      RECT 0.840 203.140 905.460 203.420 ;
      RECT 0.840 207.620 905.460 207.900 ;
      RECT 0.840 212.100 905.460 212.380 ;
      RECT 0.840 216.580 905.460 216.860 ;
      RECT 0.840 221.060 905.460 221.340 ;
      RECT 0.840 225.540 905.460 225.820 ;
      RECT 0.840 230.020 905.460 230.300 ;
      RECT 0.840 234.500 905.460 234.780 ;
      RECT 0.840 238.980 905.460 239.260 ;
      RECT 0.840 243.460 905.460 243.740 ;
      RECT 0.840 247.940 905.460 248.220 ;
      RECT 0.840 252.420 905.460 252.700 ;
      RECT 0.840 256.900 905.460 257.180 ;
      RECT 0.840 261.380 905.460 261.660 ;
      RECT 0.840 265.860 905.460 266.140 ;
      RECT 0.840 270.340 905.460 270.620 ;
      RECT 0.840 274.820 905.460 275.100 ;
      RECT 0.840 279.300 905.460 279.580 ;
      RECT 0.840 283.780 905.460 284.060 ;
      RECT 0.840 288.260 905.460 288.540 ;
      RECT 0.840 292.740 905.460 293.020 ;
      RECT 0.840 297.220 905.460 297.500 ;
      RECT 0.840 301.700 905.460 301.980 ;
      RECT 0.840 306.180 905.460 306.460 ;
      RECT 0.840 310.660 905.460 310.940 ;
      RECT 0.840 315.140 905.460 315.420 ;
      RECT 0.840 319.620 905.460 319.900 ;
      RECT 0.840 324.100 905.460 324.380 ;
      RECT 0.840 328.580 905.460 328.860 ;
      RECT 0.840 333.060 905.460 333.340 ;
      RECT 0.840 337.540 905.460 337.820 ;
      RECT 0.840 342.020 905.460 342.300 ;
      RECT 0.840 346.500 905.460 346.780 ;
      RECT 0.840 350.980 905.460 351.260 ;
      RECT 0.840 355.460 905.460 355.740 ;
      RECT 0.840 359.940 905.460 360.220 ;
      RECT 0.840 364.420 905.460 364.700 ;
      RECT 0.840 368.900 905.460 369.180 ;
      RECT 0.840 373.380 905.460 373.660 ;
      RECT 0.840 377.860 905.460 378.140 ;
      RECT 0.840 382.340 905.460 382.620 ;
      RECT 0.840 386.820 905.460 387.100 ;
      RECT 0.840 391.300 905.460 391.580 ;
      RECT 0.840 395.780 905.460 396.060 ;
      RECT 0.840 400.260 905.460 400.540 ;
      RECT 0.840 404.740 905.460 405.020 ;
      RECT 0.840 409.220 905.460 409.500 ;
      RECT 0.840 413.700 905.460 413.980 ;
      RECT 0.840 418.180 905.460 418.460 ;
      RECT 0.840 422.660 905.460 422.940 ;
      RECT 0.840 427.140 905.460 427.420 ;
      RECT 0.840 431.620 905.460 431.900 ;
      RECT 0.840 436.100 905.460 436.380 ;
      RECT 0.840 440.580 905.460 440.860 ;
      RECT 0.840 445.060 905.460 445.340 ;
      RECT 0.840 449.540 905.460 449.820 ;
      RECT 0.840 454.020 905.460 454.300 ;
      RECT 0.840 458.500 905.460 458.780 ;
      RECT 0.840 462.980 905.460 463.260 ;
      RECT 0.840 467.460 905.460 467.740 ;
      RECT 0.840 471.940 905.460 472.220 ;
      RECT 0.840 476.420 905.460 476.700 ;
      RECT 0.840 480.900 905.460 481.180 ;
      RECT 0.840 485.380 905.460 485.660 ;
      RECT 0.840 489.860 905.460 490.140 ;
      RECT 0.840 494.340 905.460 494.620 ;
      RECT 0.840 498.820 905.460 499.100 ;
      RECT 0.840 503.300 905.460 503.580 ;
      RECT 0.840 507.780 905.460 508.060 ;
      RECT 0.840 512.260 905.460 512.540 ;
      RECT 0.840 516.740 905.460 517.020 ;
      RECT 0.840 521.220 905.460 521.500 ;
      RECT 0.840 525.700 905.460 525.980 ;
      RECT 0.840 530.180 905.460 530.460 ;
      RECT 0.840 534.660 905.460 534.940 ;
      RECT 0.840 539.140 905.460 539.420 ;
      RECT 0.840 543.620 905.460 543.900 ;
      RECT 0.840 548.100 905.460 548.380 ;
      RECT 0.840 552.580 905.460 552.860 ;
      RECT 0.840 557.060 905.460 557.340 ;
      RECT 0.840 561.540 905.460 561.820 ;
      RECT 0.840 566.020 905.460 566.300 ;
      RECT 0.840 570.500 905.460 570.780 ;
      RECT 0.840 574.980 905.460 575.260 ;
      RECT 0.840 579.460 905.460 579.740 ;
      RECT 0.840 583.940 905.460 584.220 ;
      RECT 0.840 588.420 905.460 588.700 ;
      RECT 0.840 592.900 905.460 593.180 ;
      RECT 0.840 597.380 905.460 597.660 ;
      RECT 0.840 601.860 905.460 602.140 ;
      RECT 0.840 606.340 905.460 606.620 ;
      RECT 0.840 610.820 905.460 611.100 ;
      RECT 0.840 615.300 905.460 615.580 ;
      RECT 0.840 619.780 905.460 620.060 ;
      RECT 0.840 624.260 905.460 624.540 ;
      RECT 0.840 628.740 905.460 629.020 ;
      RECT 0.840 633.220 905.460 633.500 ;
      RECT 0.840 637.700 905.460 637.980 ;
      RECT 0.840 642.180 905.460 642.460 ;
      RECT 0.840 646.660 905.460 646.940 ;
      RECT 0.840 651.140 905.460 651.420 ;
      RECT 0.840 655.620 905.460 655.900 ;
      RECT 0.840 660.100 905.460 660.380 ;
      RECT 0.840 664.580 905.460 664.860 ;
      RECT 0.840 669.060 905.460 669.340 ;
      RECT 0.840 673.540 905.460 673.820 ;
      RECT 0.840 678.020 905.460 678.300 ;
      RECT 0.840 682.500 905.460 682.780 ;
      RECT 0.840 686.980 905.460 687.260 ;
      RECT 0.840 691.460 905.460 691.740 ;
      RECT 0.840 695.940 905.460 696.220 ;
      RECT 0.840 700.420 905.460 700.700 ;
      RECT 0.840 704.900 905.460 705.180 ;
      RECT 0.840 709.380 905.460 709.660 ;
      RECT 0.840 713.860 905.460 714.140 ;
      RECT 0.840 718.340 905.460 718.620 ;
      RECT 0.840 722.820 905.460 723.100 ;
      RECT 0.840 727.300 905.460 727.580 ;
      RECT 0.840 731.780 905.460 732.060 ;
      RECT 0.840 736.260 905.460 736.540 ;
      RECT 0.840 740.740 905.460 741.020 ;
      RECT 0.840 745.220 905.460 745.500 ;
      RECT 0.840 749.700 905.460 749.980 ;
      RECT 0.840 754.180 905.460 754.460 ;
      RECT 0.840 758.660 905.460 758.940 ;
      RECT 0.840 763.140 905.460 763.420 ;
      RECT 0.840 767.620 905.460 767.900 ;
      RECT 0.840 772.100 905.460 772.380 ;
      RECT 0.840 776.580 905.460 776.860 ;
      RECT 0.840 781.060 905.460 781.340 ;
    END
  END VSS
  PIN VDD
    DIRECTION INOUT ;
    USE POWER ;
    PORT
      LAYER metal4 ;
      RECT 0.840 1.540 905.460 1.820 ;
      RECT 0.840 6.020 905.460 6.300 ;
      RECT 0.840 10.500 905.460 10.780 ;
      RECT 0.840 14.980 905.460 15.260 ;
      RECT 0.840 19.460 905.460 19.740 ;
      RECT 0.840 23.940 905.460 24.220 ;
      RECT 0.840 28.420 905.460 28.700 ;
      RECT 0.840 32.900 905.460 33.180 ;
      RECT 0.840 37.380 905.460 37.660 ;
      RECT 0.840 41.860 905.460 42.140 ;
      RECT 0.840 46.340 905.460 46.620 ;
      RECT 0.840 50.820 905.460 51.100 ;
      RECT 0.840 55.300 905.460 55.580 ;
      RECT 0.840 59.780 905.460 60.060 ;
      RECT 0.840 64.260 905.460 64.540 ;
      RECT 0.840 68.740 905.460 69.020 ;
      RECT 0.840 73.220 905.460 73.500 ;
      RECT 0.840 77.700 905.460 77.980 ;
      RECT 0.840 82.180 905.460 82.460 ;
      RECT 0.840 86.660 905.460 86.940 ;
      RECT 0.840 91.140 905.460 91.420 ;
      RECT 0.840 95.620 905.460 95.900 ;
      RECT 0.840 100.100 905.460 100.380 ;
      RECT 0.840 104.580 905.460 104.860 ;
      RECT 0.840 109.060 905.460 109.340 ;
      RECT 0.840 113.540 905.460 113.820 ;
      RECT 0.840 118.020 905.460 118.300 ;
      RECT 0.840 122.500 905.460 122.780 ;
      RECT 0.840 126.980 905.460 127.260 ;
      RECT 0.840 131.460 905.460 131.740 ;
      RECT 0.840 135.940 905.460 136.220 ;
      RECT 0.840 140.420 905.460 140.700 ;
      RECT 0.840 144.900 905.460 145.180 ;
      RECT 0.840 149.380 905.460 149.660 ;
      RECT 0.840 153.860 905.460 154.140 ;
      RECT 0.840 158.340 905.460 158.620 ;
      RECT 0.840 162.820 905.460 163.100 ;
      RECT 0.840 167.300 905.460 167.580 ;
      RECT 0.840 171.780 905.460 172.060 ;
      RECT 0.840 176.260 905.460 176.540 ;
      RECT 0.840 180.740 905.460 181.020 ;
      RECT 0.840 185.220 905.460 185.500 ;
      RECT 0.840 189.700 905.460 189.980 ;
      RECT 0.840 194.180 905.460 194.460 ;
      RECT 0.840 198.660 905.460 198.940 ;
      RECT 0.840 203.140 905.460 203.420 ;
      RECT 0.840 207.620 905.460 207.900 ;
      RECT 0.840 212.100 905.460 212.380 ;
      RECT 0.840 216.580 905.460 216.860 ;
      RECT 0.840 221.060 905.460 221.340 ;
      RECT 0.840 225.540 905.460 225.820 ;
      RECT 0.840 230.020 905.460 230.300 ;
      RECT 0.840 234.500 905.460 234.780 ;
      RECT 0.840 238.980 905.460 239.260 ;
      RECT 0.840 243.460 905.460 243.740 ;
      RECT 0.840 247.940 905.460 248.220 ;
      RECT 0.840 252.420 905.460 252.700 ;
      RECT 0.840 256.900 905.460 257.180 ;
      RECT 0.840 261.380 905.460 261.660 ;
      RECT 0.840 265.860 905.460 266.140 ;
      RECT 0.840 270.340 905.460 270.620 ;
      RECT 0.840 274.820 905.460 275.100 ;
      RECT 0.840 279.300 905.460 279.580 ;
      RECT 0.840 283.780 905.460 284.060 ;
      RECT 0.840 288.260 905.460 288.540 ;
      RECT 0.840 292.740 905.460 293.020 ;
      RECT 0.840 297.220 905.460 297.500 ;
      RECT 0.840 301.700 905.460 301.980 ;
      RECT 0.840 306.180 905.460 306.460 ;
      RECT 0.840 310.660 905.460 310.940 ;
      RECT 0.840 315.140 905.460 315.420 ;
      RECT 0.840 319.620 905.460 319.900 ;
      RECT 0.840 324.100 905.460 324.380 ;
      RECT 0.840 328.580 905.460 328.860 ;
      RECT 0.840 333.060 905.460 333.340 ;
      RECT 0.840 337.540 905.460 337.820 ;
      RECT 0.840 342.020 905.460 342.300 ;
      RECT 0.840 346.500 905.460 346.780 ;
      RECT 0.840 350.980 905.460 351.260 ;
      RECT 0.840 355.460 905.460 355.740 ;
      RECT 0.840 359.940 905.460 360.220 ;
      RECT 0.840 364.420 905.460 364.700 ;
      RECT 0.840 368.900 905.460 369.180 ;
      RECT 0.840 373.380 905.460 373.660 ;
      RECT 0.840 377.860 905.460 378.140 ;
      RECT 0.840 382.340 905.460 382.620 ;
      RECT 0.840 386.820 905.460 387.100 ;
      RECT 0.840 391.300 905.460 391.580 ;
      RECT 0.840 395.780 905.460 396.060 ;
      RECT 0.840 400.260 905.460 400.540 ;
      RECT 0.840 404.740 905.460 405.020 ;
      RECT 0.840 409.220 905.460 409.500 ;
      RECT 0.840 413.700 905.460 413.980 ;
      RECT 0.840 418.180 905.460 418.460 ;
      RECT 0.840 422.660 905.460 422.940 ;
      RECT 0.840 427.140 905.460 427.420 ;
      RECT 0.840 431.620 905.460 431.900 ;
      RECT 0.840 436.100 905.460 436.380 ;
      RECT 0.840 440.580 905.460 440.860 ;
      RECT 0.840 445.060 905.460 445.340 ;
      RECT 0.840 449.540 905.460 449.820 ;
      RECT 0.840 454.020 905.460 454.300 ;
      RECT 0.840 458.500 905.460 458.780 ;
      RECT 0.840 462.980 905.460 463.260 ;
      RECT 0.840 467.460 905.460 467.740 ;
      RECT 0.840 471.940 905.460 472.220 ;
      RECT 0.840 476.420 905.460 476.700 ;
      RECT 0.840 480.900 905.460 481.180 ;
      RECT 0.840 485.380 905.460 485.660 ;
      RECT 0.840 489.860 905.460 490.140 ;
      RECT 0.840 494.340 905.460 494.620 ;
      RECT 0.840 498.820 905.460 499.100 ;
      RECT 0.840 503.300 905.460 503.580 ;
      RECT 0.840 507.780 905.460 508.060 ;
      RECT 0.840 512.260 905.460 512.540 ;
      RECT 0.840 516.740 905.460 517.020 ;
      RECT 0.840 521.220 905.460 521.500 ;
      RECT 0.840 525.700 905.460 525.980 ;
      RECT 0.840 530.180 905.460 530.460 ;
      RECT 0.840 534.660 905.460 534.940 ;
      RECT 0.840 539.140 905.460 539.420 ;
      RECT 0.840 543.620 905.460 543.900 ;
      RECT 0.840 548.100 905.460 548.380 ;
      RECT 0.840 552.580 905.460 552.860 ;
      RECT 0.840 557.060 905.460 557.340 ;
      RECT 0.840 561.540 905.460 561.820 ;
      RECT 0.840 566.020 905.460 566.300 ;
      RECT 0.840 570.500 905.460 570.780 ;
      RECT 0.840 574.980 905.460 575.260 ;
      RECT 0.840 579.460 905.460 579.740 ;
      RECT 0.840 583.940 905.460 584.220 ;
      RECT 0.840 588.420 905.460 588.700 ;
      RECT 0.840 592.900 905.460 593.180 ;
      RECT 0.840 597.380 905.460 597.660 ;
      RECT 0.840 601.860 905.460 602.140 ;
      RECT 0.840 606.340 905.460 606.620 ;
      RECT 0.840 610.820 905.460 611.100 ;
      RECT 0.840 615.300 905.460 615.580 ;
      RECT 0.840 619.780 905.460 620.060 ;
      RECT 0.840 624.260 905.460 624.540 ;
      RECT 0.840 628.740 905.460 629.020 ;
      RECT 0.840 633.220 905.460 633.500 ;
      RECT 0.840 637.700 905.460 637.980 ;
      RECT 0.840 642.180 905.460 642.460 ;
      RECT 0.840 646.660 905.460 646.940 ;
      RECT 0.840 651.140 905.460 651.420 ;
      RECT 0.840 655.620 905.460 655.900 ;
      RECT 0.840 660.100 905.460 660.380 ;
      RECT 0.840 664.580 905.460 664.860 ;
      RECT 0.840 669.060 905.460 669.340 ;
      RECT 0.840 673.540 905.460 673.820 ;
      RECT 0.840 678.020 905.460 678.300 ;
      RECT 0.840 682.500 905.460 682.780 ;
      RECT 0.840 686.980 905.460 687.260 ;
      RECT 0.840 691.460 905.460 691.740 ;
      RECT 0.840 695.940 905.460 696.220 ;
      RECT 0.840 700.420 905.460 700.700 ;
      RECT 0.840 704.900 905.460 705.180 ;
      RECT 0.840 709.380 905.460 709.660 ;
      RECT 0.840 713.860 905.460 714.140 ;
      RECT 0.840 718.340 905.460 718.620 ;
      RECT 0.840 722.820 905.460 723.100 ;
      RECT 0.840 727.300 905.460 727.580 ;
      RECT 0.840 731.780 905.460 732.060 ;
      RECT 0.840 736.260 905.460 736.540 ;
      RECT 0.840 740.740 905.460 741.020 ;
      RECT 0.840 745.220 905.460 745.500 ;
      RECT 0.840 749.700 905.460 749.980 ;
      RECT 0.840 754.180 905.460 754.460 ;
      RECT 0.840 758.660 905.460 758.940 ;
      RECT 0.840 763.140 905.460 763.420 ;
      RECT 0.840 767.620 905.460 767.900 ;
      RECT 0.840 772.100 905.460 772.380 ;
      RECT 0.840 776.580 905.460 776.860 ;
      RECT 0.840 781.060 905.460 781.340 ;
    END
  END VDD
  OBS
    LAYER metal1 ;
    RECT 0 0 906.300 784.000 ;
    LAYER metal2 ;
    RECT 0 0 906.300 784.000 ;
    LAYER metal3 ;
    RECT 0 0 906.300 784.000 ;
    LAYER metal4 ;
    RECT 0 0 906.300 784.000 ;
    LAYER OVERLAP ;
    RECT 0 0 906.300 784.000 ;
  END
END fakeram_512x512_1r1w

END LIBRARY
